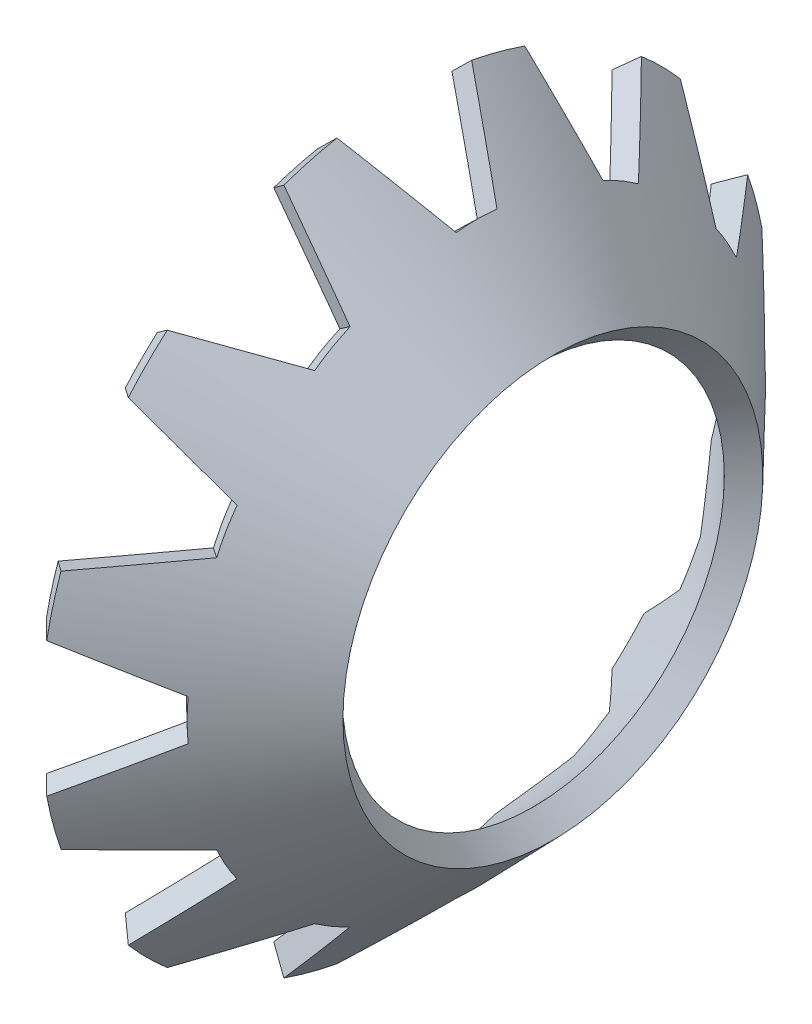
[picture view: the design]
ISO-10303-21;
HEADER;
FILE_DESCRIPTION(('STEP AP214'),'2;1');
FILE_NAME('part.step','',(''),(''),'','','');
FILE_SCHEMA(('AUTOMOTIVE_DESIGN { 1 0 10303 214 1 1 1 1 }'));
ENDSEC;
DATA;
#1=APPLICATION_CONTEXT('core data for automotive mechanical design processes');
#2=APPLICATION_PROTOCOL_DEFINITION('international standard','automotive_design',2000,#1);
#3=PRODUCT_CONTEXT('',#1,'mechanical');
#4=PRODUCT('Part','Part','',(#3));
#5=PRODUCT_RELATED_PRODUCT_CATEGORY('part','',(#4));
#6=PRODUCT_DEFINITION_FORMATION('','',#4);
#7=PRODUCT_DEFINITION_CONTEXT('part definition',#1,'design');
#8=PRODUCT_DEFINITION('design','',#6,#7);
#9=PRODUCT_DEFINITION_SHAPE('','',#8);
#10=(LENGTH_UNIT() NAMED_UNIT(*) SI_UNIT(.MILLI.,.METRE.));
#11=(NAMED_UNIT(*) PLANE_ANGLE_UNIT() SI_UNIT($,.RADIAN.));
#12=(NAMED_UNIT(*) SI_UNIT($,.STERADIAN.) SOLID_ANGLE_UNIT());
#13=UNCERTAINTY_MEASURE_WITH_UNIT(LENGTH_MEASURE(1.E-05),#10,'distance_accuracy_value','');
#14=(GEOMETRIC_REPRESENTATION_CONTEXT(3) GLOBAL_UNCERTAINTY_ASSIGNED_CONTEXT((#13)) GLOBAL_UNIT_ASSIGNED_CONTEXT((#10,
#11,#12)) REPRESENTATION_CONTEXT('',''));
#15=CARTESIAN_POINT('',(0.,0.,0.));
#16=DIRECTION('',(0.,0.,1.));
#17=DIRECTION('',(1.,0.,0.));
#18=AXIS2_PLACEMENT_3D('',#15,#16,#17);
#19=CARTESIAN_POINT('',(-8.15711407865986,0.,0.));
#20=DIRECTION('',(1.,0.,0.));
#21=DIRECTION('',(0.,0.,-1.));
#22=AXIS2_PLACEMENT_3D('',#19,#20,#21);
#23=CONICAL_SURFACE('',#22,7.5832049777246,0.767944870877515);
#24=CARTESIAN_POINT('',(-8.15731407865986,5.7023043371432,4.99857917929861));
#25=CARTESIAN_POINT('',(-8.08534474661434,5.76337965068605,5.03433654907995));
#26=CARTESIAN_POINT('',(-8.0133597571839,5.82444644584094,5.07007692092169));
#27=CARTESIAN_POINT('',(-7.86935846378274,5.94656299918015,5.14152366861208));
#28=CARTESIAN_POINT('',(-7.79734215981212,6.00761275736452,5.17723004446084));
#29=CARTESIAN_POINT('',(-7.72531019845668,6.06865399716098,5.21291942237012));
#30=B_SPLINE_CURVE_WITH_KNOTS('',3,(#24,#25,#26,#27,#28,#29),.UNSPECIFIED.,.F.,.F.,(4,2,4),(0.,
0.302812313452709,0.605624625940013),.UNSPECIFIED.);
#31=CARTESIAN_POINT('',(-8.15711407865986,5.7024740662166,4.99867855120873));
#32=VERTEX_POINT('',#31);
#33=CARTESIAN_POINT('',(-7.72551019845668,6.0684845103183,5.21282032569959));
#34=VERTEX_POINT('',#33);
#35=EDGE_CURVE('E1146',#32,#34,#30,.T.);
#36=ORIENTED_EDGE('',*,*,#35,.F.);
#37=CARTESIAN_POINT('',(-8.15711407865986,0.,0.));
#38=DIRECTION('',(-1.,0.,0.));
#39=DIRECTION('',(0.,0.,1.));
#40=AXIS2_PLACEMENT_3D('',#37,#38,#39);
#41=CIRCLE('',#40,7.5832049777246);
#42=CARTESIAN_POINT('',(-8.15711407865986,4.99867855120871,5.70247406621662));
#43=VERTEX_POINT('',#42);
#44=EDGE_CURVE('E1163',#43,#32,#41,.T.);
#45=ORIENTED_EDGE('',*,*,#44,.F.);
#46=CARTESIAN_POINT('',(-7.72531019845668,5.2129194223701,6.068653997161));
#47=CARTESIAN_POINT('',(-7.79734215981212,5.17723004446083,6.00761275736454));
#48=CARTESIAN_POINT('',(-7.86935846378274,5.14152366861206,5.94656299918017));
#49=CARTESIAN_POINT('',(-8.0133597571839,5.07007692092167,5.82444644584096));
#50=CARTESIAN_POINT('',(-8.08534474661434,5.03433654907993,5.76337965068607));
#51=CARTESIAN_POINT('',(-8.15731407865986,4.99857917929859,5.70230433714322));
#52=B_SPLINE_CURVE_WITH_KNOTS('',3,(#46,#47,#48,#49,#50,#51),.UNSPECIFIED.,.F.,.F.,(4,2,4),(0.,
0.302812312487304,0.605624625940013),.UNSPECIFIED.);
#53=CARTESIAN_POINT('',(-7.72551019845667,5.21282032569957,6.06848451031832));
#54=VERTEX_POINT('',#53);
#55=EDGE_CURVE('E374',#54,#43,#52,.T.);
#56=ORIENTED_EDGE('',*,*,#55,.F.);
#57=CARTESIAN_POINT('',(-7.72551019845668,0.,0.));
#58=DIRECTION('',(-1.,0.,0.));
#59=DIRECTION('',(0.,0.,1.));
#60=AXIS2_PLACEMENT_3D('',#57,#58,#59);
#61=CIRCLE('',#60,8.);
#62=EDGE_CURVE('E372',#54,#34,#61,.T.);
#63=ORIENTED_EDGE('',*,*,#62,.T.);
#64=EDGE_LOOP('',(#36,#45,#56,#63));
#65=FACE_BOUND('',#64,.T.);
#66=ADVANCED_FACE('F32',(#65),#23,.T.);
#67=CARTESIAN_POINT('',(-7.72531019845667,-7.54884764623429,-2.6491488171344));
#68=CARTESIAN_POINT('',(-7.79734215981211,-7.48741911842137,-2.6141302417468));
#69=CARTESIAN_POINT('',(-7.86935846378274,-7.42597161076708,-2.57911278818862));
#70=CARTESIAN_POINT('',(-8.0133597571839,-7.30303863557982,-2.50908012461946));
#71=CARTESIAN_POINT('',(-8.08534474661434,-7.24155316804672,-2.4740649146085));
#72=CARTESIAN_POINT('',(-8.15731407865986,-7.18004872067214,-2.43905082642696));
#73=B_SPLINE_CURVE_WITH_KNOTS('',3,(#67,#68,#69,#70,#71,#72),.UNSPECIFIED.,.F.,.F.,(4,2,4),(0.,
0.30281231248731,0.605624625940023),.UNSPECIFIED.);
#74=CARTESIAN_POINT('',(-7.72551019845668,-7.54867708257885,-2.6490515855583));
#75=VERTEX_POINT('',#74);
#76=CARTESIAN_POINT('',(-8.15711407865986,-7.18021964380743,-2.43914813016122));
#77=VERTEX_POINT('',#76);
#78=EDGE_CURVE('E970',#75,#77,#73,.T.);
#79=ORIENTED_EDGE('',*,*,#78,.F.);
#80=CARTESIAN_POINT('',(-7.72551019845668,-7.86187191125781,-1.48019257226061));
#81=VERTEX_POINT('',#80);
#82=EDGE_CURVE('E797',#75,#81,#61,.T.);
#83=ORIENTED_EDGE('',*,*,#82,.T.);
#84=CARTESIAN_POINT('',(-8.15731407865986,-7.43763000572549,-1.47774438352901));
#85=CARTESIAN_POINT('',(-8.08534474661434,-7.50840146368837,-1.47817351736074));
#86=CARTESIAN_POINT('',(-8.01335975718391,-7.57915704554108,-1.47859218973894));
#87=CARTESIAN_POINT('',(-7.86935846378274,-7.72063645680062,-1.479408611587));
#88=CARTESIAN_POINT('',(-7.79734215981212,-7.79136028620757,-1.47980636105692));
#89=CARTESIAN_POINT('',(-7.72531019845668,-7.86206823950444,-1.48019364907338));
#90=B_SPLINE_CURVE_WITH_KNOTS('',3,(#84,#85,#86,#87,#88,#89),.UNSPECIFIED.,.F.,.F.,(4,2,4),(0.,
0.302812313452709,0.605624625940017),.UNSPECIFIED.);
#91=CARTESIAN_POINT('',(-8.15711407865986,-7.43782668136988,-1.4777455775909));
#92=VERTEX_POINT('',#91);
#93=EDGE_CURVE('E354',#92,#81,#90,.T.);
#94=ORIENTED_EDGE('',*,*,#93,.F.);
#95=EDGE_CURVE('E740',#77,#92,#41,.T.);
#96=ORIENTED_EDGE('',*,*,#95,.F.);
#97=EDGE_LOOP('',(#79,#83,#94,#96));
#98=FACE_BOUND('',#97,.T.);
#99=ADVANCED_FACE('F703',(#98),#23,.T.);
#100=CARTESIAN_POINT('',(-8.15731407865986,-2.43905082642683,-7.18004872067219));
#101=CARTESIAN_POINT('',(-8.08534474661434,-2.47406491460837,-7.24155316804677));
#102=CARTESIAN_POINT('',(-8.0133597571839,-2.50908012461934,-7.30303863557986));
#103=CARTESIAN_POINT('',(-7.86935846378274,-2.57911278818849,-7.42597161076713));
#104=CARTESIAN_POINT('',(-7.79734215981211,-2.61413024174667,-7.48741911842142));
#105=CARTESIAN_POINT('',(-7.72531019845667,-2.64914881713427,-7.54884764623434));
#106=B_SPLINE_CURVE_WITH_KNOTS('',3,(#100,#101,#102,#103,#104,#105),.UNSPECIFIED.,.F.,.F.,(4,2,
4),(0.,0.302812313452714,0.605624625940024),.UNSPECIFIED.);
#107=CARTESIAN_POINT('',(-8.15711407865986,-2.4391481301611,-7.18021964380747));
#108=VERTEX_POINT('',#107);
#109=CARTESIAN_POINT('',(-7.72551019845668,-2.64905158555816,-7.54867708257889));
#110=VERTEX_POINT('',#109);
#111=EDGE_CURVE('E1334',#108,#110,#106,.T.);
#112=ORIENTED_EDGE('',*,*,#111,.F.);
#113=CARTESIAN_POINT('',(-8.15711407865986,-1.47774557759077,-7.4378266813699));
#114=VERTEX_POINT('',#113);
#115=EDGE_CURVE('E739',#114,#108,#41,.T.);
#116=ORIENTED_EDGE('',*,*,#115,.F.);
#117=CARTESIAN_POINT('',(-7.72531019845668,-1.48019364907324,-7.86206823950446));
#118=CARTESIAN_POINT('',(-7.79734215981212,-1.47980636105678,-7.79136028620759));
#119=CARTESIAN_POINT('',(-7.86935846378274,-1.47940861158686,-7.72063645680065));
#120=CARTESIAN_POINT('',(-8.01335975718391,-1.47859218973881,-7.5791570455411));
#121=CARTESIAN_POINT('',(-8.08534474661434,-1.47817351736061,-7.50840146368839));
#122=CARTESIAN_POINT('',(-8.15731407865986,-1.47774438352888,-7.43763000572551));
#123=B_SPLINE_CURVE_WITH_KNOTS('',3,(#117,#118,#119,#120,#121,#122),.UNSPECIFIED.,.F.,.F.,(4,2,
4),(0.,0.302812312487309,0.605624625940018),.UNSPECIFIED.);
#124=CARTESIAN_POINT('',(-7.72551019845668,-1.48019257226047,-7.86187191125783));
#125=VERTEX_POINT('',#124);
#126=EDGE_CURVE('E867',#125,#114,#123,.T.);
#127=ORIENTED_EDGE('',*,*,#126,.F.);
#128=EDGE_CURVE('E806',#125,#110,#61,.T.);
#129=ORIENTED_EDGE('',*,*,#128,.T.);
#130=EDGE_LOOP('',(#112,#116,#127,#129));
#131=FACE_BOUND('',#130,.T.);
#132=ADVANCED_FACE('F708',(#131),#23,.T.);
#133=CARTESIAN_POINT('',(-7.72531019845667,2.64914881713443,-7.54884764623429));
#134=CARTESIAN_POINT('',(-7.79734215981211,2.61413024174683,-7.48741911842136));
#135=CARTESIAN_POINT('',(-7.86935846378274,2.57911278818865,-7.42597161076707));
#136=CARTESIAN_POINT('',(-8.0133597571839,2.50908012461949,-7.30303863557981));
#137=CARTESIAN_POINT('',(-8.08534474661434,2.47406491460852,-7.24155316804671));
#138=CARTESIAN_POINT('',(-8.15731407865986,2.43905082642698,-7.18004872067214));
#139=B_SPLINE_CURVE_WITH_KNOTS('',3,(#133,#134,#135,#136,#137,#138),.UNSPECIFIED.,.F.,.F.,(4,2,
4),(0.,0.30281231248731,0.605624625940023),.UNSPECIFIED.);
#140=CARTESIAN_POINT('',(-7.72551019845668,2.64905158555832,-7.54867708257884));
#141=VERTEX_POINT('',#140);
#142=CARTESIAN_POINT('',(-8.15711407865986,2.43914813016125,-7.18021964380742));
#143=VERTEX_POINT('',#142);
#144=EDGE_CURVE('E821',#141,#143,#139,.T.);
#145=ORIENTED_EDGE('',*,*,#144,.F.);
#146=CARTESIAN_POINT('',(-7.72551019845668,1.48019257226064,-7.8618719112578));
#147=VERTEX_POINT('',#146);
#148=EDGE_CURVE('E772',#141,#147,#61,.T.);
#149=ORIENTED_EDGE('',*,*,#148,.T.);
#150=CARTESIAN_POINT('',(-8.15731407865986,1.47774438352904,-7.43763000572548));
#151=CARTESIAN_POINT('',(-8.08534474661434,1.47817351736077,-7.50840146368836));
#152=CARTESIAN_POINT('',(-8.01335975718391,1.47859218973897,-7.57915704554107));
#153=CARTESIAN_POINT('',(-7.86935846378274,1.47940861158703,-7.72063645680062));
#154=CARTESIAN_POINT('',(-7.79734215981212,1.47980636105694,-7.79136028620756));
#155=CARTESIAN_POINT('',(-7.72531019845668,1.48019364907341,-7.86206823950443));
#156=B_SPLINE_CURVE_WITH_KNOTS('',3,(#150,#151,#152,#153,#154,#155),.UNSPECIFIED.,.F.,.F.,(4,2,
4),(0.,0.302812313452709,0.605624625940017),.UNSPECIFIED.);
#157=CARTESIAN_POINT('',(-8.15711407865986,1.47774557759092,-7.43782668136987));
#158=VERTEX_POINT('',#157);
#159=EDGE_CURVE('E819',#158,#147,#156,.T.);
#160=ORIENTED_EDGE('',*,*,#159,.F.);
#161=EDGE_CURVE('E743',#143,#158,#41,.T.);
#162=ORIENTED_EDGE('',*,*,#161,.F.);
#163=EDGE_LOOP('',(#145,#149,#160,#162));
#164=FACE_BOUND('',#163,.T.);
#165=ADVANCED_FACE('F817',(#164),#23,.T.);
#166=CARTESIAN_POINT('',(-8.15731407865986,4.99857917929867,-5.70230433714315));
#167=CARTESIAN_POINT('',(-8.08534474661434,5.03433654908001,-5.763379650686));
#168=CARTESIAN_POINT('',(-8.0133597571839,5.07007692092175,-5.82444644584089));
#169=CARTESIAN_POINT('',(-7.86935846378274,5.14152366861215,-5.9465629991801));
#170=CARTESIAN_POINT('',(-7.79734215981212,5.17723004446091,-6.00761275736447));
#171=CARTESIAN_POINT('',(-7.72531019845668,5.21291942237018,-6.06865399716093));
#172=B_SPLINE_CURVE_WITH_KNOTS('',3,(#166,#167,#168,#169,#170,#171),.UNSPECIFIED.,.F.,.F.,(4,2,
4),(0.,0.302812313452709,0.605624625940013),.UNSPECIFIED.);
#173=CARTESIAN_POINT('',(-8.15711407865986,4.99867855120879,-5.70247406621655));
#174=VERTEX_POINT('',#173);
#175=CARTESIAN_POINT('',(-7.72551019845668,5.21282032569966,-6.06848451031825));
#176=VERTEX_POINT('',#175);
#177=EDGE_CURVE('E907',#174,#176,#172,.T.);
#178=ORIENTED_EDGE('',*,*,#177,.F.);
#179=CARTESIAN_POINT('',(-8.15711407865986,5.70247406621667,-4.99867855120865));
#180=VERTEX_POINT('',#179);
#181=EDGE_CURVE('E751',#180,#174,#41,.T.);
#182=ORIENTED_EDGE('',*,*,#181,.F.);
#183=CARTESIAN_POINT('',(-7.72531019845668,6.06865399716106,-5.21291942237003));
#184=CARTESIAN_POINT('',(-7.79734215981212,6.00761275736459,-5.17723004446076));
#185=CARTESIAN_POINT('',(-7.86935846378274,5.94656299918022,-5.141523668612));
#186=CARTESIAN_POINT('',(-8.0133597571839,5.82444644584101,-5.07007692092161));
#187=CARTESIAN_POINT('',(-8.08534474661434,5.76337965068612,-5.03433654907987));
#188=CARTESIAN_POINT('',(-8.15731407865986,5.70230433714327,-4.99857917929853));
#189=B_SPLINE_CURVE_WITH_KNOTS('',3,(#183,#184,#185,#186,#187,#188),.UNSPECIFIED.,.F.,.F.,(4,2,
4),(0.,0.302812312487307,0.605624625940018),.UNSPECIFIED.);
#190=CARTESIAN_POINT('',(-7.72551019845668,6.06848451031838,-5.21282032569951));
#191=VERTEX_POINT('',#190);
#192=EDGE_CURVE('E834',#191,#180,#189,.T.);
#193=ORIENTED_EDGE('',*,*,#192,.F.);
#194=EDGE_CURVE('E765',#191,#176,#61,.T.);
#195=ORIENTED_EDGE('',*,*,#194,.T.);
#196=EDGE_LOOP('',(#178,#182,#193,#195));
#197=FACE_BOUND('',#196,.T.);
#198=ADVANCED_FACE('F1286',(#197),#23,.T.);
#199=CARTESIAN_POINT('',(-8.15731407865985,7.1800487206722,-2.43905082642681));
#200=CARTESIAN_POINT('',(-8.08534474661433,7.24155316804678,-2.47406491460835));
#201=CARTESIAN_POINT('',(-8.0133597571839,7.30303863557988,-2.50908012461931));
#202=CARTESIAN_POINT('',(-7.86935846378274,7.42597161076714,-2.57911278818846));
#203=CARTESIAN_POINT('',(-7.79734215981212,7.48741911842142,-2.61413024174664));
#204=CARTESIAN_POINT('',(-7.72531019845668,7.54884764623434,-2.64914881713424));
#205=B_SPLINE_CURVE_WITH_KNOTS('',3,(#199,#200,#201,#202,#203,#204),.UNSPECIFIED.,.F.,.F.,(4,2,
4),(0.,0.302812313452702,0.605624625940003),.UNSPECIFIED.);
#206=CARTESIAN_POINT('',(-8.15711407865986,7.18021964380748,-2.43914813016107));
#207=VERTEX_POINT('',#206);
#208=CARTESIAN_POINT('',(-7.72551019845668,7.5486770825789,-2.64905158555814));
#209=VERTEX_POINT('',#208);
#210=EDGE_CURVE('E886',#207,#209,#205,.T.);
#211=ORIENTED_EDGE('',*,*,#210,.F.);
#212=CARTESIAN_POINT('',(-8.15711407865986,7.43782668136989,-1.47774557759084));
#213=VERTEX_POINT('',#212);
#214=EDGE_CURVE('E746',#213,#207,#41,.T.);
#215=ORIENTED_EDGE('',*,*,#214,.F.);
#216=CARTESIAN_POINT('',(-7.72531019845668,7.86206823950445,-1.48019364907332));
#217=CARTESIAN_POINT('',(-7.79734215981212,7.79136028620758,-1.47980636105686));
#218=CARTESIAN_POINT('',(-7.86935846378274,7.72063645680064,-1.47940861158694));
#219=CARTESIAN_POINT('',(-8.01335975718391,7.57915704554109,-1.47859218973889));
#220=CARTESIAN_POINT('',(-8.08534474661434,7.50840146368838,-1.47817351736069));
#221=CARTESIAN_POINT('',(-8.15731407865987,7.4376300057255,-1.47774438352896));
#222=B_SPLINE_CURVE_WITH_KNOTS('',3,(#216,#217,#218,#219,#220,#221),.UNSPECIFIED.,.F.,.F.,(4,2,
4),(0.,0.302812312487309,0.605624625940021),.UNSPECIFIED.);
#223=CARTESIAN_POINT('',(-7.72551019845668,7.86187191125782,-1.48019257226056));
#224=VERTEX_POINT('',#223);
#225=EDGE_CURVE('E679',#224,#213,#222,.T.);
#226=ORIENTED_EDGE('',*,*,#225,.F.);
#227=EDGE_CURVE('E763',#224,#209,#61,.T.);
#228=ORIENTED_EDGE('',*,*,#227,.T.);
#229=EDGE_LOOP('',(#211,#215,#226,#228));
#230=FACE_BOUND('',#229,.T.);
#231=ADVANCED_FACE('F1183',(#230),#23,.T.);
#232=CARTESIAN_POINT('',(-8.15731407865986,-4.99857917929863,5.70230433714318));
#233=CARTESIAN_POINT('',(-8.08534474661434,-5.03433654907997,5.76337965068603));
#234=CARTESIAN_POINT('',(-8.01335975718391,-5.07007692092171,5.82444644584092));
#235=CARTESIAN_POINT('',(-7.86935846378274,-5.14152366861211,5.94656299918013));
#236=CARTESIAN_POINT('',(-7.79734215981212,-5.17723004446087,6.0076127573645));
#237=CARTESIAN_POINT('',(-7.72531019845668,-5.21291942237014,6.06865399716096));
#238=B_SPLINE_CURVE_WITH_KNOTS('',3,(#232,#233,#234,#235,#236,#237),.UNSPECIFIED.,.F.,.F.,(4,2,
4),(0.,0.302812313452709,0.605624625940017),.UNSPECIFIED.);
#239=CARTESIAN_POINT('',(-8.15711407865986,-4.99867855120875,5.70247406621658));
#240=VERTEX_POINT('',#239);
#241=CARTESIAN_POINT('',(-7.72551019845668,-5.21282032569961,6.06848451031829));
#242=VERTEX_POINT('',#241);
#243=EDGE_CURVE('E1104',#240,#242,#238,.T.);
#244=ORIENTED_EDGE('',*,*,#243,.F.);
#245=CARTESIAN_POINT('',(-8.15711407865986,-5.70247406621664,4.99867855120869));
#246=VERTEX_POINT('',#245);
#247=EDGE_CURVE('E1232',#246,#240,#41,.T.);
#248=ORIENTED_EDGE('',*,*,#247,.F.);
#249=CARTESIAN_POINT('',(-7.72531019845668,-6.06865399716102,5.21291942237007));
#250=CARTESIAN_POINT('',(-7.79734215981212,-6.00761275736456,5.1772300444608));
#251=CARTESIAN_POINT('',(-7.86935846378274,-5.94656299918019,5.14152366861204));
#252=CARTESIAN_POINT('',(-8.0133597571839,-5.82444644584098,5.07007692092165));
#253=CARTESIAN_POINT('',(-8.08534474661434,-5.76337965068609,5.03433654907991));
#254=CARTESIAN_POINT('',(-8.15731407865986,-5.70230433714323,4.99857917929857));
#255=B_SPLINE_CURVE_WITH_KNOTS('',3,(#249,#250,#251,#252,#253,#254),.UNSPECIFIED.,.F.,.F.,(4,2,
4),(0.,0.302812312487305,0.605624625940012),.UNSPECIFIED.);
#256=CARTESIAN_POINT('',(-7.72551019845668,-6.06848451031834,5.21282032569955));
#257=VERTEX_POINT('',#256);
#258=EDGE_CURVE('E1220',#257,#246,#255,.T.);
#259=ORIENTED_EDGE('',*,*,#258,.F.);
#260=EDGE_CURVE('E786',#257,#242,#61,.T.);
#261=ORIENTED_EDGE('',*,*,#260,.T.);
#262=EDGE_LOOP('',(#244,#248,#259,#261));
#263=FACE_BOUND('',#262,.T.);
#264=ADVANCED_FACE('F1230',(#263),#23,.T.);
#265=CARTESIAN_POINT('',(-7.72531019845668,1.4801936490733,7.86206823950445));
#266=CARTESIAN_POINT('',(-7.79734215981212,1.47980636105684,7.79136028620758));
#267=CARTESIAN_POINT('',(-7.86935846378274,1.47940861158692,7.72063645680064));
#268=CARTESIAN_POINT('',(-8.01335975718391,1.47859218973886,7.57915704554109));
#269=CARTESIAN_POINT('',(-8.08534474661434,1.47817351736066,7.50840146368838));
#270=CARTESIAN_POINT('',(-8.15731407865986,1.47774438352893,7.4376300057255));
#271=B_SPLINE_CURVE_WITH_KNOTS('',3,(#265,#266,#267,#268,#269,#270),.UNSPECIFIED.,.F.,.F.,(4,2,
4),(0.,0.302812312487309,0.605624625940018),.UNSPECIFIED.);
#272=CARTESIAN_POINT('',(-7.72551019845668,1.48019257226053,7.86187191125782));
#273=VERTEX_POINT('',#272);
#274=CARTESIAN_POINT('',(-8.15711407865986,1.47774557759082,7.43782668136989));
#275=VERTEX_POINT('',#274);
#276=EDGE_CURVE('E1070',#273,#275,#271,.T.);
#277=ORIENTED_EDGE('',*,*,#276,.F.);
#278=CARTESIAN_POINT('',(-7.72551019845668,2.64905158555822,7.54867708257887));
#279=VERTEX_POINT('',#278);
#280=EDGE_CURVE('E778',#273,#279,#61,.T.);
#281=ORIENTED_EDGE('',*,*,#280,.T.);
#282=CARTESIAN_POINT('',(-8.15731407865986,2.43905082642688,7.18004872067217));
#283=CARTESIAN_POINT('',(-8.08534474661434,2.47406491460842,7.24155316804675));
#284=CARTESIAN_POINT('',(-8.0133597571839,2.50908012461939,7.30303863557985));
#285=CARTESIAN_POINT('',(-7.86935846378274,2.57911278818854,7.42597161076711));
#286=CARTESIAN_POINT('',(-7.79734215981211,2.61413024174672,7.4874191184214));
#287=CARTESIAN_POINT('',(-7.72531019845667,2.64914881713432,7.54884764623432));
#288=B_SPLINE_CURVE_WITH_KNOTS('',3,(#282,#283,#284,#285,#286,#287),.UNSPECIFIED.,.F.,.F.,(4,2,
4),(0.,0.302812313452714,0.605624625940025),.UNSPECIFIED.);
#289=CARTESIAN_POINT('',(-8.15711407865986,2.43914813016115,7.18021964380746));
#290=VERTEX_POINT('',#289);
#291=EDGE_CURVE('E1193',#290,#279,#288,.T.);
#292=ORIENTED_EDGE('',*,*,#291,.F.);
#293=EDGE_CURVE('E1164',#275,#290,#41,.T.);
#294=ORIENTED_EDGE('',*,*,#293,.F.);
#295=EDGE_LOOP('',(#277,#281,#292,#294));
#296=FACE_BOUND('',#295,.T.);
#297=ADVANCED_FACE('F1194',(#296),#23,.T.);
#298=CARTESIAN_POINT('',(-8.15731407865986,-7.18004872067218,2.43905082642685));
#299=CARTESIAN_POINT('',(-8.08534474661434,-7.24155316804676,2.47406491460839));
#300=CARTESIAN_POINT('',(-8.0133597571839,-7.30303863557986,2.50908012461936));
#301=CARTESIAN_POINT('',(-7.86935846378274,-7.42597161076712,2.57911278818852));
#302=CARTESIAN_POINT('',(-7.79734215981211,-7.48741911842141,2.6141302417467));
#303=CARTESIAN_POINT('',(-7.72531019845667,-7.54884764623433,2.6491488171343));
#304=B_SPLINE_CURVE_WITH_KNOTS('',3,(#298,#299,#300,#301,#302,#303),.UNSPECIFIED.,.F.,.F.,(4,2,
4),(0.,0.302812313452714,0.605624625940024),.UNSPECIFIED.);
#305=CARTESIAN_POINT('',(-8.15711407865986,-7.18021964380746,2.43914813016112));
#306=VERTEX_POINT('',#305);
#307=CARTESIAN_POINT('',(-7.72551019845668,-7.54867708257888,2.64905158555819));
#308=VERTEX_POINT('',#307);
#309=EDGE_CURVE('E1028',#306,#308,#304,.T.);
#310=ORIENTED_EDGE('',*,*,#309,.F.);
#311=CARTESIAN_POINT('',(-8.15711407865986,-7.4378266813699,1.47774557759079));
#312=VERTEX_POINT('',#311);
#313=EDGE_CURVE('E745',#312,#306,#41,.T.);
#314=ORIENTED_EDGE('',*,*,#313,.F.);
#315=CARTESIAN_POINT('',(-7.72531019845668,-7.86206823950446,1.48019364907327));
#316=CARTESIAN_POINT('',(-7.79734215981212,-7.79136028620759,1.47980636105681));
#317=CARTESIAN_POINT('',(-7.86935846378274,-7.72063645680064,1.47940861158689));
#318=CARTESIAN_POINT('',(-8.01335975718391,-7.5791570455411,1.47859218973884));
#319=CARTESIAN_POINT('',(-8.08534474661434,-7.50840146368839,1.47817351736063));
#320=CARTESIAN_POINT('',(-8.15731407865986,-7.43763000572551,1.47774438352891));
#321=B_SPLINE_CURVE_WITH_KNOTS('',3,(#315,#316,#317,#318,#319,#320),.UNSPECIFIED.,.F.,.F.,(4,2,
4),(0.,0.302812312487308,0.605624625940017),.UNSPECIFIED.);
#322=CARTESIAN_POINT('',(-7.72551019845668,-7.86187191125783,1.4801925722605));
#323=VERTEX_POINT('',#322);
#324=EDGE_CURVE('E1201',#323,#312,#321,.T.);
#325=ORIENTED_EDGE('',*,*,#324,.F.);
#326=EDGE_CURVE('E791',#323,#308,#61,.T.);
#327=ORIENTED_EDGE('',*,*,#326,.T.);
#328=EDGE_LOOP('',(#310,#314,#325,#327));
#329=FACE_BOUND('',#328,.T.);
#330=ADVANCED_FACE('F1271',(#329),#23,.T.);
#331=CARTESIAN_POINT('',(-7.72531019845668,7.54884764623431,2.64914881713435));
#332=CARTESIAN_POINT('',(-7.79734215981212,7.48741911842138,2.61413024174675));
#333=CARTESIAN_POINT('',(-7.86935846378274,7.4259716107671,2.57911278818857));
#334=CARTESIAN_POINT('',(-8.0133597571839,7.30303863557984,2.50908012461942));
#335=CARTESIAN_POINT('',(-8.08534474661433,7.24155316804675,2.47406491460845));
#336=CARTESIAN_POINT('',(-8.15731407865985,7.18004872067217,2.43905082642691));
#337=B_SPLINE_CURVE_WITH_KNOTS('',3,(#331,#332,#333,#334,#335,#336),.UNSPECIFIED.,.F.,.F.,(4,2,
4),(0.,0.3028123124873,0.605624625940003),.UNSPECIFIED.);
#338=CARTESIAN_POINT('',(-7.72551019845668,7.54867708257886,2.64905158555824));
#339=VERTEX_POINT('',#338);
#340=CARTESIAN_POINT('',(-8.15711407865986,7.18021964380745,2.43914813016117));
#341=VERTEX_POINT('',#340);
#342=EDGE_CURVE('E373',#339,#341,#337,.T.);
#343=ORIENTED_EDGE('',*,*,#342,.F.);
#344=CARTESIAN_POINT('',(-7.72551019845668,7.86187191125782,1.48019257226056));
#345=VERTEX_POINT('',#344);
#346=EDGE_CURVE('E762',#339,#345,#61,.T.);
#347=ORIENTED_EDGE('',*,*,#346,.T.);
#348=CARTESIAN_POINT('',(-8.15731407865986,7.4376300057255,1.47774438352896));
#349=CARTESIAN_POINT('',(-8.08534474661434,7.50840146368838,1.47817351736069));
#350=CARTESIAN_POINT('',(-8.01335975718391,7.57915704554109,1.47859218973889));
#351=CARTESIAN_POINT('',(-7.86935846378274,7.72063645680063,1.47940861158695));
#352=CARTESIAN_POINT('',(-7.79734215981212,7.79136028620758,1.47980636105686));
#353=CARTESIAN_POINT('',(-7.72531019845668,7.86206823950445,1.48019364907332));
#354=B_SPLINE_CURVE_WITH_KNOTS('',3,(#348,#349,#350,#351,#352,#353),.UNSPECIFIED.,.F.,.F.,(4,2,
4),(0.,0.302812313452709,0.605624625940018),.UNSPECIFIED.);
#355=CARTESIAN_POINT('',(-8.15711407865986,7.43782668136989,1.47774557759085));
#356=VERTEX_POINT('',#355);
#357=EDGE_CURVE('E1173',#356,#345,#354,.T.);
#358=ORIENTED_EDGE('',*,*,#357,.F.);
#359=EDGE_CURVE('E752',#341,#356,#41,.T.);
#360=ORIENTED_EDGE('',*,*,#359,.F.);
#361=EDGE_LOOP('',(#343,#347,#358,#360));
#362=FACE_BOUND('',#361,.T.);
#363=ADVANCED_FACE('F718',(#362),#23,.T.);
#364=CARTESIAN_POINT('',(-7.72531019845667,-2.64914881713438,7.5488476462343));
#365=CARTESIAN_POINT('',(-7.79734215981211,-2.61413024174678,7.48741911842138));
#366=CARTESIAN_POINT('',(-7.86935846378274,-2.57911278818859,7.42597161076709));
#367=CARTESIAN_POINT('',(-8.0133597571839,-2.50908012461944,7.30303863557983));
#368=CARTESIAN_POINT('',(-8.08534474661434,-2.47406491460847,7.24155316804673));
#369=CARTESIAN_POINT('',(-8.15731407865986,-2.43905082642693,7.18004872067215));
#370=B_SPLINE_CURVE_WITH_KNOTS('',3,(#364,#365,#366,#367,#368,#369),.UNSPECIFIED.,.F.,.F.,(4,2,
4),(0.,0.302812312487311,0.605624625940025),.UNSPECIFIED.);
#371=CARTESIAN_POINT('',(-7.72551019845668,-2.64905158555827,7.54867708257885));
#372=VERTEX_POINT('',#371);
#373=CARTESIAN_POINT('',(-8.15711407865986,-2.4391481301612,7.18021964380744));
#374=VERTEX_POINT('',#373);
#375=EDGE_CURVE('E1080',#372,#374,#370,.T.);
#376=ORIENTED_EDGE('',*,*,#375,.F.);
#377=CARTESIAN_POINT('',(-7.72551019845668,-1.48019257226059,7.86187191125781));
#378=VERTEX_POINT('',#377);
#379=EDGE_CURVE('E780',#372,#378,#61,.T.);
#380=ORIENTED_EDGE('',*,*,#379,.T.);
#381=CARTESIAN_POINT('',(-8.15731407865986,-1.47774438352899,7.43763000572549));
#382=CARTESIAN_POINT('',(-8.08534474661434,-1.47817351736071,7.50840146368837));
#383=CARTESIAN_POINT('',(-8.01335975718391,-1.47859218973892,7.57915704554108));
#384=CARTESIAN_POINT('',(-7.86935846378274,-1.47940861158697,7.72063645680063));
#385=CARTESIAN_POINT('',(-7.79734215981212,-1.47980636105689,7.79136028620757));
#386=CARTESIAN_POINT('',(-7.72531019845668,-1.48019364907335,7.86206823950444));
#387=B_SPLINE_CURVE_WITH_KNOTS('',3,(#381,#382,#383,#384,#385,#386),.UNSPECIFIED.,.F.,.F.,(4,2,
4),(0.,0.302812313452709,0.605624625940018),.UNSPECIFIED.);
#388=CARTESIAN_POINT('',(-8.15711407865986,-1.47774557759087,7.43782668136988));
#389=VERTEX_POINT('',#388);
#390=EDGE_CURVE('E1044',#389,#378,#387,.T.);
#391=ORIENTED_EDGE('',*,*,#390,.F.);
#392=EDGE_CURVE('E1166',#374,#389,#41,.T.);
#393=ORIENTED_EDGE('',*,*,#392,.F.);
#394=EDGE_LOOP('',(#376,#380,#391,#393));
#395=FACE_BOUND('',#394,.T.);
#396=ADVANCED_FACE('F712',(#395),#23,.T.);
#397=CARTESIAN_POINT('',(-8.15731407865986,-5.70230433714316,-4.99857917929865));
#398=CARTESIAN_POINT('',(-8.08534474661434,-5.76337965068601,-5.03433654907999));
#399=CARTESIAN_POINT('',(-8.01335975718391,-5.82444644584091,-5.07007692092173));
#400=CARTESIAN_POINT('',(-7.86935846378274,-5.94656299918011,-5.14152366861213));
#401=CARTESIAN_POINT('',(-7.79734215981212,-6.00761275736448,-5.17723004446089));
#402=CARTESIAN_POINT('',(-7.72531019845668,-6.06865399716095,-5.21291942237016));
#403=B_SPLINE_CURVE_WITH_KNOTS('',3,(#397,#398,#399,#400,#401,#402),.UNSPECIFIED.,.F.,.F.,(4,2,
4),(0.,0.302812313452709,0.605624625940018),.UNSPECIFIED.);
#404=CARTESIAN_POINT('',(-8.15711407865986,-5.70247406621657,-4.99867855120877));
#405=VERTEX_POINT('',#404);
#406=CARTESIAN_POINT('',(-7.72551019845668,-6.06848451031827,-5.21282032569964));
#407=VERTEX_POINT('',#406);
#408=EDGE_CURVE('E723',#405,#407,#403,.T.);
#409=ORIENTED_EDGE('',*,*,#408,.F.);
#410=CARTESIAN_POINT('',(-8.15711407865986,-4.99867855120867,-5.70247406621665));
#411=VERTEX_POINT('',#410);
#412=EDGE_CURVE('E726',#411,#405,#41,.T.);
#413=ORIENTED_EDGE('',*,*,#412,.F.);
#414=CARTESIAN_POINT('',(-7.72531019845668,-5.21291942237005,-6.06865399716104));
#415=CARTESIAN_POINT('',(-7.79734215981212,-5.17723004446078,-6.00761275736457));
#416=CARTESIAN_POINT('',(-7.86935846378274,-5.14152366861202,-5.9465629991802));
#417=CARTESIAN_POINT('',(-8.01335975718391,-5.07007692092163,-5.82444644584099));
#418=CARTESIAN_POINT('',(-8.08534474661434,-5.03433654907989,-5.7633796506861));
#419=CARTESIAN_POINT('',(-8.15731407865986,-4.99857917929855,-5.70230433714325));
#420=B_SPLINE_CURVE_WITH_KNOTS('',3,(#414,#415,#416,#417,#418,#419),.UNSPECIFIED.,.F.,.F.,(4,2,
4),(0.,0.302812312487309,0.605624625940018),.UNSPECIFIED.);
#421=CARTESIAN_POINT('',(-7.72551019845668,-5.21282032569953,-6.06848451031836));
#422=VERTEX_POINT('',#421);
#423=EDGE_CURVE('E930',#422,#411,#420,.T.);
#424=ORIENTED_EDGE('',*,*,#423,.F.);
#425=EDGE_CURVE('E728',#422,#407,#61,.T.);
#426=ORIENTED_EDGE('',*,*,#425,.T.);
#427=EDGE_LOOP('',(#409,#413,#424,#426));
#428=FACE_BOUND('',#427,.T.);
#429=ADVANCED_FACE('F34',(#428),#23,.T.);
#430=CARTESIAN_POINT('',(-4.45838712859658,0.,0.));
#431=DIRECTION('',(-1.,0.,0.));
#432=DIRECTION('',(0.,0.,1.));
#433=AXIS2_PLACEMENT_3D('',#430,#431,#432);
#434=CONICAL_SURFACE('',#433,4.6167950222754,0.802851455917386);
#435=CARTESIAN_POINT('',(-7.72571019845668,7.54890277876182,2.64903389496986));
#436=CARTESIAN_POINT('',(-7.59094019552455,7.396809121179,2.66095303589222));
#437=CARTESIAN_POINT('',(-7.45650423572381,7.24440497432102,2.67270463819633));
#438=CARTESIAN_POINT('',(-7.18844645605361,6.93886481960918,2.69580450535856));
#439=CARTESIAN_POINT('',(-7.0548245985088,6.78572884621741,2.70715278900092));
#440=CARTESIAN_POINT('',(-6.78852653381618,6.47859774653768,2.72937904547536));
#441=CARTESIAN_POINT('',(-6.65585034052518,6.32460260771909,2.74025701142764));
#442=CARTESIAN_POINT('',(-6.39163850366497,6.01558633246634,2.76144775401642));
#443=CARTESIAN_POINT('',(-6.260102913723,5.86056514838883,2.7717605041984));
#444=CARTESIAN_POINT('',(-6.12924030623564,5.70495359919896,2.78174277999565));
#445=B_SPLINE_CURVE_WITH_KNOTS('',3,(#435,#436,#437,#438,#439,#440,#441,#442,#443,#444),
.UNSPECIFIED.,.F.,.F.,(4,2,2,2,4),(0.,0.610686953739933,1.22134542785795,1.83201283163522,
2.44270879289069),.UNSPECIFIED.);
#446=CARTESIAN_POINT('',(-6.13736808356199,5.71461776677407,2.78112263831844));
#447=VERTEX_POINT('',#446);
#448=EDGE_CURVE('E376',#339,#447,#445,.T.);
#449=ORIENTED_EDGE('',*,*,#448,.T.);
#450=CARTESIAN_POINT('',(-6.13704893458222,5.7214478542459,2.7662850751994));
#451=CARTESIAN_POINT('',(-6.14010458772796,5.65735129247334,2.9060720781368));
#452=CARTESIAN_POINT('',(-6.14165108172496,5.58709807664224,3.0423143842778));
#453=CARTESIAN_POINT('',(-6.14172575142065,5.43427833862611,3.30770959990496));
#454=CARTESIAN_POINT('',(-6.14025392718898,5.35171181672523,3.4368625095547));
#455=CARTESIAN_POINT('',(-6.13727294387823,5.26298864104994,3.56247072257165));
#456=B_SPLINE_CURVE_WITH_KNOTS('',3,(#450,#451,#452,#453,#454,#455),.UNSPECIFIED.,.F.,.F.,(4,2,
4),(0.,0.459890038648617,0.919780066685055),.UNSPECIFIED.);
#457=CARTESIAN_POINT('',(-6.13736808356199,5.26583173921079,3.55844283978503));
#458=VERTEX_POINT('',#457);
#459=EDGE_CURVE('E664',#447,#458,#456,.T.);
#460=ORIENTED_EDGE('',*,*,#459,.T.);
#461=CARTESIAN_POINT('',(-6.12924030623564,5.26153671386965,3.54976335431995));
#462=CARTESIAN_POINT('',(-6.260102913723,5.33069758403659,3.68951804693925));
#463=CARTESIAN_POINT('',(-6.39163850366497,5.39927707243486,3.82892670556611));
#464=CARTESIAN_POINT('',(-6.65585034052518,5.5354334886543,4.10713802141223));
#465=CARTESIAN_POINT('',(-6.78852653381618,5.60301046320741,4.24594070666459));
#466=CARTESIAN_POINT('',(-7.0548245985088,5.73732751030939,4.52303716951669));
#467=CARTESIAN_POINT('',(-7.18844645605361,5.80406759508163,4.66133095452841));
#468=CARTESIAN_POINT('',(-7.45650423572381,5.93683260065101,4.93748642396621));
#469=CARTESIAN_POINT('',(-7.59094019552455,6.00285748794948,5.07534808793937));
#470=CARTESIAN_POINT('',(-7.72571019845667,6.06858203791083,5.21302462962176));
#471=B_SPLINE_CURVE_WITH_KNOTS('',3,(#461,#462,#463,#464,#465,#466,#467,#468,#469,#470),
.UNSPECIFIED.,.F.,.F.,(4,2,2,2,4),(0.,0.610695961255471,1.22136336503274,1.83202183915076,
2.44270879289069),.UNSPECIFIED.);
#472=EDGE_CURVE('E671',#458,#34,#471,.T.);
#473=ORIENTED_EDGE('',*,*,#472,.T.);
#474=ORIENTED_EDGE('',*,*,#62,.F.);
#475=CARTESIAN_POINT('',(-7.72571019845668,5.21302462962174,6.06858203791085));
#476=CARTESIAN_POINT('',(-7.59094019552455,5.07534808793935,6.00285748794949));
#477=CARTESIAN_POINT('',(-7.45650423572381,4.93748642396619,5.93683260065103));
#478=CARTESIAN_POINT('',(-7.18844645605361,4.66133095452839,5.80406759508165));
#479=CARTESIAN_POINT('',(-7.0548245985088,4.52303716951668,5.7373275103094));
#480=CARTESIAN_POINT('',(-6.78852653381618,4.24594070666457,5.60301046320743));
#481=CARTESIAN_POINT('',(-6.65585034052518,4.10713802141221,5.53543348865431));
#482=CARTESIAN_POINT('',(-6.39163850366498,3.8289267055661,5.39927707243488));
#483=CARTESIAN_POINT('',(-6.260102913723,3.68951804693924,5.3306975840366));
#484=CARTESIAN_POINT('',(-6.12924030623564,3.54976335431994,5.26153671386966));
#485=B_SPLINE_CURVE_WITH_KNOTS('',3,(#475,#476,#477,#478,#479,#480,#481,#482,#483,#484),
.UNSPECIFIED.,.F.,.F.,(4,2,2,2,4),(0.,0.610686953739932,1.22134542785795,1.83201283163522,
2.44270879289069),.UNSPECIFIED.);
#486=CARTESIAN_POINT('',(-6.13736808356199,3.55844283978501,5.2658317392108));
#487=VERTEX_POINT('',#486);
#488=EDGE_CURVE('E359',#54,#487,#485,.T.);
#489=ORIENTED_EDGE('',*,*,#488,.T.);
#490=CARTESIAN_POINT('',(-6.13727294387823,3.56247072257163,5.26298864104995));
#491=CARTESIAN_POINT('',(-6.14025392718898,3.43686250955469,5.35171181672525));
#492=CARTESIAN_POINT('',(-6.14172575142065,3.30770959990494,5.43427833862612));
#493=CARTESIAN_POINT('',(-6.14165108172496,3.04231438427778,5.58709807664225));
#494=CARTESIAN_POINT('',(-6.14010458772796,2.90607207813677,5.65735129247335));
#495=CARTESIAN_POINT('',(-6.13704893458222,2.76628507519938,5.72144785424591));
#496=B_SPLINE_CURVE_WITH_KNOTS('',3,(#490,#491,#492,#493,#494,#495),.UNSPECIFIED.,.F.,.F.,(4,2,
4),(0.,0.459890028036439,0.919780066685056),.UNSPECIFIED.);
#497=CARTESIAN_POINT('',(-6.13736808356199,2.78112263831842,5.71461776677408));
#498=VERTEX_POINT('',#497);
#499=EDGE_CURVE('E343',#487,#498,#496,.T.);
#500=ORIENTED_EDGE('',*,*,#499,.T.);
#501=CARTESIAN_POINT('',(-6.12924030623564,2.78174277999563,5.70495359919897));
#502=CARTESIAN_POINT('',(-6.260102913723,2.77176050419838,5.86056514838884));
#503=CARTESIAN_POINT('',(-6.39163850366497,2.7614477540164,6.01558633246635));
#504=CARTESIAN_POINT('',(-6.65585034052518,2.74025701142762,6.3246026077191));
#505=CARTESIAN_POINT('',(-6.78852653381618,2.72937904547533,6.4785977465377));
#506=CARTESIAN_POINT('',(-7.0548245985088,2.7071527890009,6.78572884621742));
#507=CARTESIAN_POINT('',(-7.18844645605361,2.69580450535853,6.9388648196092));
#508=CARTESIAN_POINT('',(-7.45650423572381,2.6727046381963,7.24440497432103));
#509=CARTESIAN_POINT('',(-7.59094019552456,2.66095303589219,7.39680912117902));
#510=CARTESIAN_POINT('',(-7.72571019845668,2.64903389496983,7.54890277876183));
#511=B_SPLINE_CURVE_WITH_KNOTS('',3,(#501,#502,#503,#504,#505,#506,#507,#508,#509,#510),
.UNSPECIFIED.,.F.,.F.,(4,2,2,2,4),(0.,0.610695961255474,1.22136336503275,1.83202183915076,
2.4427087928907),.UNSPECIFIED.);
#512=EDGE_CURVE('E1195',#498,#279,#511,.T.);
#513=ORIENTED_EDGE('',*,*,#512,.T.);
#514=ORIENTED_EDGE('',*,*,#280,.F.);
#515=CARTESIAN_POINT('',(-7.72571019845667,1.48032074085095,7.8620585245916));
#516=CARTESIAN_POINT('',(-7.59161169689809,1.39438201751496,7.73692784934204));
#517=CARTESIAN_POINT('',(-7.45784401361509,1.30843324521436,7.61144793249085));
#518=CARTESIAN_POINT('',(-7.19111395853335,1.13651920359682,7.35966153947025));
#519=CARTESIAN_POINT('',(-7.05815154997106,1.05055393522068,7.2333551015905));
#520=CARTESIAN_POINT('',(-6.79316145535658,0.878601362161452,6.97977428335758));
#521=CARTESIAN_POINT('',(-6.66113378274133,0.792614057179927,6.85249988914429));
#522=CARTESIAN_POINT('',(-6.39820451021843,0.620616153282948,6.59679464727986));
#523=CARTESIAN_POINT('',(-6.26730296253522,0.534605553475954,6.46836374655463));
#524=CARTESIAN_POINT('',(-6.13706529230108,0.448586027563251,6.33926529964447));
#525=B_SPLINE_CURVE_WITH_KNOTS('',3,(#515,#516,#517,#518,#519,#520,#521,#522,#523,#524),
.UNSPECIFIED.,.F.,.F.,(4,2,2,2,4),(0.,0.607643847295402,1.21525974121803,1.8228843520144,
2.43053699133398),.UNSPECIFIED.);
#526=CARTESIAN_POINT('',(-6.137368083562,0.448786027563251,6.33956547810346));
#527=VERTEX_POINT('',#526);
#528=EDGE_CURVE('E1074',#273,#527,#525,.T.);
#529=ORIENTED_EDGE('',*,*,#528,.T.);
#530=CARTESIAN_POINT('',(-6.1373642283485,0.448986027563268,6.33954731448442));
#531=CARTESIAN_POINT('',(-6.14024748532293,0.299324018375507,6.35311927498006));
#532=CARTESIAN_POINT('',(-6.14168911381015,0.149662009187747,6.35990525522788));
#533=CARTESIAN_POINT('',(-6.14168911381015,-0.149662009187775,6.35990525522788));
#534=CARTESIAN_POINT('',(-6.14024748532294,-0.299324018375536,6.35311927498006));
#535=CARTESIAN_POINT('',(-6.1373642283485,-0.448986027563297,6.33954731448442));
#536=B_SPLINE_CURVE_WITH_KNOTS('',3,(#530,#531,#532,#533,#534,#535),.UNSPECIFIED.,.F.,.F.,(4,2,
4),(0.,0.449468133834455,0.89893626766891),.UNSPECIFIED.);
#537=CARTESIAN_POINT('',(-6.137368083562,-0.448786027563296,6.33956547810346));
#538=VERTEX_POINT('',#537);
#539=EDGE_CURVE('E1198',#527,#538,#536,.T.);
#540=ORIENTED_EDGE('',*,*,#539,.T.);
#541=CARTESIAN_POINT('',(-6.13706529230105,-0.44858602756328,6.33926529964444));
#542=CARTESIAN_POINT('',(-6.2673029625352,-0.534605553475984,6.4683637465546));
#543=CARTESIAN_POINT('',(-6.39820451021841,-0.62061615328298,6.59679464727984));
#544=CARTESIAN_POINT('',(-6.66113378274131,-0.792614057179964,6.85249988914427));
#545=CARTESIAN_POINT('',(-6.79316145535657,-0.878601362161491,6.97977428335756));
#546=CARTESIAN_POINT('',(-7.05815154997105,-1.05055393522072,7.23335510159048));
#547=CARTESIAN_POINT('',(-7.19111395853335,-1.13651920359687,7.35966153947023));
#548=CARTESIAN_POINT('',(-7.45784401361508,-1.30843324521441,7.61144793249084));
#549=CARTESIAN_POINT('',(-7.59161169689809,-1.39438201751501,7.73692784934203));
#550=CARTESIAN_POINT('',(-7.72571019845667,-1.48032074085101,7.86205852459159));
#551=B_SPLINE_CURVE_WITH_KNOTS('',3,(#541,#542,#543,#544,#545,#546,#547,#548,#549,#550),
.UNSPECIFIED.,.F.,.F.,(4,2,2,2,4),(0.,0.607652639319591,1.21527725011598,1.82289314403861,
2.43053699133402),.UNSPECIFIED.);
#552=EDGE_CURVE('E1049',#538,#378,#551,.T.);
#553=ORIENTED_EDGE('',*,*,#552,.T.);
#554=ORIENTED_EDGE('',*,*,#379,.F.);
#555=CARTESIAN_POINT('',(-7.72571019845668,-2.64903389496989,7.54890277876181));
#556=CARTESIAN_POINT('',(-7.59094019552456,-2.66095303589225,7.396809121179));
#557=CARTESIAN_POINT('',(-7.45650423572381,-2.67270463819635,7.24440497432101));
#558=CARTESIAN_POINT('',(-7.18844645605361,-2.69580450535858,6.93886481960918));
#559=CARTESIAN_POINT('',(-7.0548245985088,-2.70715278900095,6.7857288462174));
#560=CARTESIAN_POINT('',(-6.78852653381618,-2.72937904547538,6.47859774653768));
#561=CARTESIAN_POINT('',(-6.65585034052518,-2.74025701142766,6.32460260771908));
#562=CARTESIAN_POINT('',(-6.39163850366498,-2.76144775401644,6.01558633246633));
#563=CARTESIAN_POINT('',(-6.260102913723,-2.77176050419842,5.86056514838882));
#564=CARTESIAN_POINT('',(-6.12924030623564,-2.78174277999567,5.70495359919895));
#565=B_SPLINE_CURVE_WITH_KNOTS('',3,(#555,#556,#557,#558,#559,#560,#561,#562,#563,#564),
.UNSPECIFIED.,.F.,.F.,(4,2,2,2,4),(0.,0.610686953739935,1.22134542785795,1.83201283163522,
2.4427087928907),.UNSPECIFIED.);
#566=CARTESIAN_POINT('',(-6.13736808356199,-2.78112263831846,5.71461776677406));
#567=VERTEX_POINT('',#566);
#568=EDGE_CURVE('E1085',#372,#567,#565,.T.);
#569=ORIENTED_EDGE('',*,*,#568,.T.);
#570=CARTESIAN_POINT('',(-6.13704893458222,-2.76628507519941,5.72144785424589));
#571=CARTESIAN_POINT('',(-6.14010458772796,-2.90607207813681,5.65735129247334));
#572=CARTESIAN_POINT('',(-6.14165108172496,-3.04231438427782,5.58709807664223));
#573=CARTESIAN_POINT('',(-6.14172575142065,-3.30770959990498,5.4342783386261));
#574=CARTESIAN_POINT('',(-6.14025392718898,-3.43686250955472,5.35171181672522));
#575=CARTESIAN_POINT('',(-6.13727294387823,-3.56247072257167,5.26298864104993));
#576=B_SPLINE_CURVE_WITH_KNOTS('',3,(#570,#571,#572,#573,#574,#575),.UNSPECIFIED.,.F.,.F.,(4,2,
4),(0.,0.459890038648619,0.919780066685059),.UNSPECIFIED.);
#577=CARTESIAN_POINT('',(-6.13736808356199,-3.55844283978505,5.26583173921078));
#578=VERTEX_POINT('',#577);
#579=EDGE_CURVE('E1116',#567,#578,#576,.T.);
#580=ORIENTED_EDGE('',*,*,#579,.T.);
#581=CARTESIAN_POINT('',(-6.12924030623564,-3.54976335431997,5.26153671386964));
#582=CARTESIAN_POINT('',(-6.260102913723,-3.68951804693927,5.33069758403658));
#583=CARTESIAN_POINT('',(-6.39163850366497,-3.82892670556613,5.39927707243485));
#584=CARTESIAN_POINT('',(-6.65585034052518,-4.10713802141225,5.53543348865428));
#585=CARTESIAN_POINT('',(-6.78852653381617,-4.24594070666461,5.6030104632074));
#586=CARTESIAN_POINT('',(-7.0548245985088,-4.52303716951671,5.73732751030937));
#587=CARTESIAN_POINT('',(-7.1884464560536,-4.66133095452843,5.80406759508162));
#588=CARTESIAN_POINT('',(-7.45650423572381,-4.93748642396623,5.93683260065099));
#589=CARTESIAN_POINT('',(-7.59094019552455,-5.07534808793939,6.00285748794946));
#590=CARTESIAN_POINT('',(-7.72571019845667,-5.21302462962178,6.06858203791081));
#591=B_SPLINE_CURVE_WITH_KNOTS('',3,(#581,#582,#583,#584,#585,#586,#587,#588,#589,#590),
.UNSPECIFIED.,.F.,.F.,(4,2,2,2,4),(0.,0.610695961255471,1.22136336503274,1.83202183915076,
2.44270879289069),.UNSPECIFIED.);
#592=EDGE_CURVE('E1108',#578,#242,#591,.T.);
#593=ORIENTED_EDGE('',*,*,#592,.T.);
#594=ORIENTED_EDGE('',*,*,#260,.F.);
#595=CARTESIAN_POINT('',(-7.72571019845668,-6.06858203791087,5.21302462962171));
#596=CARTESIAN_POINT('',(-7.59094019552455,-6.00285748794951,5.07534808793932));
#597=CARTESIAN_POINT('',(-7.45650423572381,-5.93683260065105,4.93748642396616));
#598=CARTESIAN_POINT('',(-7.1884464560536,-5.80406759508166,4.66133095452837));
#599=CARTESIAN_POINT('',(-7.0548245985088,-5.73732751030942,4.52303716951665));
#600=CARTESIAN_POINT('',(-6.78852653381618,-5.60301046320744,4.24594070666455));
#601=CARTESIAN_POINT('',(-6.65585034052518,-5.53543348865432,4.10713802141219));
#602=CARTESIAN_POINT('',(-6.39163850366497,-5.39927707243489,3.82892670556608));
#603=CARTESIAN_POINT('',(-6.260102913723,-5.33069758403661,3.68951804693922));
#604=CARTESIAN_POINT('',(-6.12924030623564,-5.26153671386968,3.54976335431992));
#605=B_SPLINE_CURVE_WITH_KNOTS('',3,(#595,#596,#597,#598,#599,#600,#601,#602,#603,#604),
.UNSPECIFIED.,.F.,.F.,(4,2,2,2,4),(0.,0.610686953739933,1.22134542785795,1.83201283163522,
2.44270879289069),.UNSPECIFIED.);
#606=CARTESIAN_POINT('',(-6.13736808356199,-5.26583173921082,3.558442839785));
#607=VERTEX_POINT('',#606);
#608=EDGE_CURVE('E1034',#257,#607,#605,.T.);
#609=ORIENTED_EDGE('',*,*,#608,.T.);
#610=CARTESIAN_POINT('',(-6.13727294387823,-5.26298864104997,3.56247072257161));
#611=CARTESIAN_POINT('',(-6.14025392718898,-5.35171181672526,3.43686250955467));
#612=CARTESIAN_POINT('',(-6.14172575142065,-5.43427833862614,3.30770959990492));
#613=CARTESIAN_POINT('',(-6.14165108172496,-5.58709807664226,3.04231438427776));
#614=CARTESIAN_POINT('',(-6.14010458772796,-5.65735129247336,2.90607207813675));
#615=CARTESIAN_POINT('',(-6.13704893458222,-5.72144785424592,2.76628507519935));
#616=B_SPLINE_CURVE_WITH_KNOTS('',3,(#610,#611,#612,#613,#614,#615),.UNSPECIFIED.,.F.,.F.,(4,2,
4),(0.,0.45989002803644,0.919780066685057),.UNSPECIFIED.);
#617=CARTESIAN_POINT('',(-6.13736808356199,-5.71461776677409,2.7811226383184));
#618=VERTEX_POINT('',#617);
#619=EDGE_CURVE('E1008',#607,#618,#616,.T.);
#620=ORIENTED_EDGE('',*,*,#619,.T.);
#621=CARTESIAN_POINT('',(-6.12924030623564,-5.70495359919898,2.78174277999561));
#622=CARTESIAN_POINT('',(-6.260102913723,-5.86056514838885,2.77176050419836));
#623=CARTESIAN_POINT('',(-6.39163850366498,-6.01558633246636,2.76144775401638));
#624=CARTESIAN_POINT('',(-6.65585034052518,-6.32460260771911,2.7402570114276));
#625=CARTESIAN_POINT('',(-6.78852653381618,-6.47859774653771,2.72937904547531));
#626=CARTESIAN_POINT('',(-7.0548245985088,-6.78572884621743,2.70715278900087));
#627=CARTESIAN_POINT('',(-7.18844645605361,-6.93886481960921,2.6958045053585));
#628=CARTESIAN_POINT('',(-7.45650423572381,-7.24440497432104,2.67270463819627));
#629=CARTESIAN_POINT('',(-7.59094019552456,-7.39680912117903,2.66095303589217));
#630=CARTESIAN_POINT('',(-7.72571019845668,-7.54890277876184,2.64903389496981));
#631=B_SPLINE_CURVE_WITH_KNOTS('',3,(#621,#622,#623,#624,#625,#626,#627,#628,#629,#630),
.UNSPECIFIED.,.F.,.F.,(4,2,2,2,4),(0.,0.610695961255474,1.22136336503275,1.83202183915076,
2.4427087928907),.UNSPECIFIED.);
#632=EDGE_CURVE('E1033',#618,#308,#631,.T.);
#633=ORIENTED_EDGE('',*,*,#632,.T.);
#634=ORIENTED_EDGE('',*,*,#326,.F.);
#635=CARTESIAN_POINT('',(-7.72571019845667,-7.86205852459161,1.48032074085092));
#636=CARTESIAN_POINT('',(-7.59161169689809,-7.73692784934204,1.39438201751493));
#637=CARTESIAN_POINT('',(-7.45784401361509,-7.61144793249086,1.30843324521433));
#638=CARTESIAN_POINT('',(-7.19111395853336,-7.35966153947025,1.1365192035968));
#639=CARTESIAN_POINT('',(-7.05815154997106,-7.2333551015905,1.05055393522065));
#640=CARTESIAN_POINT('',(-6.79316145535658,-6.97977428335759,0.878601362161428));
#641=CARTESIAN_POINT('',(-6.66113378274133,-6.85249988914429,0.792614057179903));
#642=CARTESIAN_POINT('',(-6.39820451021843,-6.59679464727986,0.620616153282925));
#643=CARTESIAN_POINT('',(-6.26730296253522,-6.46836374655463,0.534605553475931));
#644=CARTESIAN_POINT('',(-6.13706529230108,-6.33926529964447,0.44858602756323));
#645=B_SPLINE_CURVE_WITH_KNOTS('',3,(#635,#636,#637,#638,#639,#640,#641,#642,#643,#644),
.UNSPECIFIED.,.F.,.F.,(4,2,2,2,4),(0.,0.607643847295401,1.21525974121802,1.8228843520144,
2.43053699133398),.UNSPECIFIED.);
#646=CARTESIAN_POINT('',(-6.13736808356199,-6.33956547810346,0.448786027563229));
#647=VERTEX_POINT('',#646);
#648=EDGE_CURVE('E1196',#323,#647,#645,.T.);
#649=ORIENTED_EDGE('',*,*,#648,.T.);
#650=CARTESIAN_POINT('',(-6.1373642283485,-6.33954731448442,0.448986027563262));
#651=CARTESIAN_POINT('',(-6.14024748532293,-6.35311927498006,0.299324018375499));
#652=CARTESIAN_POINT('',(-6.14168911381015,-6.35990525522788,0.149662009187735));
#653=CARTESIAN_POINT('',(-6.14168911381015,-6.35990525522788,-0.149662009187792));
#654=CARTESIAN_POINT('',(-6.14024748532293,-6.35311927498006,-0.299324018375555));
#655=CARTESIAN_POINT('',(-6.1373642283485,-6.33954731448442,-0.448986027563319));
#656=B_SPLINE_CURVE_WITH_KNOTS('',3,(#650,#651,#652,#653,#654,#655),.UNSPECIFIED.,.F.,.F.,(4,2,
4),(0.,0.449468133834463,0.898936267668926),.UNSPECIFIED.);
#657=CARTESIAN_POINT('',(-6.13736808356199,-6.33956547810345,-0.448786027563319));
#658=VERTEX_POINT('',#657);
#659=EDGE_CURVE('E1003',#647,#658,#656,.T.);
#660=ORIENTED_EDGE('',*,*,#659,.T.);
#661=CARTESIAN_POINT('',(-6.13706529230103,-6.33926529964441,-0.448586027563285));
#662=CARTESIAN_POINT('',(-6.26730296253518,-6.46836374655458,-0.534605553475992));
#663=CARTESIAN_POINT('',(-6.39820451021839,-6.59679464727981,-0.62061615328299));
#664=CARTESIAN_POINT('',(-6.66113378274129,-6.85249988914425,-0.792614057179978));
#665=CARTESIAN_POINT('',(-6.79316145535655,-6.97977428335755,-0.878601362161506));
#666=CARTESIAN_POINT('',(-7.05815154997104,-7.23335510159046,-1.05055393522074));
#667=CARTESIAN_POINT('',(-7.19111395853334,-7.35966153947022,-1.13651920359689));
#668=CARTESIAN_POINT('',(-7.45784401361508,-7.61144793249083,-1.30843324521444));
#669=CARTESIAN_POINT('',(-7.59161169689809,-7.73692784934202,-1.39438201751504));
#670=CARTESIAN_POINT('',(-7.72571019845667,-7.86205852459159,-1.48032074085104));
#671=B_SPLINE_CURVE_WITH_KNOTS('',3,(#661,#662,#663,#664,#665,#666,#667,#668,#669,#670),
.UNSPECIFIED.,.F.,.F.,(4,2,2,2,4),(0.,0.607652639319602,1.215277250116,1.82289314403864,
2.43053699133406),.UNSPECIFIED.);
#672=EDGE_CURVE('E993',#658,#81,#671,.T.);
#673=ORIENTED_EDGE('',*,*,#672,.T.);
#674=ORIENTED_EDGE('',*,*,#82,.F.);
#675=CARTESIAN_POINT('',(-7.72571019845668,-7.5489027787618,-2.64903389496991));
#676=CARTESIAN_POINT('',(-7.59094019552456,-7.39680912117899,-2.66095303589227));
#677=CARTESIAN_POINT('',(-7.45650423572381,-7.24440497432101,-2.67270463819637));
#678=CARTESIAN_POINT('',(-7.18844645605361,-6.93886481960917,-2.6958045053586));
#679=CARTESIAN_POINT('',(-7.0548245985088,-6.78572884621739,-2.70715278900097));
#680=CARTESIAN_POINT('',(-6.78852653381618,-6.47859774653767,-2.7293790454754));
#681=CARTESIAN_POINT('',(-6.65585034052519,-6.32460260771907,-2.74025701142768));
#682=CARTESIAN_POINT('',(-6.39163850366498,-6.01558633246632,-2.76144775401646));
#683=CARTESIAN_POINT('',(-6.260102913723,-5.86056514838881,-2.77176050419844));
#684=CARTESIAN_POINT('',(-6.12924030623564,-5.70495359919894,-2.78174277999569));
#685=B_SPLINE_CURVE_WITH_KNOTS('',3,(#675,#676,#677,#678,#679,#680,#681,#682,#683,#684),
.UNSPECIFIED.,.F.,.F.,(4,2,2,2,4),(0.,0.610686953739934,1.22134542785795,1.83201283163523,
2.4427087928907),.UNSPECIFIED.);
#686=CARTESIAN_POINT('',(-6.13736808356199,-5.71461776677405,-2.78112263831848));
#687=VERTEX_POINT('',#686);
#688=EDGE_CURVE('E378',#75,#687,#685,.T.);
#689=ORIENTED_EDGE('',*,*,#688,.T.);
#690=CARTESIAN_POINT('',(-6.13704893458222,-5.72144785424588,-2.76628507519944));
#691=CARTESIAN_POINT('',(-6.14010458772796,-5.65735129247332,-2.90607207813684));
#692=CARTESIAN_POINT('',(-6.14165108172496,-5.58709807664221,-3.04231438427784));
#693=CARTESIAN_POINT('',(-6.14172575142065,-5.43427833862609,-3.307709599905));
#694=CARTESIAN_POINT('',(-6.14025392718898,-5.35171181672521,-3.43686250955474));
#695=CARTESIAN_POINT('',(-6.13727294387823,-5.26298864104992,-3.56247072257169));
#696=B_SPLINE_CURVE_WITH_KNOTS('',3,(#690,#691,#692,#693,#694,#695),.UNSPECIFIED.,.F.,.F.,(4,2,
4),(0.,0.459890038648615,0.919780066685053),.UNSPECIFIED.);
#697=CARTESIAN_POINT('',(-6.13736808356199,-5.26583173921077,-3.55844283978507));
#698=VERTEX_POINT('',#697);
#699=EDGE_CURVE('E960',#687,#698,#696,.T.);
#700=ORIENTED_EDGE('',*,*,#699,.T.);
#701=CARTESIAN_POINT('',(-6.12924030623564,-5.26153671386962,-3.54976335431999));
#702=CARTESIAN_POINT('',(-6.260102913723,-5.33069758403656,-3.68951804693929));
#703=CARTESIAN_POINT('',(-6.39163850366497,-5.39927707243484,-3.82892670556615));
#704=CARTESIAN_POINT('',(-6.65585034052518,-5.53543348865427,-4.10713802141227));
#705=CARTESIAN_POINT('',(-6.78852653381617,-5.60301046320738,-4.24594070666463));
#706=CARTESIAN_POINT('',(-7.0548245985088,-5.73732751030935,-4.52303716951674));
#707=CARTESIAN_POINT('',(-7.1884464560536,-5.8040675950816,-4.66133095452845));
#708=CARTESIAN_POINT('',(-7.45650423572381,-5.93683260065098,-4.93748642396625));
#709=CARTESIAN_POINT('',(-7.59094019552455,-6.00285748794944,-5.07534808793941));
#710=CARTESIAN_POINT('',(-7.72571019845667,-6.0685820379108,-5.2130246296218));
#711=B_SPLINE_CURVE_WITH_KNOTS('',3,(#701,#702,#703,#704,#705,#706,#707,#708,#709,#710),
.UNSPECIFIED.,.F.,.F.,(4,2,2,2,4),(0.,0.610695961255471,1.22136336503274,1.83202183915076,
2.44270879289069),.UNSPECIFIED.);
#712=EDGE_CURVE('E730',#698,#407,#711,.T.);
#713=ORIENTED_EDGE('',*,*,#712,.T.);
#714=ORIENTED_EDGE('',*,*,#425,.F.);
#715=CARTESIAN_POINT('',(-7.72571019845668,-5.21302462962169,-6.06858203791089));
#716=CARTESIAN_POINT('',(-7.59094019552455,-5.0753480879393,-6.00285748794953));
#717=CARTESIAN_POINT('',(-7.45650423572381,-4.93748642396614,-5.93683260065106));
#718=CARTESIAN_POINT('',(-7.18844645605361,-4.66133095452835,-5.80406759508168));
#719=CARTESIAN_POINT('',(-7.0548245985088,-4.52303716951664,-5.73732751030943));
#720=CARTESIAN_POINT('',(-6.78852653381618,-4.24594070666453,-5.60301046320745));
#721=CARTESIAN_POINT('',(-6.65585034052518,-4.10713802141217,-5.53543348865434));
#722=CARTESIAN_POINT('',(-6.39163850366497,-3.82892670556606,-5.3992770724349));
#723=CARTESIAN_POINT('',(-6.260102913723,-3.6895180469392,-5.33069758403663));
#724=CARTESIAN_POINT('',(-6.12924030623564,-3.5497633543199,-5.26153671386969));
#725=B_SPLINE_CURVE_WITH_KNOTS('',3,(#715,#716,#717,#718,#719,#720,#721,#722,#723,#724),
.UNSPECIFIED.,.F.,.F.,(4,2,2,2,4),(0.,0.610686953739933,1.22134542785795,1.83201283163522,
2.44270879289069),.UNSPECIFIED.);
#726=CARTESIAN_POINT('',(-6.13736808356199,-3.55844283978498,-5.26583173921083));
#727=VERTEX_POINT('',#726);
#728=EDGE_CURVE('E731',#422,#727,#725,.T.);
#729=ORIENTED_EDGE('',*,*,#728,.T.);
#730=CARTESIAN_POINT('',(-6.13727294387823,-3.56247072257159,-5.26298864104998));
#731=CARTESIAN_POINT('',(-6.14025392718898,-3.43686250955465,-5.35171181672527));
#732=CARTESIAN_POINT('',(-6.14172575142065,-3.3077095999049,-5.43427833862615));
#733=CARTESIAN_POINT('',(-6.14165108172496,-3.04231438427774,-5.58709807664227));
#734=CARTESIAN_POINT('',(-6.14010458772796,-2.90607207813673,-5.65735129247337));
#735=CARTESIAN_POINT('',(-6.13704893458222,-2.76628507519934,-5.72144785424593));
#736=B_SPLINE_CURVE_WITH_KNOTS('',3,(#730,#731,#732,#733,#734,#735),.UNSPECIFIED.,.F.,.F.,(4,2,
4),(0.,0.459890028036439,0.919780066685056),.UNSPECIFIED.);
#737=CARTESIAN_POINT('',(-6.13736808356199,-2.78112263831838,-5.7146177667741));
#738=VERTEX_POINT('',#737);
#739=EDGE_CURVE('E954',#727,#738,#736,.T.);
#740=ORIENTED_EDGE('',*,*,#739,.T.);
#741=CARTESIAN_POINT('',(-6.12924030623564,-2.78174277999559,-5.70495359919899));
#742=CARTESIAN_POINT('',(-6.260102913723,-2.77176050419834,-5.86056514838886));
#743=CARTESIAN_POINT('',(-6.39163850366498,-2.76144775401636,-6.01558633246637));
#744=CARTESIAN_POINT('',(-6.65585034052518,-2.74025701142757,-6.32460260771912));
#745=CARTESIAN_POINT('',(-6.78852653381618,-2.72937904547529,-6.47859774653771));
#746=CARTESIAN_POINT('',(-7.0548245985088,-2.70715278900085,-6.78572884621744));
#747=CARTESIAN_POINT('',(-7.18844645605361,-2.69580450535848,-6.93886481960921));
#748=CARTESIAN_POINT('',(-7.45650423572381,-2.67270463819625,-7.24440497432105));
#749=CARTESIAN_POINT('',(-7.59094019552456,-2.66095303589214,-7.39680912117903));
#750=CARTESIAN_POINT('',(-7.72571019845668,-2.64903389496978,-7.54890277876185));
#751=B_SPLINE_CURVE_WITH_KNOTS('',3,(#741,#742,#743,#744,#745,#746,#747,#748,#749,#750),
.UNSPECIFIED.,.F.,.F.,(4,2,2,2,4),(0.,0.610695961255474,1.22136336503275,1.83202183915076,
2.4427087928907),.UNSPECIFIED.);
#752=EDGE_CURVE('E961',#738,#110,#751,.T.);
#753=ORIENTED_EDGE('',*,*,#752,.T.);
#754=ORIENTED_EDGE('',*,*,#128,.F.);
#755=CARTESIAN_POINT('',(-7.72571019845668,-1.4803207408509,-7.86205852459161));
#756=CARTESIAN_POINT('',(-7.59161169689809,-1.3943820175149,-7.73692784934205));
#757=CARTESIAN_POINT('',(-7.45784401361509,-1.30843324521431,-7.61144793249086));
#758=CARTESIAN_POINT('',(-7.19111395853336,-1.13651920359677,-7.35966153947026));
#759=CARTESIAN_POINT('',(-7.05815154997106,-1.05055393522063,-7.2333551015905));
#760=CARTESIAN_POINT('',(-6.79316145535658,-0.878601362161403,-6.97977428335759));
#761=CARTESIAN_POINT('',(-6.66113378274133,-0.792614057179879,-6.8524998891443));
#762=CARTESIAN_POINT('',(-6.39820451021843,-0.620616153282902,-6.59679464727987));
#763=CARTESIAN_POINT('',(-6.26730296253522,-0.534605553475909,-6.46836374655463));
#764=CARTESIAN_POINT('',(-6.13706529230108,-0.448586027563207,-6.33926529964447));
#765=B_SPLINE_CURVE_WITH_KNOTS('',3,(#755,#756,#757,#758,#759,#760,#761,#762,#763,#764),
.UNSPECIFIED.,.F.,.F.,(4,2,2,2,4),(0.,0.607643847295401,1.21525974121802,1.8228843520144,
2.43053699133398),.UNSPECIFIED.);
#766=CARTESIAN_POINT('',(-6.137368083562,-0.448786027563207,-6.33956547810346));
#767=VERTEX_POINT('',#766);
#768=EDGE_CURVE('E872',#125,#767,#765,.T.);
#769=ORIENTED_EDGE('',*,*,#768,.T.);
#770=CARTESIAN_POINT('',(-6.1373642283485,-0.448986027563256,-6.33954731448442));
#771=CARTESIAN_POINT('',(-6.14024748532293,-0.29932401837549,-6.35311927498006));
#772=CARTESIAN_POINT('',(-6.14168911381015,-0.149662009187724,-6.35990525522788));
#773=CARTESIAN_POINT('',(-6.14168911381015,0.149662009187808,-6.35990525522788));
#774=CARTESIAN_POINT('',(-6.14024748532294,0.299324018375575,-6.35311927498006));
#775=CARTESIAN_POINT('',(-6.1373642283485,0.448986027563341,-6.33954731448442));
#776=B_SPLINE_CURVE_WITH_KNOTS('',3,(#770,#771,#772,#773,#774,#775),.UNSPECIFIED.,.F.,.F.,(4,2,
4),(0.,0.449468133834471,0.898936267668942),.UNSPECIFIED.);
#777=CARTESIAN_POINT('',(-6.137368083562,0.448786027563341,-6.33956547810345));
#778=VERTEX_POINT('',#777);
#779=EDGE_CURVE('E828',#767,#778,#776,.T.);
#780=ORIENTED_EDGE('',*,*,#779,.T.);
#781=CARTESIAN_POINT('',(-6.137065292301,0.448586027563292,-6.33926529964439));
#782=CARTESIAN_POINT('',(-6.26730296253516,0.534605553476,-6.46836374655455));
#783=CARTESIAN_POINT('',(-6.39820451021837,0.620616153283,-6.59679464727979));
#784=CARTESIAN_POINT('',(-6.66113378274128,0.792614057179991,-6.85249988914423));
#785=CARTESIAN_POINT('',(-6.79316145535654,0.878601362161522,-6.97977428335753));
#786=CARTESIAN_POINT('',(-7.05815154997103,1.05055393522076,-7.23335510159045));
#787=CARTESIAN_POINT('',(-7.19111395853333,1.13651920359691,-7.35966153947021));
#788=CARTESIAN_POINT('',(-7.45784401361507,1.30843324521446,-7.61144793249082));
#789=CARTESIAN_POINT('',(-7.59161169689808,1.39438201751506,-7.73692784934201));
#790=CARTESIAN_POINT('',(-7.72571019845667,1.48032074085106,-7.86205852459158));
#791=B_SPLINE_CURVE_WITH_KNOTS('',3,(#781,#782,#783,#784,#785,#786,#787,#788,#789,#790),
.UNSPECIFIED.,.F.,.F.,(4,2,2,2,4),(0.,0.60765263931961,1.21527725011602,1.82289314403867,
2.4305369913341),.UNSPECIFIED.);
#792=EDGE_CURVE('E826',#778,#147,#791,.T.);
#793=ORIENTED_EDGE('',*,*,#792,.T.);
#794=ORIENTED_EDGE('',*,*,#148,.F.);
#795=CARTESIAN_POINT('',(-7.72571019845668,2.64903389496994,-7.54890277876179));
#796=CARTESIAN_POINT('',(-7.59094019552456,2.6609530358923,-7.39680912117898));
#797=CARTESIAN_POINT('',(-7.45650423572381,2.6727046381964,-7.24440497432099));
#798=CARTESIAN_POINT('',(-7.18844645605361,2.69580450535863,-6.93886481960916));
#799=CARTESIAN_POINT('',(-7.0548245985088,2.70715278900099,-6.78572884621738));
#800=CARTESIAN_POINT('',(-6.78852653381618,2.72937904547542,-6.47859774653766));
#801=CARTESIAN_POINT('',(-6.65585034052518,2.74025701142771,-6.32460260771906));
#802=CARTESIAN_POINT('',(-6.39163850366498,2.76144775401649,-6.01558633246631));
#803=CARTESIAN_POINT('',(-6.260102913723,2.77176050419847,-5.8605651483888));
#804=CARTESIAN_POINT('',(-6.12924030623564,2.78174277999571,-5.70495359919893));
#805=B_SPLINE_CURVE_WITH_KNOTS('',3,(#795,#796,#797,#798,#799,#800,#801,#802,#803,#804),
.UNSPECIFIED.,.F.,.F.,(4,2,2,2,4),(0.,0.610686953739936,1.22134542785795,1.83201283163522,
2.4427087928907),.UNSPECIFIED.);
#806=CARTESIAN_POINT('',(-6.137368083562,2.7811226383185,-5.71461776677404));
#807=VERTEX_POINT('',#806);
#808=EDGE_CURVE('E824',#141,#807,#805,.T.);
#809=ORIENTED_EDGE('',*,*,#808,.T.);
#810=CARTESIAN_POINT('',(-6.13704893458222,2.76628507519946,-5.72144785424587));
#811=CARTESIAN_POINT('',(-6.14010458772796,2.90607207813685,-5.65735129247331));
#812=CARTESIAN_POINT('',(-6.14165108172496,3.04231438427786,-5.5870980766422));
#813=CARTESIAN_POINT('',(-6.14172575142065,3.30770959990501,-5.43427833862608));
#814=CARTESIAN_POINT('',(-6.14025392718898,3.43686250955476,-5.3517118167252));
#815=CARTESIAN_POINT('',(-6.13727294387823,3.5624707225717,-5.2629886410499));
#816=B_SPLINE_CURVE_WITH_KNOTS('',3,(#810,#811,#812,#813,#814,#815),.UNSPECIFIED.,.F.,.F.,(4,2,
4),(0.,0.459890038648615,0.919780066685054),.UNSPECIFIED.);
#817=CARTESIAN_POINT('',(-6.137368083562,3.55844283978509,-5.26583173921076));
#818=VERTEX_POINT('',#817);
#819=EDGE_CURVE('E832',#807,#818,#816,.T.);
#820=ORIENTED_EDGE('',*,*,#819,.T.);
#821=CARTESIAN_POINT('',(-6.12924030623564,3.54976335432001,-5.26153671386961));
#822=CARTESIAN_POINT('',(-6.260102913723,3.68951804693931,-5.33069758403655));
#823=CARTESIAN_POINT('',(-6.39163850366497,3.82892670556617,-5.39927707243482));
#824=CARTESIAN_POINT('',(-6.65585034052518,4.10713802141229,-5.53543348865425));
#825=CARTESIAN_POINT('',(-6.78852653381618,4.24594070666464,-5.60301046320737));
#826=CARTESIAN_POINT('',(-7.0548245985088,4.52303716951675,-5.73732751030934));
#827=CARTESIAN_POINT('',(-7.1884464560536,4.66133095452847,-5.80406759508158));
#828=CARTESIAN_POINT('',(-7.45650423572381,4.93748642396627,-5.93683260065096));
#829=CARTESIAN_POINT('',(-7.59094019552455,5.07534808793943,-6.00285748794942));
#830=CARTESIAN_POINT('',(-7.72571019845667,5.21302462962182,-6.06858203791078));
#831=B_SPLINE_CURVE_WITH_KNOTS('',3,(#821,#822,#823,#824,#825,#826,#827,#828,#829,#830),
.UNSPECIFIED.,.F.,.F.,(4,2,2,2,4),(0.,0.610695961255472,1.22136336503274,1.83202183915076,
2.44270879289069),.UNSPECIFIED.);
#832=EDGE_CURVE('E912',#818,#176,#831,.T.);
#833=ORIENTED_EDGE('',*,*,#832,.T.);
#834=ORIENTED_EDGE('',*,*,#194,.F.);
#835=CARTESIAN_POINT('',(-7.72571019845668,6.06858203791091,-5.21302462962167));
#836=CARTESIAN_POINT('',(-7.59094019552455,6.00285748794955,-5.07534808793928));
#837=CARTESIAN_POINT('',(-7.45650423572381,5.93683260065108,-4.93748642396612));
#838=CARTESIAN_POINT('',(-7.18844645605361,5.8040675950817,-4.66133095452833));
#839=CARTESIAN_POINT('',(-7.0548245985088,5.73732751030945,-4.52303716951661));
#840=CARTESIAN_POINT('',(-6.78852653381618,5.60301046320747,-4.24594070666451));
#841=CARTESIAN_POINT('',(-6.65585034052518,5.53543348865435,-4.10713802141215));
#842=CARTESIAN_POINT('',(-6.39163850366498,5.39927707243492,-3.82892670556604));
#843=CARTESIAN_POINT('',(-6.260102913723,5.33069758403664,-3.68951804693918));
#844=CARTESIAN_POINT('',(-6.12924030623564,5.2615367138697,-3.54976335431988));
#845=B_SPLINE_CURVE_WITH_KNOTS('',3,(#835,#836,#837,#838,#839,#840,#841,#842,#843,#844),
.UNSPECIFIED.,.F.,.F.,(4,2,2,2,4),(0.,0.610686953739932,1.22134542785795,1.83201283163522,
2.44270879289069),.UNSPECIFIED.);
#846=CARTESIAN_POINT('',(-6.13736808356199,5.26583173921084,-3.55844283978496));
#847=VERTEX_POINT('',#846);
#848=EDGE_CURVE('E913',#191,#847,#845,.T.);
#849=ORIENTED_EDGE('',*,*,#848,.T.);
#850=CARTESIAN_POINT('',(-6.13727294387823,5.26298864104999,-3.56247072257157));
#851=CARTESIAN_POINT('',(-6.14025392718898,5.35171181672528,-3.43686250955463));
#852=CARTESIAN_POINT('',(-6.14172575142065,5.43427833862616,-3.30770959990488));
#853=CARTESIAN_POINT('',(-6.14165108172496,5.58709807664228,-3.04231438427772));
#854=CARTESIAN_POINT('',(-6.14010458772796,5.65735129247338,-2.90607207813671));
#855=CARTESIAN_POINT('',(-6.13704893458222,5.72144785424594,-2.76628507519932));
#856=B_SPLINE_CURVE_WITH_KNOTS('',3,(#850,#851,#852,#853,#854,#855),.UNSPECIFIED.,.F.,.F.,(4,2,
4),(0.,0.459890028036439,0.919780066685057),.UNSPECIFIED.);
#857=CARTESIAN_POINT('',(-6.13736808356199,5.71461776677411,-2.78112263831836));
#858=VERTEX_POINT('',#857);
#859=EDGE_CURVE('E881',#847,#858,#856,.T.);
#860=ORIENTED_EDGE('',*,*,#859,.T.);
#861=CARTESIAN_POINT('',(-6.12924030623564,5.704953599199,-2.78174277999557));
#862=CARTESIAN_POINT('',(-6.260102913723,5.86056514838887,-2.77176050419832));
#863=CARTESIAN_POINT('',(-6.39163850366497,6.01558633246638,-2.76144775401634));
#864=CARTESIAN_POINT('',(-6.65585034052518,6.32460260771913,-2.74025701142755));
#865=CARTESIAN_POINT('',(-6.78852653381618,6.47859774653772,-2.72937904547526));
#866=CARTESIAN_POINT('',(-7.0548245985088,6.78572884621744,-2.70715278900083));
#867=CARTESIAN_POINT('',(-7.18844645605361,6.93886481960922,-2.69580450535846));
#868=CARTESIAN_POINT('',(-7.45650423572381,7.24440497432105,-2.67270463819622));
#869=CARTESIAN_POINT('',(-7.59094019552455,7.39680912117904,-2.66095303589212));
#870=CARTESIAN_POINT('',(-7.72571019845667,7.54890277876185,-2.64903389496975));
#871=B_SPLINE_CURVE_WITH_KNOTS('',3,(#861,#862,#863,#864,#865,#866,#867,#868,#869,#870),
.UNSPECIFIED.,.F.,.F.,(4,2,2,2,4),(0.,0.610695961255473,1.22136336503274,1.83202183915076,
2.44270879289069),.UNSPECIFIED.);
#872=EDGE_CURVE('E836',#858,#209,#871,.T.);
#873=ORIENTED_EDGE('',*,*,#872,.T.);
#874=ORIENTED_EDGE('',*,*,#227,.F.);
#875=CARTESIAN_POINT('',(-7.72571019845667,7.8620585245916,-1.48032074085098));
#876=CARTESIAN_POINT('',(-7.59161169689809,7.73692784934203,-1.39438201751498));
#877=CARTESIAN_POINT('',(-7.45784401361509,7.61144793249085,-1.30843324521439));
#878=CARTESIAN_POINT('',(-7.19111395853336,7.35966153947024,-1.13651920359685));
#879=CARTESIAN_POINT('',(-7.05815154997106,7.23335510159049,-1.0505539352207));
#880=CARTESIAN_POINT('',(-6.79316145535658,6.97977428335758,-0.878601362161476));
#881=CARTESIAN_POINT('',(-6.66113378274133,6.85249988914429,-0.792614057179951));
#882=CARTESIAN_POINT('',(-6.39820451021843,6.59679464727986,-0.62061615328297));
#883=CARTESIAN_POINT('',(-6.26730296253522,6.46836374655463,-0.534605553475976));
#884=CARTESIAN_POINT('',(-6.13706529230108,6.33926529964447,-0.448586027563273));
#885=B_SPLINE_CURVE_WITH_KNOTS('',3,(#875,#876,#877,#878,#879,#880,#881,#882,#883,#884),
.UNSPECIFIED.,.F.,.F.,(4,2,2,2,4),(0.,0.607643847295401,1.21525974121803,1.8228843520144,
2.43053699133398),.UNSPECIFIED.);
#886=CARTESIAN_POINT('',(-6.13736808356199,6.33956547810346,-0.448786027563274));
#887=VERTEX_POINT('',#886);
#888=EDGE_CURVE('E686',#224,#887,#885,.T.);
#889=ORIENTED_EDGE('',*,*,#888,.T.);
#890=CARTESIAN_POINT('',(-6.1373642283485,6.33954731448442,-0.448986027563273));
#891=CARTESIAN_POINT('',(-6.14024748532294,6.35311927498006,-0.299324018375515));
#892=CARTESIAN_POINT('',(-6.14168911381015,6.35990525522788,-0.149662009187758));
#893=CARTESIAN_POINT('',(-6.14168911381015,6.35990525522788,0.149662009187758));
#894=CARTESIAN_POINT('',(-6.14024748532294,6.35311927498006,0.299324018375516));
#895=CARTESIAN_POINT('',(-6.1373642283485,6.33954731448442,0.448986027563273));
#896=B_SPLINE_CURVE_WITH_KNOTS('',3,(#890,#891,#892,#893,#894,#895),.UNSPECIFIED.,.F.,.F.,(4,2,
4),(0.,0.449468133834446,0.898936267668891),.UNSPECIFIED.);
#897=CARTESIAN_POINT('',(-6.13736808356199,6.33956547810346,0.448786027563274));
#898=VERTEX_POINT('',#897);
#899=EDGE_CURVE('E753',#887,#898,#896,.T.);
#900=ORIENTED_EDGE('',*,*,#899,.T.);
#901=CARTESIAN_POINT('',(-6.13706529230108,6.33926529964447,0.448586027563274));
#902=CARTESIAN_POINT('',(-6.26730296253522,6.46836374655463,0.534605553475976));
#903=CARTESIAN_POINT('',(-6.39820451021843,6.59679464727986,0.620616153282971));
#904=CARTESIAN_POINT('',(-6.66113378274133,6.85249988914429,0.792614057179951));
#905=CARTESIAN_POINT('',(-6.79316145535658,6.97977428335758,0.878601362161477));
#906=CARTESIAN_POINT('',(-7.05815154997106,7.23335510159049,1.0505539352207));
#907=CARTESIAN_POINT('',(-7.19111395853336,7.35966153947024,1.13651920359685));
#908=CARTESIAN_POINT('',(-7.45784401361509,7.61144793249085,1.30843324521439));
#909=CARTESIAN_POINT('',(-7.59161169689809,7.73692784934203,1.39438201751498));
#910=CARTESIAN_POINT('',(-7.72571019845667,7.8620585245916,1.48032074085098));
#911=B_SPLINE_CURVE_WITH_KNOTS('',3,(#901,#902,#903,#904,#905,#906,#907,#908,#909,#910),
.UNSPECIFIED.,.F.,.F.,(4,2,2,2,4),(0.,0.607652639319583,1.21527725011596,1.82289314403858,
2.43053699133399),.UNSPECIFIED.);
#912=EDGE_CURVE('E1170',#898,#345,#911,.T.);
#913=ORIENTED_EDGE('',*,*,#912,.T.);
#914=ORIENTED_EDGE('',*,*,#346,.F.);
#915=EDGE_LOOP('',(#449,#460,#473,#474,#489,#500,#513,#514,#529,#540,#553,#554,#569,#580,#593,
#594,#609,#620,#633,#634,#649,#660,#673,#674,#689,#700,#713,#714,#729,#740,#753,#754,#769,#780,
#793,#794,#809,#820,#833,#834,#849,#860,#873,#874,#889,#900,#913,#914));
#916=FACE_BOUND('',#915,.T.);
#917=CARTESIAN_POINT('',(-4.45838712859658,0.,0.));
#918=DIRECTION('',(-1.,0.,0.));
#919=DIRECTION('',(0.,0.,1.));
#920=AXIS2_PLACEMENT_3D('',#917,#918,#919);
#921=CIRCLE('',#920,4.6167950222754);
#922=CARTESIAN_POINT('',(-4.45838712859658,0.,4.6167950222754));
#923=VERTEX_POINT('',#922);
#924=EDGE_CURVE('E760',#923,#923,#921,.T.);
#925=ORIENTED_EDGE('',*,*,#924,.T.);
#926=EDGE_LOOP('',(#925));
#927=FACE_BOUND('',#926,.T.);
#928=ADVANCED_FACE('F368',(#916,#927),#434,.T.);
#929=CARTESIAN_POINT('',(-4.88999100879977,0.,0.));
#930=DIRECTION('',(1.,0.,0.));
#931=DIRECTION('',(0.,0.,-1.));
#932=AXIS2_PLACEMENT_3D('',#929,#930,#931);
#933=CONICAL_SURFACE('',#932,4.2,0.767944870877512);
#934=ORIENTED_EDGE('',*,*,#924,.F.);
#935=EDGE_LOOP('',(#934));
#936=FACE_BOUND('',#935,.T.);
#937=CARTESIAN_POINT('',(-4.88999100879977,0.,0.));
#938=DIRECTION('',(-1.,0.,0.));
#939=DIRECTION('',(0.,0.,1.));
#940=AXIS2_PLACEMENT_3D('',#937,#938,#939);
#941=CIRCLE('',#940,4.2);
#942=CARTESIAN_POINT('',(-4.88999100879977,0.,4.2));
#943=VERTEX_POINT('',#942);
#944=EDGE_CURVE('E750',#943,#943,#941,.T.);
#945=ORIENTED_EDGE('',*,*,#944,.T.);
#946=EDGE_LOOP('',(#945));
#947=FACE_BOUND('',#946,.T.);
#948=ADVANCED_FACE('F428',(#936,#947),#933,.F.);
#949=CARTESIAN_POINT('',(-8.15711407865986,0.,0.));
#950=DIRECTION('',(-1.,0.,0.));
#951=DIRECTION('',(0.,0.,1.));
#952=AXIS2_PLACEMENT_3D('',#949,#950,#951);
#953=CONICAL_SURFACE('',#952,7.5832049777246,0.802851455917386);
#954=ORIENTED_EDGE('',*,*,#44,.T.);
#955=CARTESIAN_POINT('',(-8.15731407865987,5.70257098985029,4.99888216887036));
#956=CARTESIAN_POINT('',(-7.9851994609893,5.61914013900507,4.82363044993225));
#957=CARTESIAN_POINT('',(-7.8136147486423,5.53522976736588,4.64808155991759));
#958=CARTESIAN_POINT('',(-7.47186674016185,5.36616851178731,4.296238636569));
#959=CARTESIAN_POINT('',(-7.30170330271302,5.28101775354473,4.11994468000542));
#960=CARTESIAN_POINT('',(-6.96311722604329,5.10917380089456,3.76641784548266));
#961=CARTESIAN_POINT('',(-6.79469466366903,5.02248053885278,3.58918492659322));
#962=CARTESIAN_POINT('',(-6.54375368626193,4.89096592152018,3.32245116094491));
#963=CARTESIAN_POINT('',(-6.46038465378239,4.84687965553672,3.23338796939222));
#964=CARTESIAN_POINT('',(-6.2943001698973,4.7581463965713,3.05492995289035));
#965=CARTESIAN_POINT('',(-6.21158472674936,4.71349939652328,2.96553512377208));
#966=CARTESIAN_POINT('',(-6.12924030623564,4.66853731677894,2.87595570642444));
#967=B_SPLINE_CURVE_WITH_KNOTS('',3,(#955,#956,#957,#958,#959,#960,#961,#962,#963,#964,#965,
#966),.UNSPECIFIED.,.F.,.F.,(4,2,2,2,2,4),(0.,0.77825548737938,1.55643265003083,
2.33464401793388,2.72378916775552,3.11293922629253),.UNSPECIFIED.);
#968=CARTESIAN_POINT('',(-6.56952908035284,4.90441073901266,3.34977632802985));
#969=VERTEX_POINT('',#968);
#970=EDGE_CURVE('E11',#32,#969,#967,.T.);
#971=ORIENTED_EDGE('',*,*,#970,.T.);
#972=CARTESIAN_POINT('',(-6.56379285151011,4.74473660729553,3.56247072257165));
#973=CARTESIAN_POINT('',(-6.56773061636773,4.83726936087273,3.4460569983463));
#974=CARTESIAN_POINT('',(-6.57045043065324,4.92442674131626,3.32532673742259));
#975=CARTESIAN_POINT('',(-6.57343057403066,5.08731162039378,3.07629422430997));
#976=CARTESIAN_POINT('',(-6.57368998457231,5.16303483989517,2.94798916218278));
#977=CARTESIAN_POINT('',(-6.57174464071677,5.3007530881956,2.68788232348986));
#978=CARTESIAN_POINT('',(-6.56959457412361,5.36301603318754,2.55622182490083));
#979=CARTESIAN_POINT('',(-6.56298817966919,5.47541382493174,2.28796713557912));
#980=CARTESIAN_POINT('',(-6.55853332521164,5.52555638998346,2.15137614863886));
#981=CARTESIAN_POINT('',(-6.54899443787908,5.60122447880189,1.91295032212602));
#982=CARTESIAN_POINT('',(-6.54443067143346,5.62971719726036,1.81202371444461));
#983=CARTESIAN_POINT('',(-6.53420443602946,5.68042845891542,1.607777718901));
#984=CARTESIAN_POINT('',(-6.52853325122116,5.70259355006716,1.5044454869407));
#985=CARTESIAN_POINT('',(-6.52236279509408,5.7214478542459,1.40053514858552));
#986=B_SPLINE_CURVE_WITH_KNOTS('',3,(#972,#973,#974,#975,#976,#977,#978,#979,#980,#981,#982,
#983,#984,#985),.UNSPECIFIED.,.F.,.F.,(4,2,2,2,2,2,4),(0.,0.446127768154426,0.892422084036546,
1.3287884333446,1.76487616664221,2.07958193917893,2.39687240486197),.UNSPECIFIED.);
#987=CARTESIAN_POINT('',(-6.56952908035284,5.35319676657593,2.57245612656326));
#988=VERTEX_POINT('',#987);
#989=EDGE_CURVE('E46',#969,#988,#986,.T.);
#990=ORIENTED_EDGE('',*,*,#989,.T.);
#991=CARTESIAN_POINT('',(-6.12924030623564,4.82491936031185,2.60509406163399));
#992=CARTESIAN_POINT('',(-6.21158472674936,4.92497845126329,2.59924265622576));
#993=CARTESIAN_POINT('',(-6.2943001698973,5.02472014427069,2.59321067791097));
#994=CARTESIAN_POINT('',(-6.46038465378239,5.223635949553,2.58082692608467));
#995=CARTESIAN_POINT('',(-6.54375368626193,5.32281006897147,2.574475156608));
#996=CARTESIAN_POINT('',(-6.79469466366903,5.6195655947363,2.55500327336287));
#997=CARTESIAN_POINT('',(-6.96311722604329,5.81640043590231,2.54146538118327));
#998=CARTESIAN_POINT('',(-7.30170330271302,6.2084856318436,2.51352319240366));
#999=CARTESIAN_POINT('',(-7.47186674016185,6.40373605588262,2.49911893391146));
#1000=CARTESIAN_POINT('',(-7.81361474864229,6.79297159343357,2.46960881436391));
#1001=CARTESIAN_POINT('',(-7.98519946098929,6.98695657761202,2.45450288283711));
#1002=CARTESIAN_POINT('',(-8.15731407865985,7.18044444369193,2.43913025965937));
#1003=B_SPLINE_CURVE_WITH_KNOTS('',3,(#991,#992,#993,#994,#995,#996,#997,#998,#999,#1000,#1001,
#1002),.UNSPECIFIED.,.F.,.F.,(4,2,2,2,2,4),(0.,0.389150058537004,0.778295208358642,
1.55650657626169,2.33468373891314,3.11293922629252),.UNSPECIFIED.);
#1004=EDGE_CURVE('E643',#988,#341,#1003,.T.);
#1005=ORIENTED_EDGE('',*,*,#1004,.T.);
#1006=ORIENTED_EDGE('',*,*,#359,.T.);
#1007=CARTESIAN_POINT('',(-8.15731407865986,7.4380124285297,1.47787345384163));
#1008=CARTESIAN_POINT('',(-8.0232328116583,7.31347751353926,1.39214142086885));
#1009=CARTESIAN_POINT('',(-7.889482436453,7.18859184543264,1.30639885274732));
#1010=CARTESIAN_POINT('',(-7.62279721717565,6.93798086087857,1.13489613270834));
#1011=CARTESIAN_POINT('',(-7.48986233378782,6.81225558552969,1.04913598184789));
#1012=CARTESIAN_POINT('',(-7.22494665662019,6.55981314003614,0.877591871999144));
#1013=CARTESIAN_POINT('',(-7.09296587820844,6.43309595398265,0.791807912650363));
#1014=CARTESIAN_POINT('',(-6.83016797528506,6.17846271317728,0.620214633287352));
#1015=CARTESIAN_POINT('',(-6.69935090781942,6.05054660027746,0.534405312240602));
#1016=CARTESIAN_POINT('',(-6.56922584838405,5.92193270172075,0.448586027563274));
#1017=B_SPLINE_CURVE_WITH_KNOTS('',3,(#1007,#1008,#1009,#1010,#1011,#1012,#1013,#1014,#1015,
#1016),.UNSPECIFIED.,.F.,.F.,(4,2,2,2,4),(0.,0.606243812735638,1.21245816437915,1.8186822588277,
2.42493590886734),.UNSPECIFIED.);
#1018=CARTESIAN_POINT('',(-6.56952908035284,5.9222324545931,0.448786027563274));
#1019=VERTEX_POINT('',#1018);
#1020=EDGE_CURVE('E449',#356,#1019,#1017,.T.);
#1021=ORIENTED_EDGE('',*,*,#1020,.T.);
#1022=CARTESIAN_POINT('',(-6.56952572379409,5.92221380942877,0.448986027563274));
#1023=CARTESIAN_POINT('',(-6.57203723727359,5.93614475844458,0.299324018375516));
#1024=CARTESIAN_POINT('',(-6.57329299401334,5.94311023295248,0.149662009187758));
#1025=CARTESIAN_POINT('',(-6.57329299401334,5.94311023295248,-0.149662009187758));
#1026=CARTESIAN_POINT('',(-6.57203723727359,5.93614475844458,-0.299324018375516));
#1027=CARTESIAN_POINT('',(-6.56952572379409,5.92221380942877,-0.448986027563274));
#1028=B_SPLINE_CURVE_WITH_KNOTS('',3,(#1022,#1023,#1024,#1025,#1026,#1027),.UNSPECIFIED.,.F.,
.F.,(4,2,4),(0.,0.449487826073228,0.898975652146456),.UNSPECIFIED.);
#1029=CARTESIAN_POINT('',(-6.56952908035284,5.9222324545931,-0.448786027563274));
#1030=VERTEX_POINT('',#1029);
#1031=EDGE_CURVE('E443',#1019,#1030,#1028,.T.);
#1032=ORIENTED_EDGE('',*,*,#1031,.T.);
#1033=CARTESIAN_POINT('',(-6.56922584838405,5.92193270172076,-0.448586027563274));
#1034=CARTESIAN_POINT('',(-6.69935090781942,6.05054660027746,-0.534405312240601));
#1035=CARTESIAN_POINT('',(-6.83016797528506,6.17846271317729,-0.620214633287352));
#1036=CARTESIAN_POINT('',(-7.09296587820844,6.43309595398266,-0.791807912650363));
#1037=CARTESIAN_POINT('',(-7.22494665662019,6.55981314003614,-0.877591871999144));
#1038=CARTESIAN_POINT('',(-7.48986233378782,6.81225558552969,-1.04913598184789));
#1039=CARTESIAN_POINT('',(-7.62279721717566,6.93798086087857,-1.13489613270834));
#1040=CARTESIAN_POINT('',(-7.88948243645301,7.18859184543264,-1.30639885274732));
#1041=CARTESIAN_POINT('',(-8.0232328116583,7.31347751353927,-1.39214142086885));
#1042=CARTESIAN_POINT('',(-8.15731407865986,7.4380124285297,-1.47787345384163));
#1043=B_SPLINE_CURVE_WITH_KNOTS('',3,(#1033,#1034,#1035,#1036,#1037,#1038,#1039,#1040,#1041,
#1042),.UNSPECIFIED.,.F.,.F.,(4,2,2,2,4),(0.,0.606253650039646,1.2124777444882,1.8186920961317,
2.42493590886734),.UNSPECIFIED.);
#1044=EDGE_CURVE('E435',#1030,#213,#1043,.T.);
#1045=ORIENTED_EDGE('',*,*,#1044,.T.);
#1046=ORIENTED_EDGE('',*,*,#214,.T.);
#1047=CARTESIAN_POINT('',(-8.15731407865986,7.18044444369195,-2.43913025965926));
#1048=CARTESIAN_POINT('',(-7.9851994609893,6.98695657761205,-2.45450288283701));
#1049=CARTESIAN_POINT('',(-7.81361474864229,6.7929715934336,-2.46960881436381));
#1050=CARTESIAN_POINT('',(-7.47186674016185,6.40373605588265,-2.49911893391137));
#1051=CARTESIAN_POINT('',(-7.30170330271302,6.20848563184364,-2.51352319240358));
#1052=CARTESIAN_POINT('',(-6.96311722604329,5.81640043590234,-2.54146538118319));
#1053=CARTESIAN_POINT('',(-6.79469466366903,5.61956559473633,-2.55500327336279));
#1054=CARTESIAN_POINT('',(-6.54375368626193,5.32281006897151,-2.57447515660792));
#1055=CARTESIAN_POINT('',(-6.46038465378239,5.22363594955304,-2.5808269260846));
#1056=CARTESIAN_POINT('',(-6.2943001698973,5.02472014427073,-2.5932106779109));
#1057=CARTESIAN_POINT('',(-6.21158472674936,4.92497845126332,-2.59924265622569));
#1058=CARTESIAN_POINT('',(-6.12924030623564,4.82491936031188,-2.60509406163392));
#1059=B_SPLINE_CURVE_WITH_KNOTS('',3,(#1047,#1048,#1049,#1050,#1051,#1052,#1053,#1054,#1055,
#1056,#1057,#1058),.UNSPECIFIED.,.F.,.F.,(4,2,2,2,2,4),(0.,0.778255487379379,1.55643265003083,
2.33464401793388,2.72378916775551,3.11293922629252),.UNSPECIFIED.);
#1060=CARTESIAN_POINT('',(-6.56952908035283,5.35319676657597,-2.57245612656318));
#1061=VERTEX_POINT('',#1060);
#1062=EDGE_CURVE('E567',#207,#1061,#1059,.T.);
#1063=ORIENTED_EDGE('',*,*,#1062,.T.);
#1064=CARTESIAN_POINT('',(-6.52236279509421,5.72144785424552,-1.40053514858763));
#1065=CARTESIAN_POINT('',(-6.53097439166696,5.69518401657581,-1.5454149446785));
#1066=CARTESIAN_POINT('',(-6.53860392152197,5.66243927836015,-1.68919788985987));
#1067=CARTESIAN_POINT('',(-6.55172209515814,5.58414970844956,-1.97343924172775));
#1068=CARTESIAN_POINT('',(-6.55720927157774,5.53859614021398,-2.11389530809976));
#1069=CARTESIAN_POINT('',(-6.56575706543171,5.43604653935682,-2.38706197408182));
#1070=CARTESIAN_POINT('',(-6.56886919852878,5.37932914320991,-2.51987553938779));
#1071=CARTESIAN_POINT('',(-6.57277730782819,5.25427764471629,-2.77984843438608));
#1072=CARTESIAN_POINT('',(-6.57357495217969,5.18595194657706,-2.90701177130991));
#1073=CARTESIAN_POINT('',(-6.57292906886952,5.05709974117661,-3.12303517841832));
#1074=CARTESIAN_POINT('',(-6.5720061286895,4.9990414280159,-3.21337991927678));
#1075=CARTESIAN_POINT('',(-6.56887281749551,4.87654675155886,-3.3907506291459));
#1076=CARTESIAN_POINT('',(-6.56665157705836,4.81206039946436,-3.47774188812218));
#1077=CARTESIAN_POINT('',(-6.56379285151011,4.74473660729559,-3.56247072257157));
#1078=B_SPLINE_CURVE_WITH_KNOTS('',3,(#1064,#1065,#1066,#1067,#1068,#1069,#1070,#1071,#1072,
#1073,#1074,#1075,#1076,#1077),.UNSPECIFIED.,.F.,.F.,(4,2,2,2,2,2,4),(0.,0.442361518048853,
0.88502549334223,1.31779125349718,1.75024502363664,2.07219778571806,2.39688535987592),.UNSPECIFIED.);
#1079=CARTESIAN_POINT('',(-6.56952908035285,4.90441073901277,-3.34977632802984));
#1080=VERTEX_POINT('',#1079);
#1081=EDGE_CURVE('E560',#1061,#1080,#1078,.T.);
#1082=ORIENTED_EDGE('',*,*,#1081,.T.);
#1083=CARTESIAN_POINT('',(-6.12924030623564,4.66853731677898,-2.87595570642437));
#1084=CARTESIAN_POINT('',(-6.21158472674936,4.71349939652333,-2.96553512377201));
#1085=CARTESIAN_POINT('',(-6.2943001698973,4.75814639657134,-3.05492995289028));
#1086=CARTESIAN_POINT('',(-6.46038465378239,4.84687965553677,-3.23338796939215));
#1087=CARTESIAN_POINT('',(-6.54375368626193,4.89096592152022,-3.32245116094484));
#1088=CARTESIAN_POINT('',(-6.79469466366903,5.02248053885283,-3.58918492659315));
#1089=CARTESIAN_POINT('',(-6.96311722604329,5.10917380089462,-3.76641784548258));
#1090=CARTESIAN_POINT('',(-7.30170330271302,5.28101775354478,-4.11994468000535));
#1091=CARTESIAN_POINT('',(-7.47186674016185,5.36616851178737,-4.29623863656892));
#1092=CARTESIAN_POINT('',(-7.81361474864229,5.53522976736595,-4.64808155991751));
#1093=CARTESIAN_POINT('',(-7.98519946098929,5.61914013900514,-4.82363044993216));
#1094=CARTESIAN_POINT('',(-8.15731407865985,5.70257098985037,-4.99888216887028));
#1095=B_SPLINE_CURVE_WITH_KNOTS('',3,(#1083,#1084,#1085,#1086,#1087,#1088,#1089,#1090,#1091,
#1092,#1093,#1094),.UNSPECIFIED.,.F.,.F.,(4,2,2,2,2,4),(0.,0.389150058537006,0.778295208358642,
1.55650657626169,2.33468373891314,3.11293922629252),.UNSPECIFIED.);
#1096=EDGE_CURVE('E574',#1080,#180,#1095,.T.);
#1097=ORIENTED_EDGE('',*,*,#1096,.T.);
#1098=ORIENTED_EDGE('',*,*,#181,.T.);
#1099=CARTESIAN_POINT('',(-8.15731407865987,4.99888216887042,-5.70257098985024));
#1100=CARTESIAN_POINT('',(-7.9851994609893,4.8236304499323,-5.61914013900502));
#1101=CARTESIAN_POINT('',(-7.8136147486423,4.64808155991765,-5.53522976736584));
#1102=CARTESIAN_POINT('',(-7.47186674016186,4.29623863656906,-5.36616851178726));
#1103=CARTESIAN_POINT('',(-7.30170330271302,4.11994468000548,-5.28101775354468));
#1104=CARTESIAN_POINT('',(-6.9631172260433,3.76641784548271,-5.10917380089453));
#1105=CARTESIAN_POINT('',(-6.79469466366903,3.58918492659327,-5.02248053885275));
#1106=CARTESIAN_POINT('',(-6.54375368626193,3.32245116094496,-4.89096592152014));
#1107=CARTESIAN_POINT('',(-6.46038465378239,3.23338796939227,-4.84687965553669));
#1108=CARTESIAN_POINT('',(-6.2943001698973,3.0549299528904,-4.75814639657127));
#1109=CARTESIAN_POINT('',(-6.21158472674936,2.96553512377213,-4.71349939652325));
#1110=CARTESIAN_POINT('',(-6.12924030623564,2.87595570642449,-4.66853731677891));
#1111=B_SPLINE_CURVE_WITH_KNOTS('',3,(#1099,#1100,#1101,#1102,#1103,#1104,#1105,#1106,#1107,
#1108,#1109,#1110),.UNSPECIFIED.,.F.,.F.,(4,2,2,2,2,4),(0.,0.778255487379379,1.55643265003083,
2.33464401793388,2.72378916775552,3.11293922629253),.UNSPECIFIED.);
#1112=CARTESIAN_POINT('',(-6.56952908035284,3.34977632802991,-4.90441073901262));
#1113=VERTEX_POINT('',#1112);
#1114=EDGE_CURVE('E588',#174,#1113,#1111,.T.);
#1115=ORIENTED_EDGE('',*,*,#1114,.T.);
#1116=CARTESIAN_POINT('',(-6.56379285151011,3.5624707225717,-4.74473660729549));
#1117=CARTESIAN_POINT('',(-6.56773061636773,3.44605699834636,-4.83726936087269));
#1118=CARTESIAN_POINT('',(-6.57045043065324,3.32532673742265,-4.92442674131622));
#1119=CARTESIAN_POINT('',(-6.57343057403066,3.07629422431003,-5.08731162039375));
#1120=CARTESIAN_POINT('',(-6.57368998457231,2.94798916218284,-5.16303483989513));
#1121=CARTESIAN_POINT('',(-6.57174464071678,2.68788232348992,-5.30075308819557));
#1122=CARTESIAN_POINT('',(-6.56959457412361,2.5562218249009,-5.36301603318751));
#1123=CARTESIAN_POINT('',(-6.56298817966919,2.28796713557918,-5.47541382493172));
#1124=CARTESIAN_POINT('',(-6.55853332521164,2.15137614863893,-5.52555638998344));
#1125=CARTESIAN_POINT('',(-6.54899443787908,1.9129503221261,-5.60122447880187));
#1126=CARTESIAN_POINT('',(-6.54443067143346,1.8120237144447,-5.62971719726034));
#1127=CARTESIAN_POINT('',(-6.53420443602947,1.60777771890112,-5.68042845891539));
#1128=CARTESIAN_POINT('',(-6.52853325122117,1.50444548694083,-5.70259355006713));
#1129=CARTESIAN_POINT('',(-6.52236279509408,1.40053514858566,-5.72144785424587));
#1130=B_SPLINE_CURVE_WITH_KNOTS('',3,(#1116,#1117,#1118,#1119,#1120,#1121,#1122,#1123,#1124,
#1125,#1126,#1127,#1128,#1129),.UNSPECIFIED.,.F.,.F.,(4,2,2,2,2,2,4),(0.,0.446127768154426,
0.892422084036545,1.3287884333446,1.76487616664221,2.0795819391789,2.39687240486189),.UNSPECIFIED.);
#1131=CARTESIAN_POINT('',(-6.56952908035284,2.57245612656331,-5.3531967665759));
#1132=VERTEX_POINT('',#1131);
#1133=EDGE_CURVE('E581',#1113,#1132,#1130,.T.);
#1134=ORIENTED_EDGE('',*,*,#1133,.T.);
#1135=CARTESIAN_POINT('',(-6.12924030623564,2.60509406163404,-4.82491936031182));
#1136=CARTESIAN_POINT('',(-6.21158472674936,2.59924265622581,-4.92497845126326));
#1137=CARTESIAN_POINT('',(-6.2943001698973,2.59321067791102,-5.02472014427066));
#1138=CARTESIAN_POINT('',(-6.46038465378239,2.58082692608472,-5.22363594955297));
#1139=CARTESIAN_POINT('',(-6.54375368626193,2.57447515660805,-5.32281006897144));
#1140=CARTESIAN_POINT('',(-6.79469466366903,2.55500327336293,-5.61956559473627));
#1141=CARTESIAN_POINT('',(-6.96311722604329,2.54146538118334,-5.81640043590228));
#1142=CARTESIAN_POINT('',(-7.30170330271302,2.51352319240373,-6.20848563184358));
#1143=CARTESIAN_POINT('',(-7.47186674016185,2.49911893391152,-6.40373605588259));
#1144=CARTESIAN_POINT('',(-7.81361474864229,2.46960881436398,-6.79297159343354));
#1145=CARTESIAN_POINT('',(-7.98519946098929,2.45450288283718,-6.98695657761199));
#1146=CARTESIAN_POINT('',(-8.15731407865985,2.43913025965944,-7.18044444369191));
#1147=B_SPLINE_CURVE_WITH_KNOTS('',3,(#1135,#1136,#1137,#1138,#1139,#1140,#1141,#1142,#1143,
#1144,#1145,#1146),.UNSPECIFIED.,.F.,.F.,(4,2,2,2,2,4),(0.,0.389150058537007,0.778295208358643,
1.55650657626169,2.33468373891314,3.11293922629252),.UNSPECIFIED.);
#1148=EDGE_CURVE('E595',#1132,#143,#1147,.T.);
#1149=ORIENTED_EDGE('',*,*,#1148,.T.);
#1150=ORIENTED_EDGE('',*,*,#161,.T.);
#1151=CARTESIAN_POINT('',(-8.15731407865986,1.47787345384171,-7.43801242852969));
#1152=CARTESIAN_POINT('',(-8.02323281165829,1.39214142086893,-7.31347751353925));
#1153=CARTESIAN_POINT('',(-7.88948243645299,1.30639885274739,-7.18859184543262));
#1154=CARTESIAN_POINT('',(-7.62279721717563,1.1348961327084,-6.93798086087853));
#1155=CARTESIAN_POINT('',(-7.48986233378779,1.04913598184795,-6.81225558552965));
#1156=CARTESIAN_POINT('',(-7.22494665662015,0.877591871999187,-6.55981314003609));
#1157=CARTESIAN_POINT('',(-7.0929658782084,0.791807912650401,-6.4330959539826));
#1158=CARTESIAN_POINT('',(-6.830167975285,0.620214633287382,-6.17846271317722));
#1159=CARTESIAN_POINT('',(-6.69935090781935,0.534405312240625,-6.05054660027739));
#1160=CARTESIAN_POINT('',(-6.56922584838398,0.448586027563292,-5.92193270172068));
#1161=B_SPLINE_CURVE_WITH_KNOTS('',3,(#1151,#1152,#1153,#1154,#1155,#1156,#1157,#1158,#1159,
#1160),.UNSPECIFIED.,.F.,.F.,(4,2,2,2,4),(0.,0.606243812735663,1.2124581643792,1.81868225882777,
2.42493590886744),.UNSPECIFIED.);
#1162=CARTESIAN_POINT('',(-6.56952908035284,0.448786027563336,-5.92223245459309));
#1163=VERTEX_POINT('',#1162);
#1164=EDGE_CURVE('E553',#158,#1163,#1161,.T.);
#1165=ORIENTED_EDGE('',*,*,#1164,.T.);
#1166=CARTESIAN_POINT('',(-6.56952572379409,0.44898602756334,-5.92221380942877));
#1167=CARTESIAN_POINT('',(-6.57203723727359,0.299324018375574,-5.93614475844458));
#1168=CARTESIAN_POINT('',(-6.57329299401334,0.149662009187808,-5.94311023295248));
#1169=CARTESIAN_POINT('',(-6.57329299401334,-0.149662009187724,-5.94311023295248));
#1170=CARTESIAN_POINT('',(-6.57203723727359,-0.29932401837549,-5.93614475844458));
#1171=CARTESIAN_POINT('',(-6.56952572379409,-0.448986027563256,-5.92221380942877));
#1172=B_SPLINE_CURVE_WITH_KNOTS('',3,(#1166,#1167,#1168,#1169,#1170,#1171),.UNSPECIFIED.,.F.,
.F.,(4,2,4),(0.,0.449487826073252,0.898975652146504),.UNSPECIFIED.);
#1173=CARTESIAN_POINT('',(-6.56952908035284,-0.448786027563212,-5.9222324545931));
#1174=VERTEX_POINT('',#1173);
#1175=EDGE_CURVE('E539',#1163,#1174,#1172,.T.);
#1176=ORIENTED_EDGE('',*,*,#1175,.T.);
#1177=CARTESIAN_POINT('',(-6.56922584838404,-0.448586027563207,-5.92193270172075));
#1178=CARTESIAN_POINT('',(-6.69935090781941,-0.534405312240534,-6.05054660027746));
#1179=CARTESIAN_POINT('',(-6.83016797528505,-0.620214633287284,-6.17846271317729));
#1180=CARTESIAN_POINT('',(-7.09296587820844,-0.791807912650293,-6.43309595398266));
#1181=CARTESIAN_POINT('',(-7.22494665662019,-0.877591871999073,-6.55981314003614));
#1182=CARTESIAN_POINT('',(-7.48986233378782,-1.04913598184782,-6.8122555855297));
#1183=CARTESIAN_POINT('',(-7.62279721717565,-1.13489613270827,-6.93798086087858));
#1184=CARTESIAN_POINT('',(-7.889482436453,-1.30639885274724,-7.18859184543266));
#1185=CARTESIAN_POINT('',(-8.0232328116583,-1.39214142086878,-7.31347751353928));
#1186=CARTESIAN_POINT('',(-8.15731407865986,-1.47787345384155,-7.43801242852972));
#1187=B_SPLINE_CURVE_WITH_KNOTS('',3,(#1177,#1178,#1179,#1180,#1181,#1182,#1183,#1184,#1185,
#1186),.UNSPECIFIED.,.F.,.F.,(4,2,2,2,4),(0.,0.606253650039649,1.2124777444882,1.81869209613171,
2.42493590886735),.UNSPECIFIED.);
#1188=EDGE_CURVE('E546',#1174,#114,#1187,.T.);
#1189=ORIENTED_EDGE('',*,*,#1188,.T.);
#1190=ORIENTED_EDGE('',*,*,#115,.T.);
#1191=CARTESIAN_POINT('',(-8.15731407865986,-2.43913025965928,-7.18044444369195));
#1192=CARTESIAN_POINT('',(-7.9851994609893,-2.45450288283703,-6.98695657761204));
#1193=CARTESIAN_POINT('',(-7.81361474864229,-2.46960881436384,-6.79297159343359));
#1194=CARTESIAN_POINT('',(-7.47186674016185,-2.49911893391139,-6.40373605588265));
#1195=CARTESIAN_POINT('',(-7.30170330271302,-2.5135231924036,-6.20848563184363));
#1196=CARTESIAN_POINT('',(-6.96311722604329,-2.54146538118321,-5.81640043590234));
#1197=CARTESIAN_POINT('',(-6.79469466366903,-2.55500327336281,-5.61956559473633));
#1198=CARTESIAN_POINT('',(-6.54375368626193,-2.57447515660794,-5.3228100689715));
#1199=CARTESIAN_POINT('',(-6.46038465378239,-2.58082692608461,-5.22363594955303));
#1200=CARTESIAN_POINT('',(-6.2943001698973,-2.59321067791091,-5.02472014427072));
#1201=CARTESIAN_POINT('',(-6.21158472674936,-2.5992426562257,-4.92497845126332));
#1202=CARTESIAN_POINT('',(-6.12924030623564,-2.60509406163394,-4.82491936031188));
#1203=B_SPLINE_CURVE_WITH_KNOTS('',3,(#1191,#1192,#1193,#1194,#1195,#1196,#1197,#1198,#1199,
#1200,#1201,#1202),.UNSPECIFIED.,.F.,.F.,(4,2,2,2,2,4),(0.,0.778255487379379,1.55643265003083,
2.33464401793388,2.72378916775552,3.11293922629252),.UNSPECIFIED.);
#1204=CARTESIAN_POINT('',(-6.56952908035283,-2.5724561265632,-5.35319676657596));
#1205=VERTEX_POINT('',#1204);
#1206=EDGE_CURVE('E616',#108,#1205,#1203,.T.);
#1207=ORIENTED_EDGE('',*,*,#1206,.T.);
#1208=CARTESIAN_POINT('',(-6.52236279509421,-1.40053514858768,-5.72144785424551));
#1209=CARTESIAN_POINT('',(-6.53097439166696,-1.54541494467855,-5.6951840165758));
#1210=CARTESIAN_POINT('',(-6.53860392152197,-1.68919788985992,-5.66243927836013));
#1211=CARTESIAN_POINT('',(-6.55172209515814,-1.9734392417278,-5.58414970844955));
#1212=CARTESIAN_POINT('',(-6.55720927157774,-2.11389530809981,-5.53859614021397));
#1213=CARTESIAN_POINT('',(-6.56575706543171,-2.38706197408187,-5.4360465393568));
#1214=CARTESIAN_POINT('',(-6.56886919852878,-2.51987553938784,-5.37932914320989));
#1215=CARTESIAN_POINT('',(-6.57277730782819,-2.77984843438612,-5.25427764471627));
#1216=CARTESIAN_POINT('',(-6.57357495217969,-2.90701177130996,-5.18595194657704));
#1217=CARTESIAN_POINT('',(-6.57292906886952,-3.12303517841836,-5.05709974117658));
#1218=CARTESIAN_POINT('',(-6.57200612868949,-3.21337991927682,-4.99904142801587));
#1219=CARTESIAN_POINT('',(-6.56887281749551,-3.39075062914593,-4.87654675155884));
#1220=CARTESIAN_POINT('',(-6.56665157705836,-3.4777418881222,-4.81206039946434));
#1221=CARTESIAN_POINT('',(-6.56379285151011,-3.56247072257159,-4.74473660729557));
#1222=B_SPLINE_CURVE_WITH_KNOTS('',3,(#1208,#1209,#1210,#1211,#1212,#1213,#1214,#1215,#1216,
#1217,#1218,#1219,#1220,#1221),.UNSPECIFIED.,.F.,.F.,(4,2,2,2,2,2,4),(0.,0.442361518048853,
0.88502549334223,1.31779125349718,1.75024502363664,2.07219778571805,2.39688535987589),.UNSPECIFIED.);
#1223=CARTESIAN_POINT('',(-6.56952908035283,-3.3497763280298,-4.90441073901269));
#1224=VERTEX_POINT('',#1223);
#1225=EDGE_CURVE('E609',#1205,#1224,#1222,.T.);
#1226=ORIENTED_EDGE('',*,*,#1225,.T.);
#1227=CARTESIAN_POINT('',(-6.12924030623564,-2.87595570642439,-4.66853731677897));
#1228=CARTESIAN_POINT('',(-6.21158472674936,-2.96553512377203,-4.71349939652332));
#1229=CARTESIAN_POINT('',(-6.2943001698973,-3.0549299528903,-4.75814639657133));
#1230=CARTESIAN_POINT('',(-6.46038465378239,-3.23338796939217,-4.84687965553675));
#1231=CARTESIAN_POINT('',(-6.54375368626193,-3.32245116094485,-4.89096592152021));
#1232=CARTESIAN_POINT('',(-6.79469466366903,-3.58918492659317,-5.02248053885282));
#1233=CARTESIAN_POINT('',(-6.96311722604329,-3.7664178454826,-5.1091738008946));
#1234=CARTESIAN_POINT('',(-7.30170330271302,-4.11994468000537,-5.28101775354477));
#1235=CARTESIAN_POINT('',(-7.47186674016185,-4.29623863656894,-5.36616851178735));
#1236=CARTESIAN_POINT('',(-7.81361474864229,-4.64808155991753,-5.53522976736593));
#1237=CARTESIAN_POINT('',(-7.98519946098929,-4.82363044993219,-5.61914013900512));
#1238=CARTESIAN_POINT('',(-8.15731407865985,-4.9988821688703,-5.70257098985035));
#1239=B_SPLINE_CURVE_WITH_KNOTS('',3,(#1227,#1228,#1229,#1230,#1231,#1232,#1233,#1234,#1235,
#1236,#1237,#1238),.UNSPECIFIED.,.F.,.F.,(4,2,2,2,2,4),(0.,0.389150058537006,0.778295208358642,
1.55650657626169,2.33468373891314,3.11293922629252),.UNSPECIFIED.);
#1240=EDGE_CURVE('E602',#1224,#411,#1239,.T.);
#1241=ORIENTED_EDGE('',*,*,#1240,.T.);
#1242=ORIENTED_EDGE('',*,*,#412,.T.);
#1243=CARTESIAN_POINT('',(-8.15731407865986,-5.70257098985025,-4.9988821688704));
#1244=CARTESIAN_POINT('',(-7.9851994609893,-5.61914013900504,-4.82363044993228));
#1245=CARTESIAN_POINT('',(-7.81361474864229,-5.53522976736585,-4.64808155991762));
#1246=CARTESIAN_POINT('',(-7.47186674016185,-5.36616851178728,-4.29623863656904));
#1247=CARTESIAN_POINT('',(-7.30170330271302,-5.2810177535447,-4.11994468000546));
#1248=CARTESIAN_POINT('',(-6.96311722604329,-5.10917380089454,-3.76641784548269));
#1249=CARTESIAN_POINT('',(-6.79469466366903,-5.02248053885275,-3.58918492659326));
#1250=CARTESIAN_POINT('',(-6.54375368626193,-4.89096592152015,-3.32245116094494));
#1251=CARTESIAN_POINT('',(-6.46038465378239,-4.8468796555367,-3.23338796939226));
#1252=CARTESIAN_POINT('',(-6.2943001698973,-4.75814639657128,-3.05492995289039));
#1253=CARTESIAN_POINT('',(-6.21158472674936,-4.71349939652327,-2.96553512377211));
#1254=CARTESIAN_POINT('',(-6.12924030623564,-4.66853731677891,-2.87595570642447));
#1255=B_SPLINE_CURVE_WITH_KNOTS('',3,(#1243,#1244,#1245,#1246,#1247,#1248,#1249,#1250,#1251,
#1252,#1253,#1254),.UNSPECIFIED.,.F.,.F.,(4,2,2,2,2,4),(0.,0.778255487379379,1.55643265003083,
2.33464401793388,2.72378916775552,3.11293922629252),.UNSPECIFIED.);
#1256=CARTESIAN_POINT('',(-6.56952908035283,-4.90441073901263,-3.34977632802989));
#1257=VERTEX_POINT('',#1256);
#1258=EDGE_CURVE('E623',#405,#1257,#1255,.T.);
#1259=ORIENTED_EDGE('',*,*,#1258,.T.);
#1260=CARTESIAN_POINT('',(-6.56379285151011,-4.7447366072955,-3.56247072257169));
#1261=CARTESIAN_POINT('',(-6.56773061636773,-4.83726936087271,-3.44605699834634));
#1262=CARTESIAN_POINT('',(-6.57045043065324,-4.92442674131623,-3.32532673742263));
#1263=CARTESIAN_POINT('',(-6.57343057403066,-5.08731162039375,-3.07629422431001));
#1264=CARTESIAN_POINT('',(-6.57368998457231,-5.16303483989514,-2.94798916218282));
#1265=CARTESIAN_POINT('',(-6.57174464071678,-5.30075308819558,-2.6878823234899));
#1266=CARTESIAN_POINT('',(-6.56959457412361,-5.36301603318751,-2.55622182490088));
#1267=CARTESIAN_POINT('',(-6.56298817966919,-5.47541382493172,-2.28796713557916));
#1268=CARTESIAN_POINT('',(-6.55853332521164,-5.52555638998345,-2.15137614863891));
#1269=CARTESIAN_POINT('',(-6.5489944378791,-5.60122447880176,-1.91295032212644));
#1270=CARTESIAN_POINT('',(-6.5444306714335,-5.62971719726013,-1.81202371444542));
#1271=CARTESIAN_POINT('',(-6.53420443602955,-5.68042845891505,-1.6077777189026));
#1272=CARTESIAN_POINT('',(-6.52853325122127,-5.70259355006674,-1.5044454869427));
#1273=CARTESIAN_POINT('',(-6.52236279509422,-5.72144785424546,-1.40053514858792));
#1274=B_SPLINE_CURVE_WITH_KNOTS('',3,(#1260,#1261,#1262,#1263,#1264,#1265,#1266,#1267,#1268,
#1269,#1270,#1271,#1272,#1273),.UNSPECIFIED.,.F.,.F.,(4,2,2,2,2,2,4),(0.,0.446127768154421,
0.892422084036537,1.32878843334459,1.76487616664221,2.07958193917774,2.39687240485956),.UNSPECIFIED.);
#1275=CARTESIAN_POINT('',(-6.56952908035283,-5.35319676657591,-2.57245612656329));
#1276=VERTEX_POINT('',#1275);
#1277=EDGE_CURVE('E630',#1257,#1276,#1274,.T.);
#1278=ORIENTED_EDGE('',*,*,#1277,.T.);
#1279=CARTESIAN_POINT('',(-6.12924030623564,-4.82491936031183,-2.60509406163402));
#1280=CARTESIAN_POINT('',(-6.21158472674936,-4.92497845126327,-2.59924265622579));
#1281=CARTESIAN_POINT('',(-6.2943001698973,-5.02472014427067,-2.593210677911));
#1282=CARTESIAN_POINT('',(-6.46038465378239,-5.22363594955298,-2.58082692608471));
#1283=CARTESIAN_POINT('',(-6.54375368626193,-5.32281006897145,-2.57447515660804));
#1284=CARTESIAN_POINT('',(-6.79469466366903,-5.61956559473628,-2.55500327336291));
#1285=CARTESIAN_POINT('',(-6.96311722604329,-5.81640043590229,-2.54146538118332));
#1286=CARTESIAN_POINT('',(-7.30170330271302,-6.20848563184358,-2.51352319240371));
#1287=CARTESIAN_POINT('',(-7.47186674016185,-6.4037360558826,-2.4991189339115));
#1288=CARTESIAN_POINT('',(-7.81361474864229,-6.79297159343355,-2.46960881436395));
#1289=CARTESIAN_POINT('',(-7.98519946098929,-6.986956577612,-2.45450288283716));
#1290=CARTESIAN_POINT('',(-8.15731407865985,-7.18044444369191,-2.43913025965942));
#1291=B_SPLINE_CURVE_WITH_KNOTS('',3,(#1279,#1280,#1281,#1282,#1283,#1284,#1285,#1286,#1287,
#1288,#1289,#1290),.UNSPECIFIED.,.F.,.F.,(4,2,2,2,2,4),(0.,0.389150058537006,0.778295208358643,
1.55650657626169,2.33468373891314,3.11293922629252),.UNSPECIFIED.);
#1292=EDGE_CURVE('E637',#1276,#77,#1291,.T.);
#1293=ORIENTED_EDGE('',*,*,#1292,.T.);
#1294=ORIENTED_EDGE('',*,*,#95,.T.);
#1295=CARTESIAN_POINT('',(-8.15731407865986,-7.43801242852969,-1.47787345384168));
#1296=CARTESIAN_POINT('',(-8.02323281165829,-7.31347751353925,-1.3921414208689));
#1297=CARTESIAN_POINT('',(-7.889482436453,-7.18859184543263,-1.30639885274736));
#1298=CARTESIAN_POINT('',(-7.62279721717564,-6.93798086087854,-1.13489613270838));
#1299=CARTESIAN_POINT('',(-7.4898623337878,-6.81225558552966,-1.04913598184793));
#1300=CARTESIAN_POINT('',(-7.22494665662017,-6.55981314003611,-0.877591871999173));
#1301=CARTESIAN_POINT('',(-7.09296587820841,-6.43309595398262,-0.791807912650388));
#1302=CARTESIAN_POINT('',(-6.83016797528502,-6.17846271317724,-0.620214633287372));
#1303=CARTESIAN_POINT('',(-6.69935090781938,-6.05054660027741,-0.534405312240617));
#1304=CARTESIAN_POINT('',(-6.569225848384,-5.92193270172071,-0.448586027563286));
#1305=B_SPLINE_CURVE_WITH_KNOTS('',3,(#1295,#1296,#1297,#1298,#1299,#1300,#1301,#1302,#1303,
#1304),.UNSPECIFIED.,.F.,.F.,(4,2,2,2,4),(0.,0.606243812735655,1.21245816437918,
1.81868225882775,2.42493590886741),.UNSPECIFIED.);
#1306=CARTESIAN_POINT('',(-6.56952908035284,-5.9222324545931,-0.448786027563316));
#1307=VERTEX_POINT('',#1306);
#1308=EDGE_CURVE('E412',#92,#1307,#1305,.T.);
#1309=ORIENTED_EDGE('',*,*,#1308,.T.);
#1310=CARTESIAN_POINT('',(-6.56952572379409,-5.92221380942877,-0.448986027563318));
#1311=CARTESIAN_POINT('',(-6.57203723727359,-5.93614475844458,-0.299324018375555));
#1312=CARTESIAN_POINT('',(-6.57329299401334,-5.94311023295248,-0.149662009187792));
#1313=CARTESIAN_POINT('',(-6.57329299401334,-5.94311023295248,0.149662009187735));
#1314=CARTESIAN_POINT('',(-6.57203723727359,-5.93614475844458,0.299324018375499));
#1315=CARTESIAN_POINT('',(-6.56952572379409,-5.92221380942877,0.448986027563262));
#1316=B_SPLINE_CURVE_WITH_KNOTS('',3,(#1310,#1311,#1312,#1313,#1314,#1315),.UNSPECIFIED.,.F.,
.F.,(4,2,4),(0.,0.449487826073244,0.898975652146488),.UNSPECIFIED.);
#1317=CARTESIAN_POINT('',(-6.56952908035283,-5.9222324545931,0.448786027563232));
#1318=VERTEX_POINT('',#1317);
#1319=EDGE_CURVE('E463',#1307,#1318,#1316,.T.);
#1320=ORIENTED_EDGE('',*,*,#1319,.T.);
#1321=CARTESIAN_POINT('',(-6.56922584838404,-5.92193270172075,0.448586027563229));
#1322=CARTESIAN_POINT('',(-6.69935090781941,-6.05054660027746,0.534405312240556));
#1323=CARTESIAN_POINT('',(-6.83016797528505,-6.17846271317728,0.620214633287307));
#1324=CARTESIAN_POINT('',(-7.09296587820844,-6.43309595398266,0.791807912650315));
#1325=CARTESIAN_POINT('',(-7.22494665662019,-6.55981314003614,0.877591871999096));
#1326=CARTESIAN_POINT('',(-7.48986233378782,-6.81225558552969,1.04913598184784));
#1327=CARTESIAN_POINT('',(-7.62279721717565,-6.93798086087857,1.13489613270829));
#1328=CARTESIAN_POINT('',(-7.889482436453,-7.18859184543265,1.30639885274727));
#1329=CARTESIAN_POINT('',(-8.0232328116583,-7.31347751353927,1.3921414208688));
#1330=CARTESIAN_POINT('',(-8.15731407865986,-7.43801242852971,1.47787345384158));
#1331=B_SPLINE_CURVE_WITH_KNOTS('',3,(#1321,#1322,#1323,#1324,#1325,#1326,#1327,#1328,#1329,
#1330),.UNSPECIFIED.,.F.,.F.,(4,2,2,2,4),(0.,0.606253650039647,1.2124777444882,1.81869209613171,
2.42493590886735),.UNSPECIFIED.);
#1332=EDGE_CURVE('E470',#1318,#312,#1331,.T.);
#1333=ORIENTED_EDGE('',*,*,#1332,.T.);
#1334=ORIENTED_EDGE('',*,*,#313,.T.);
#1335=CARTESIAN_POINT('',(-8.15731407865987,-7.18044444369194,2.43913025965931));
#1336=CARTESIAN_POINT('',(-7.9851994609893,-6.98695657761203,2.45450288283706));
#1337=CARTESIAN_POINT('',(-7.81361474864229,-6.79297159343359,2.46960881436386));
#1338=CARTESIAN_POINT('',(-7.47186674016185,-6.40373605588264,2.49911893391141));
#1339=CARTESIAN_POINT('',(-7.30170330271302,-6.20848563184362,2.51352319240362));
#1340=CARTESIAN_POINT('',(-6.96311722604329,-5.81640043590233,2.54146538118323));
#1341=CARTESIAN_POINT('',(-6.79469466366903,-5.61956559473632,2.55500327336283));
#1342=CARTESIAN_POINT('',(-6.54375368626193,-5.32281006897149,2.57447515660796));
#1343=CARTESIAN_POINT('',(-6.46038465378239,-5.22363594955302,2.58082692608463));
#1344=CARTESIAN_POINT('',(-6.2943001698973,-5.02472014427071,2.59321067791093));
#1345=CARTESIAN_POINT('',(-6.21158472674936,-4.9249784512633,2.59924265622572));
#1346=CARTESIAN_POINT('',(-6.12924030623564,-4.82491936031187,2.60509406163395));
#1347=B_SPLINE_CURVE_WITH_KNOTS('',3,(#1335,#1336,#1337,#1338,#1339,#1340,#1341,#1342,#1343,
#1344,#1345,#1346),.UNSPECIFIED.,.F.,.F.,(4,2,2,2,2,4),(0.,0.778255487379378,1.55643265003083,
2.33464401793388,2.72378916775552,3.11293922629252),.UNSPECIFIED.);
#1348=CARTESIAN_POINT('',(-6.56952908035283,-5.35319676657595,2.57245612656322));
#1349=VERTEX_POINT('',#1348);
#1350=EDGE_CURVE('E491',#306,#1349,#1347,.T.);
#1351=ORIENTED_EDGE('',*,*,#1350,.T.);
#1352=CARTESIAN_POINT('',(-6.52236279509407,-5.72144785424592,1.40053514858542));
#1353=CARTESIAN_POINT('',(-6.53097439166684,-5.69518401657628,1.54541494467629));
#1354=CARTESIAN_POINT('',(-6.53860392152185,-5.66243927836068,1.68919788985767));
#1355=CARTESIAN_POINT('',(-6.55172209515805,-5.58414970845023,1.97343924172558));
#1356=CARTESIAN_POINT('',(-6.55720927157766,-5.53859614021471,2.11389530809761));
#1357=CARTESIAN_POINT('',(-6.56575706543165,-5.43604653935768,2.38706197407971));
#1358=CARTESIAN_POINT('',(-6.56886919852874,-5.37932914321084,2.51987553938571));
#1359=CARTESIAN_POINT('',(-6.57277730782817,-5.25427764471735,2.77984843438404));
#1360=CARTESIAN_POINT('',(-6.57357495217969,-5.18595194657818,2.9070117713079));
#1361=CARTESIAN_POINT('',(-6.57292906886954,-5.05709974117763,3.1230351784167));
#1362=CARTESIAN_POINT('',(-6.57200612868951,-4.99904142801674,3.21337991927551));
#1363=CARTESIAN_POINT('',(-6.56887281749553,-4.8765467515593,3.39075062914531));
#1364=CARTESIAN_POINT('',(-6.56665157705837,-4.81206039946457,3.47774188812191));
#1365=CARTESIAN_POINT('',(-6.56379285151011,-4.74473660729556,3.56247072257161));
#1366=B_SPLINE_CURVE_WITH_KNOTS('',3,(#1352,#1353,#1354,#1355,#1356,#1357,#1358,#1359,#1360,
#1361,#1362,#1363,#1364,#1365),.UNSPECIFIED.,.F.,.F.,(4,2,2,2,2,2,4),(0.,0.442361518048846,
0.885025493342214,1.31779125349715,1.75024502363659,2.07219778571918,2.39688535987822),.UNSPECIFIED.);
#1367=CARTESIAN_POINT('',(-6.56952908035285,-4.90441073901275,3.34977632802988));
#1368=VERTEX_POINT('',#1367);
#1369=EDGE_CURVE('E477',#1349,#1368,#1366,.T.);
#1370=ORIENTED_EDGE('',*,*,#1369,.T.);
#1371=CARTESIAN_POINT('',(-6.12924030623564,-4.66853731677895,2.87595570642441));
#1372=CARTESIAN_POINT('',(-6.21158472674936,-4.71349939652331,2.96553512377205));
#1373=CARTESIAN_POINT('',(-6.2943001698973,-4.75814639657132,3.05492995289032));
#1374=CARTESIAN_POINT('',(-6.46038465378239,-4.84687965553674,3.23338796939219));
#1375=CARTESIAN_POINT('',(-6.54375368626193,-4.8909659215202,3.32245116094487));
#1376=CARTESIAN_POINT('',(-6.79469466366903,-5.02248053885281,3.58918492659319));
#1377=CARTESIAN_POINT('',(-6.96311722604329,-5.10917380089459,3.76641784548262));
#1378=CARTESIAN_POINT('',(-7.30170330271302,-5.28101775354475,4.11994468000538));
#1379=CARTESIAN_POINT('',(-7.47186674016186,-5.36616851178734,4.29623863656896));
#1380=CARTESIAN_POINT('',(-7.81361474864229,-5.53522976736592,4.64808155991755));
#1381=CARTESIAN_POINT('',(-7.98519946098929,-5.61914013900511,4.82363044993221));
#1382=CARTESIAN_POINT('',(-8.15731407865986,-5.70257098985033,4.99888216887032));
#1383=B_SPLINE_CURVE_WITH_KNOTS('',3,(#1371,#1372,#1373,#1374,#1375,#1376,#1377,#1378,#1379,
#1380,#1381,#1382),.UNSPECIFIED.,.F.,.F.,(4,2,2,2,2,4),(0.,0.389150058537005,0.778295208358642,
1.55650657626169,2.33468373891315,3.11293922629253),.UNSPECIFIED.);
#1384=EDGE_CURVE('E484',#1368,#246,#1383,.T.);
#1385=ORIENTED_EDGE('',*,*,#1384,.T.);
#1386=ORIENTED_EDGE('',*,*,#247,.T.);
#1387=CARTESIAN_POINT('',(-8.15731407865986,-4.99888216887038,5.70257098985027));
#1388=CARTESIAN_POINT('',(-7.9851994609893,-4.82363044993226,5.61914013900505));
#1389=CARTESIAN_POINT('',(-7.81361474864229,-4.6480815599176,5.53522976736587));
#1390=CARTESIAN_POINT('',(-7.47186674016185,-4.29623863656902,5.36616851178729));
#1391=CARTESIAN_POINT('',(-7.30170330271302,-4.11994468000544,5.28101775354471));
#1392=CARTESIAN_POINT('',(-6.96311722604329,-3.76641784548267,5.10917380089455));
#1393=CARTESIAN_POINT('',(-6.79469466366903,-3.58918492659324,5.02248053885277));
#1394=CARTESIAN_POINT('',(-6.54375368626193,-3.32245116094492,4.89096592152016));
#1395=CARTESIAN_POINT('',(-6.46038465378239,-3.23338796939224,4.84687965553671));
#1396=CARTESIAN_POINT('',(-6.2943001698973,-3.05492995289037,4.75814639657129));
#1397=CARTESIAN_POINT('',(-6.21158472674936,-2.9655351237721,4.71349939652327));
#1398=CARTESIAN_POINT('',(-6.12924030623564,-2.87595570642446,4.66853731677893));
#1399=B_SPLINE_CURVE_WITH_KNOTS('',3,(#1387,#1388,#1389,#1390,#1391,#1392,#1393,#1394,#1395,
#1396,#1397,#1398),.UNSPECIFIED.,.F.,.F.,(4,2,2,2,2,4),(0.,0.778255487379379,1.55643265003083,
2.33464401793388,2.72378916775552,3.11293922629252),.UNSPECIFIED.);
#1400=CARTESIAN_POINT('',(-6.56952908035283,-3.34977632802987,4.90441073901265));
#1401=VERTEX_POINT('',#1400);
#1402=EDGE_CURVE('E532',#240,#1401,#1399,.T.);
#1403=ORIENTED_EDGE('',*,*,#1402,.T.);
#1404=CARTESIAN_POINT('',(-6.56379285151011,-3.56247072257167,4.74473660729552));
#1405=CARTESIAN_POINT('',(-6.56773061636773,-3.44605699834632,4.83726936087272));
#1406=CARTESIAN_POINT('',(-6.57045043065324,-3.32532673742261,4.92442674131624));
#1407=CARTESIAN_POINT('',(-6.57343057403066,-3.07629422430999,5.08731162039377));
#1408=CARTESIAN_POINT('',(-6.57368998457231,-2.9479891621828,5.16303483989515));
#1409=CARTESIAN_POINT('',(-6.57174464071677,-2.68788232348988,5.30075308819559));
#1410=CARTESIAN_POINT('',(-6.56959457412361,-2.55622182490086,5.36301603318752));
#1411=CARTESIAN_POINT('',(-6.56298817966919,-2.28796713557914,5.47541382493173));
#1412=CARTESIAN_POINT('',(-6.55853332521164,-2.15137614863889,5.52555638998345));
#1413=CARTESIAN_POINT('',(-6.5489944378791,-1.91295032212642,5.60122447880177));
#1414=CARTESIAN_POINT('',(-6.54443067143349,-1.81202371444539,5.62971719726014));
#1415=CARTESIAN_POINT('',(-6.53420443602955,-1.60777771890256,5.68042845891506));
#1416=CARTESIAN_POINT('',(-6.52853325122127,-1.50444548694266,5.70259355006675));
#1417=CARTESIAN_POINT('',(-6.52236279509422,-1.40053514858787,5.72144785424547));
#1418=B_SPLINE_CURVE_WITH_KNOTS('',3,(#1404,#1405,#1406,#1407,#1408,#1409,#1410,#1411,#1412,
#1413,#1414,#1415,#1416,#1417),.UNSPECIFIED.,.F.,.F.,(4,2,2,2,2,2,4),(0.,0.446127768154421,
0.892422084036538,1.32878843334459,1.76487616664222,2.07958193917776,2.3968724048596),.UNSPECIFIED.);
#1419=CARTESIAN_POINT('',(-6.56952908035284,-2.57245612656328,5.35319676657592));
#1420=VERTEX_POINT('',#1419);
#1421=EDGE_CURVE('E518',#1401,#1420,#1418,.T.);
#1422=ORIENTED_EDGE('',*,*,#1421,.T.);
#1423=CARTESIAN_POINT('',(-6.12924030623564,-2.60509406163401,4.82491936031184));
#1424=CARTESIAN_POINT('',(-6.21158472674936,-2.59924265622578,4.92497845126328));
#1425=CARTESIAN_POINT('',(-6.2943001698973,-2.59321067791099,5.02472014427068));
#1426=CARTESIAN_POINT('',(-6.46038465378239,-2.58082692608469,5.22363594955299));
#1427=CARTESIAN_POINT('',(-6.54375368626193,-2.57447515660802,5.32281006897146));
#1428=CARTESIAN_POINT('',(-6.79469466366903,-2.55500327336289,5.61956559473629));
#1429=CARTESIAN_POINT('',(-6.96311722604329,-2.5414653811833,5.8164004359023));
#1430=CARTESIAN_POINT('',(-7.30170330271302,-2.51352319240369,6.20848563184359));
#1431=CARTESIAN_POINT('',(-7.47186674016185,-2.49911893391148,6.40373605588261));
#1432=CARTESIAN_POINT('',(-7.81361474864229,-2.46960881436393,6.79297159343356));
#1433=CARTESIAN_POINT('',(-7.98519946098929,-2.45450288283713,6.98695657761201));
#1434=CARTESIAN_POINT('',(-8.15731407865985,-2.43913025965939,7.18044444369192));
#1435=B_SPLINE_CURVE_WITH_KNOTS('',3,(#1423,#1424,#1425,#1426,#1427,#1428,#1429,#1430,#1431,
#1432,#1433,#1434),.UNSPECIFIED.,.F.,.F.,(4,2,2,2,2,4),(0.,0.389150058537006,0.778295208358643,
1.55650657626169,2.33468373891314,3.11293922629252),.UNSPECIFIED.);
#1436=EDGE_CURVE('E525',#1420,#374,#1435,.T.);
#1437=ORIENTED_EDGE('',*,*,#1436,.T.);
#1438=ORIENTED_EDGE('',*,*,#392,.T.);
#1439=CARTESIAN_POINT('',(-8.15731407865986,-1.47787345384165,7.4380124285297));
#1440=CARTESIAN_POINT('',(-8.0232328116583,-1.39214142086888,7.31347751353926));
#1441=CARTESIAN_POINT('',(-7.889482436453,-1.30639885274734,7.18859184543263));
#1442=CARTESIAN_POINT('',(-7.62279721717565,-1.13489613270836,6.93798086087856));
#1443=CARTESIAN_POINT('',(-7.48986233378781,-1.04913598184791,6.81225558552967));
#1444=CARTESIAN_POINT('',(-7.22494665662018,-0.877591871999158,6.55981314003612));
#1445=CARTESIAN_POINT('',(-7.09296587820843,-0.791807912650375,6.43309595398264));
#1446=CARTESIAN_POINT('',(-6.83016797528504,-0.620214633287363,6.17846271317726));
#1447=CARTESIAN_POINT('',(-6.6993509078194,-0.53440531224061,6.05054660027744));
#1448=CARTESIAN_POINT('',(-6.56922584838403,-0.44858602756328,5.92193270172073));
#1449=B_SPLINE_CURVE_WITH_KNOTS('',3,(#1439,#1440,#1441,#1442,#1443,#1444,#1445,#1446,#1447,
#1448),.UNSPECIFIED.,.F.,.F.,(4,2,2,2,4),(0.,0.606243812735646,1.21245816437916,
1.81868225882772,2.42493590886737),.UNSPECIFIED.);
#1450=CARTESIAN_POINT('',(-6.56952908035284,-0.448786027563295,5.9222324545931));
#1451=VERTEX_POINT('',#1450);
#1452=EDGE_CURVE('E504',#389,#1451,#1449,.T.);
#1453=ORIENTED_EDGE('',*,*,#1452,.T.);
#1454=CARTESIAN_POINT('',(-6.56952572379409,-0.448986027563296,5.92221380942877));
#1455=CARTESIAN_POINT('',(-6.57203723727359,-0.299324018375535,5.93614475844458));
#1456=CARTESIAN_POINT('',(-6.57329299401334,-0.149662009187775,5.94311023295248));
#1457=CARTESIAN_POINT('',(-6.57329299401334,0.149662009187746,5.94311023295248));
#1458=CARTESIAN_POINT('',(-6.57203723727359,0.299324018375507,5.93614475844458));
#1459=CARTESIAN_POINT('',(-6.56952572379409,0.448986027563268,5.92221380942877));
#1460=B_SPLINE_CURVE_WITH_KNOTS('',3,(#1454,#1455,#1456,#1457,#1458,#1459),.UNSPECIFIED.,.F.,
.F.,(4,2,4),(0.,0.449487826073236,0.898975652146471),.UNSPECIFIED.);
#1461=CARTESIAN_POINT('',(-6.56952908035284,0.448786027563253,5.9222324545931));
#1462=VERTEX_POINT('',#1461);
#1463=EDGE_CURVE('E498',#1451,#1462,#1460,.T.);
#1464=ORIENTED_EDGE('',*,*,#1463,.T.);
#1465=CARTESIAN_POINT('',(-6.56922584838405,0.448586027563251,5.92193270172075));
#1466=CARTESIAN_POINT('',(-6.69935090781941,0.53440531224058,6.05054660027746));
#1467=CARTESIAN_POINT('',(-6.83016797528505,0.62021463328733,6.17846271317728));
#1468=CARTESIAN_POINT('',(-7.09296587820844,0.791807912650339,6.43309595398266));
#1469=CARTESIAN_POINT('',(-7.22494665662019,0.87759187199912,6.55981314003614));
#1470=CARTESIAN_POINT('',(-7.48986233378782,1.04913598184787,6.81225558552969));
#1471=CARTESIAN_POINT('',(-7.62279721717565,1.13489613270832,6.93798086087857));
#1472=CARTESIAN_POINT('',(-7.889482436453,1.30639885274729,7.18859184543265));
#1473=CARTESIAN_POINT('',(-8.0232328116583,1.39214142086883,7.31347751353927));
#1474=CARTESIAN_POINT('',(-8.15731407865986,1.4778734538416,7.43801242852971));
#1475=B_SPLINE_CURVE_WITH_KNOTS('',3,(#1465,#1466,#1467,#1468,#1469,#1470,#1471,#1472,#1473,
#1474),.UNSPECIFIED.,.F.,.F.,(4,2,2,2,4),(0.,0.606253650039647,1.2124777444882,1.81869209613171,
2.42493590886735),.UNSPECIFIED.);
#1476=EDGE_CURVE('E511',#1462,#275,#1475,.T.);
#1477=ORIENTED_EDGE('',*,*,#1476,.T.);
#1478=ORIENTED_EDGE('',*,*,#293,.T.);
#1479=CARTESIAN_POINT('',(-8.15731407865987,2.43913025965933,7.18044444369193));
#1480=CARTESIAN_POINT('',(-7.9851994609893,2.45450288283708,6.98695657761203));
#1481=CARTESIAN_POINT('',(-7.81361474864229,2.46960881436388,6.79297159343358));
#1482=CARTESIAN_POINT('',(-7.47186674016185,2.49911893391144,6.40373605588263));
#1483=CARTESIAN_POINT('',(-7.30170330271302,2.51352319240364,6.20848563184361));
#1484=CARTESIAN_POINT('',(-6.96311722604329,2.54146538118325,5.81640043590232));
#1485=CARTESIAN_POINT('',(-6.79469466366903,2.55500327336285,5.61956559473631));
#1486=CARTESIAN_POINT('',(-6.54375368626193,2.57447515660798,5.32281006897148));
#1487=CARTESIAN_POINT('',(-6.46038465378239,2.58082692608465,5.22363594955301));
#1488=CARTESIAN_POINT('',(-6.2943001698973,2.59321067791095,5.0247201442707));
#1489=CARTESIAN_POINT('',(-6.21158472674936,2.59924265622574,4.9249784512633));
#1490=CARTESIAN_POINT('',(-6.12924030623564,2.60509406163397,4.82491936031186));
#1491=B_SPLINE_CURVE_WITH_KNOTS('',3,(#1479,#1480,#1481,#1482,#1483,#1484,#1485,#1486,#1487,
#1488,#1489,#1490),.UNSPECIFIED.,.F.,.F.,(4,2,2,2,2,4),(0.,0.778255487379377,1.55643265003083,
2.33464401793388,2.72378916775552,3.11293922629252),.UNSPECIFIED.);
#1492=CARTESIAN_POINT('',(-6.56952908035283,2.57245612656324,5.35319676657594));
#1493=VERTEX_POINT('',#1492);
#1494=EDGE_CURVE('E413',#290,#1493,#1491,.T.);
#1495=ORIENTED_EDGE('',*,*,#1494,.T.);
#1496=CARTESIAN_POINT('',(-6.52236279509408,1.40053514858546,5.72144785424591));
#1497=CARTESIAN_POINT('',(-6.53097439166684,1.54541494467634,5.69518401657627));
#1498=CARTESIAN_POINT('',(-6.53860392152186,1.68919788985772,5.66243927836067));
#1499=CARTESIAN_POINT('',(-6.55172209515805,1.97343924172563,5.58414970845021));
#1500=CARTESIAN_POINT('',(-6.55720927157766,2.11389530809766,5.5385961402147));
#1501=CARTESIAN_POINT('',(-6.56575706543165,2.38706197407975,5.43604653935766));
#1502=CARTESIAN_POINT('',(-6.56886919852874,2.51987553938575,5.37932914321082));
#1503=CARTESIAN_POINT('',(-6.57277730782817,2.77984843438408,5.25427764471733));
#1504=CARTESIAN_POINT('',(-6.57357495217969,2.90701177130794,5.18595194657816));
#1505=CARTESIAN_POINT('',(-6.57292906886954,3.12303517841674,5.05709974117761));
#1506=CARTESIAN_POINT('',(-6.57200612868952,3.21337991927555,4.99904142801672));
#1507=CARTESIAN_POINT('',(-6.56887281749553,3.39075062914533,4.87654675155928));
#1508=CARTESIAN_POINT('',(-6.56665157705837,3.47774188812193,4.81206039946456));
#1509=CARTESIAN_POINT('',(-6.56379285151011,3.56247072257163,4.74473660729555));
#1510=B_SPLINE_CURVE_WITH_KNOTS('',3,(#1496,#1497,#1498,#1499,#1500,#1501,#1502,#1503,#1504,
#1505,#1506,#1507,#1508,#1509),.UNSPECIFIED.,.F.,.F.,(4,2,2,2,2,2,4),(0.,0.442361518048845,
0.885025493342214,1.31779125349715,1.75024502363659,2.07219778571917,2.39688535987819),.UNSPECIFIED.);
#1511=CARTESIAN_POINT('',(-6.56952908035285,3.3497763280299,4.90441073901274));
#1512=VERTEX_POINT('',#1511);
#1513=EDGE_CURVE('E455',#1493,#1512,#1510,.T.);
#1514=ORIENTED_EDGE('',*,*,#1513,.T.);
#1515=CARTESIAN_POINT('',(-6.12924030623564,2.87595570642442,4.66853731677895));
#1516=CARTESIAN_POINT('',(-6.21158472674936,2.96553512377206,4.71349939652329));
#1517=CARTESIAN_POINT('',(-6.2943001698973,3.05492995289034,4.75814639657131));
#1518=CARTESIAN_POINT('',(-6.46038465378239,3.23338796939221,4.84687965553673));
#1519=CARTESIAN_POINT('',(-6.54375368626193,3.32245116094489,4.89096592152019));
#1520=CARTESIAN_POINT('',(-6.79469466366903,3.5891849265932,5.02248053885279));
#1521=CARTESIAN_POINT('',(-6.96311722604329,3.76641784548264,5.10917380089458));
#1522=CARTESIAN_POINT('',(-7.30170330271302,4.11994468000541,5.28101775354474));
#1523=CARTESIAN_POINT('',(-7.47186674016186,4.29623863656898,5.36616851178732));
#1524=CARTESIAN_POINT('',(-7.81361474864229,4.64808155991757,5.5352297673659));
#1525=CARTESIAN_POINT('',(-7.9851994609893,4.82363044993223,5.61914013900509));
#1526=CARTESIAN_POINT('',(-8.15731407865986,4.99888216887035,5.70257098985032));
#1527=B_SPLINE_CURVE_WITH_KNOTS('',3,(#1515,#1516,#1517,#1518,#1519,#1520,#1521,#1522,#1523,
#1524,#1525,#1526),.UNSPECIFIED.,.F.,.F.,(4,2,2,2,2,4),(0.,0.389150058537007,0.778295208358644,
1.55650657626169,2.33468373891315,3.11293922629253),.UNSPECIFIED.);
#1528=EDGE_CURVE('E362',#1512,#43,#1527,.T.);
#1529=ORIENTED_EDGE('',*,*,#1528,.T.);
#1530=EDGE_LOOP('',(#954,#971,#990,#1005,#1006,#1021,#1032,#1045,#1046,#1063,#1082,#1097,#1098,
#1115,#1134,#1149,#1150,#1165,#1176,#1189,#1190,#1207,#1226,#1241,#1242,#1259,#1278,#1293,#1294,
#1309,#1320,#1333,#1334,#1351,#1370,#1385,#1386,#1403,#1422,#1437,#1438,#1453,#1464,#1477,#1478,
#1495,#1514,#1529));
#1531=FACE_BOUND('',#1530,.T.);
#1532=ORIENTED_EDGE('',*,*,#944,.F.);
#1533=EDGE_LOOP('',(#1532));
#1534=FACE_BOUND('',#1533,.T.);
#1535=ADVANCED_FACE('F423',(#1531,#1534),#953,.F.);
#1536=CARTESIAN_POINT('',(-10.386703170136,-5.69119290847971,0.));
#1537=DIRECTION('',(0.719339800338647,0.694658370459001,0.));
#1538=DIRECTION('',(-0.694658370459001,0.719339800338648,0.));
#1539=AXIS2_PLACEMENT_3D('',#1536,#1537,#1538);
#1540=CYLINDRICAL_SURFACE('',#1539,5.72);
#1541=DIRECTION('',(0.719339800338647,0.694658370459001,0.));
#1542=VECTOR('',#1541,1.);
#1543=CARTESIAN_POINT('',(-14.347900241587,-1.58925326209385,-0.448786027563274));
#1544=LINE('',#1543,#1542);
#1545=EDGE_CURVE('E670',#1030,#887,#1544,.T.);
#1546=ORIENTED_EDGE('',*,*,#1545,.F.);
#1547=ORIENTED_EDGE('',*,*,#1031,.F.);
#1548=DIRECTION('',(0.719339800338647,0.694658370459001,0.));
#1549=VECTOR('',#1548,1.);
#1550=CARTESIAN_POINT('',(-14.347900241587,-1.58925326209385,0.448786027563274));
#1551=LINE('',#1550,#1549);
#1552=EDGE_CURVE('E676',#1019,#898,#1551,.T.);
#1553=ORIENTED_EDGE('',*,*,#1552,.T.);
#1554=ORIENTED_EDGE('',*,*,#899,.F.);
#1555=EDGE_LOOP('',(#1546,#1547,#1553,#1554));
#1556=FACE_BOUND('',#1555,.T.);
#1557=ADVANCED_FACE('F427',(#1556),#1540,.T.);
#1558=CARTESIAN_POINT('',(-14.347900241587,-1.58925326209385,0.448786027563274));
#1559=DIRECTION('',(0.295063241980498,-0.305546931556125,0.90530589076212));
#1560=DIRECTION('',(0.,-0.947490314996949,-0.319784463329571));
#1561=AXIS2_PLACEMENT_3D('',#1558,#1559,#1560);
#1562=PLANE('',#1561);
#1563=ORIENTED_EDGE('',*,*,#1552,.F.);
#1564=ORIENTED_EDGE('',*,*,#1020,.F.);
#1565=ORIENTED_EDGE('',*,*,#357,.T.);
#1566=ORIENTED_EDGE('',*,*,#912,.F.);
#1567=EDGE_LOOP('',(#1563,#1564,#1565,#1566));
#1568=FACE_BOUND('',#1567,.T.);
#1569=ADVANCED_FACE('F660',(#1568),#1562,.F.);
#1570=CARTESIAN_POINT('',(-14.347900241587,-1.58925326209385,-0.448786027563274));
#1571=DIRECTION('',(0.295063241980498,-0.305546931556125,-0.90530589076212));
#1572=DIRECTION('',(0.,0.947490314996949,-0.319784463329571));
#1573=AXIS2_PLACEMENT_3D('',#1570,#1571,#1572);
#1574=PLANE('',#1573);
#1575=ORIENTED_EDGE('',*,*,#225,.T.);
#1576=ORIENTED_EDGE('',*,*,#1044,.F.);
#1577=ORIENTED_EDGE('',*,*,#1545,.T.);
#1578=ORIENTED_EDGE('',*,*,#888,.F.);
#1579=EDGE_LOOP('',(#1575,#1576,#1577,#1578));
#1580=FACE_BOUND('',#1579,.T.);
#1581=ADVANCED_FACE('F691',(#1580),#1574,.F.);
#1582=CARTESIAN_POINT('',(-11.8499128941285,-3.55209905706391,-6.15241604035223));
#1583=DIRECTION('',(0.719339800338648,0.347329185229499,0.601591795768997));
#1584=DIRECTION('',(0.641531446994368,0.,-0.767096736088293));
#1585=AXIS2_PLACEMENT_3D('',#1582,#1583,#1584);
#1586=CYLINDRICAL_SURFACE('',#1585,5.72);
#1587=DIRECTION('',(0.719339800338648,0.347329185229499,0.601591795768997));
#1588=VECTOR('',#1587,1.);
#1589=CARTESIAN_POINT('',(-15.8111099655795,-1.11246913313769,-2.82442511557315));
#1590=LINE('',#1589,#1588);
#1591=EDGE_CURVE('E346',#1512,#487,#1590,.T.);
#1592=ORIENTED_EDGE('',*,*,#1591,.F.);
#1593=ORIENTED_EDGE('',*,*,#1513,.F.);
#1594=DIRECTION('',(0.719339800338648,0.347329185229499,0.601591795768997));
#1595=VECTOR('',#1594,1.);
#1596=CARTESIAN_POINT('',(-15.8111099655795,-1.88978933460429,-2.37563908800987));
#1597=LINE('',#1596,#1595);
#1598=EDGE_CURVE('E349',#1493,#498,#1597,.T.);
#1599=ORIENTED_EDGE('',*,*,#1598,.T.);
#1600=ORIENTED_EDGE('',*,*,#499,.F.);
#1601=EDGE_LOOP('',(#1592,#1593,#1599,#1600));
#1602=FACE_BOUND('',#1601,.T.);
#1603=ADVANCED_FACE('F345',(#1602),#1586,.T.);
#1604=CARTESIAN_POINT('',(-15.8111099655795,-1.88978933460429,-2.37563908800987));
#1605=DIRECTION('',(0.295063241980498,-0.936791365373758,0.188041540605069));
#1606=DIRECTION('',(0.953806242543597,0.300422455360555,0.));
#1607=AXIS2_PLACEMENT_3D('',#1604,#1605,#1606);
#1608=PLANE('',#1607);
#1609=ORIENTED_EDGE('',*,*,#1598,.F.);
#1610=ORIENTED_EDGE('',*,*,#1494,.F.);
#1611=ORIENTED_EDGE('',*,*,#291,.T.);
#1612=ORIENTED_EDGE('',*,*,#512,.F.);
#1613=EDGE_LOOP('',(#1609,#1610,#1611,#1612));
#1614=FACE_BOUND('',#1613,.T.);
#1615=ADVANCED_FACE('F400',(#1614),#1608,.F.);
#1616=CARTESIAN_POINT('',(-15.8111099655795,-1.11246913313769,-2.82442511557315));
#1617=DIRECTION('',(0.295063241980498,0.631244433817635,-0.717264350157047));
#1618=DIRECTION('',(0.,0.750686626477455,0.660658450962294));
#1619=AXIS2_PLACEMENT_3D('',#1616,#1617,#1618);
#1620=PLANE('',#1619);
#1621=ORIENTED_EDGE('',*,*,#55,.T.);
#1622=ORIENTED_EDGE('',*,*,#1528,.F.);
#1623=ORIENTED_EDGE('',*,*,#1591,.T.);
#1624=ORIENTED_EDGE('',*,*,#488,.F.);
#1625=EDGE_LOOP('',(#1621,#1622,#1623,#1624));
#1626=FACE_BOUND('',#1625,.T.);
#1627=ADVANCED_FACE('F358',(#1626),#1620,.F.);
#1628=CARTESIAN_POINT('',(-14.2788782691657,1.52259951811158,-0.448786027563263));
#1629=DIRECTION('',(0.295063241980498,0.305546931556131,-0.905305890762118));
#1630=DIRECTION('',(0.,0.947490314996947,0.319784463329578));
#1631=AXIS2_PLACEMENT_3D('',#1628,#1629,#1630);
#1632=PLANE('',#1631);
#1633=DIRECTION('',(0.719339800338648,-0.694658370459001,0.));
#1634=VECTOR('',#1633,1.);
#1635=CARTESIAN_POINT('',(-14.2788782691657,1.52259951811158,-0.448786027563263));
#1636=LINE('',#1635,#1634);
#1637=EDGE_CURVE('E1256',#1307,#658,#1636,.T.);
#1638=ORIENTED_EDGE('',*,*,#1637,.F.);
#1639=ORIENTED_EDGE('',*,*,#1308,.F.);
#1640=ORIENTED_EDGE('',*,*,#93,.T.);
#1641=ORIENTED_EDGE('',*,*,#672,.F.);
#1642=EDGE_LOOP('',(#1638,#1639,#1640,#1641));
#1643=FACE_BOUND('',#1642,.T.);
#1644=ADVANCED_FACE('F399',(#1643),#1632,.F.);
#1645=CARTESIAN_POINT('',(-10.3176811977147,5.62453916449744,0.));
#1646=DIRECTION('',(0.719339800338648,-0.694658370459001,0.));
#1647=DIRECTION('',(0.694658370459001,0.719339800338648,0.));
#1648=AXIS2_PLACEMENT_3D('',#1645,#1646,#1647);
#1649=CYLINDRICAL_SURFACE('',#1648,5.72);
#1650=DIRECTION('',(0.719339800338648,-0.694658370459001,0.));
#1651=VECTOR('',#1650,1.);
#1652=CARTESIAN_POINT('',(-14.2788782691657,1.52259951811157,0.448786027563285));
#1653=LINE('',#1652,#1651);
#1654=EDGE_CURVE('E1261',#1318,#647,#1653,.T.);
#1655=ORIENTED_EDGE('',*,*,#1654,.F.);
#1656=ORIENTED_EDGE('',*,*,#1319,.F.);
#1657=ORIENTED_EDGE('',*,*,#1637,.T.);
#1658=ORIENTED_EDGE('',*,*,#659,.F.);
#1659=EDGE_LOOP('',(#1655,#1656,#1657,#1658));
#1660=FACE_BOUND('',#1659,.T.);
#1661=ADVANCED_FACE('F982',(#1660),#1649,.T.);
#1662=CARTESIAN_POINT('',(-14.2788782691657,1.52259951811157,0.448786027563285));
#1663=DIRECTION('',(0.295063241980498,0.305546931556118,0.905305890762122));
#1664=DIRECTION('',(0.,-0.947490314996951,0.319784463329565));
#1665=AXIS2_PLACEMENT_3D('',#1662,#1663,#1664);
#1666=PLANE('',#1665);
#1667=ORIENTED_EDGE('',*,*,#324,.T.);
#1668=ORIENTED_EDGE('',*,*,#1332,.F.);
#1669=ORIENTED_EDGE('',*,*,#1654,.T.);
#1670=ORIENTED_EDGE('',*,*,#648,.F.);
#1671=EDGE_LOOP('',(#1667,#1668,#1669,#1670));
#1672=FACE_BOUND('',#1671,.T.);
#1673=ADVANCED_FACE('F984',(#1672),#1666,.F.);
#1674=CARTESIAN_POINT('',(-11.7901381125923,6.10242573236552,-3.52323713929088));
#1675=DIRECTION('',(0.719339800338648,-0.601591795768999,0.347329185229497));
#1676=DIRECTION('',(0.641531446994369,0.767096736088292,0.));
#1677=AXIS2_PLACEMENT_3D('',#1674,#1675,#1676);
#1678=CYLINDRICAL_SURFACE('',#1677,5.72);
#1679=DIRECTION('',(0.719339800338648,-0.601591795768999,0.347329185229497));
#1680=VECTOR('',#1679,1.);
#1681=CARTESIAN_POINT('',(-15.7513351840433,2.77443480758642,-1.08360721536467));
#1682=LINE('',#1681,#1680);
#1683=EDGE_CURVE('E1132',#1368,#607,#1682,.T.);
#1684=ORIENTED_EDGE('',*,*,#1683,.F.);
#1685=ORIENTED_EDGE('',*,*,#1369,.F.);
#1686=DIRECTION('',(0.719339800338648,-0.601591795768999,0.347329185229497));
#1687=VECTOR('',#1686,1.);
#1688=CARTESIAN_POINT('',(-15.7513351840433,2.32564878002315,-1.86092741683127));
#1689=LINE('',#1688,#1687);
#1690=EDGE_CURVE('E1129',#1349,#618,#1689,.T.);
#1691=ORIENTED_EDGE('',*,*,#1690,.T.);
#1692=ORIENTED_EDGE('',*,*,#619,.F.);
#1693=EDGE_LOOP('',(#1684,#1685,#1691,#1692));
#1694=FACE_BOUND('',#1693,.T.);
#1695=ADVANCED_FACE('F1100',(#1694),#1678,.T.);
#1696=CARTESIAN_POINT('',(-15.7513351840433,2.77443480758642,-1.08360721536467));
#1697=DIRECTION('',(0.295063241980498,0.717264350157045,0.631244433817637));
#1698=DIRECTION('',(0.,-0.660658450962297,0.750686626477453));
#1699=AXIS2_PLACEMENT_3D('',#1696,#1697,#1698);
#1700=PLANE('',#1699);
#1701=ORIENTED_EDGE('',*,*,#258,.T.);
#1702=ORIENTED_EDGE('',*,*,#1384,.F.);
#1703=ORIENTED_EDGE('',*,*,#1683,.T.);
#1704=ORIENTED_EDGE('',*,*,#608,.F.);
#1705=EDGE_LOOP('',(#1701,#1702,#1703,#1704));
#1706=FACE_BOUND('',#1705,.T.);
#1707=ADVANCED_FACE('F1021',(#1706),#1700,.F.);
#1708=CARTESIAN_POINT('',(-15.7513351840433,2.32564878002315,-1.86092741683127));
#1709=DIRECTION('',(0.295063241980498,-0.188041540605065,-0.936791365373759));
#1710=DIRECTION('',(-0.953806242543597,0.,-0.300422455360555));
#1711=AXIS2_PLACEMENT_3D('',#1708,#1709,#1710);
#1712=PLANE('',#1711);
#1713=ORIENTED_EDGE('',*,*,#1690,.F.);
#1714=ORIENTED_EDGE('',*,*,#1350,.F.);
#1715=ORIENTED_EDGE('',*,*,#309,.T.);
#1716=ORIENTED_EDGE('',*,*,#632,.F.);
#1717=EDGE_LOOP('',(#1713,#1714,#1715,#1716));
#1718=FACE_BOUND('',#1717,.T.);
#1719=ADVANCED_FACE('F1016',(#1718),#1712,.F.);
#1720=CARTESIAN_POINT('',(-10.386703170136,0.,-5.69119290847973));
#1721=DIRECTION('',(0.719339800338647,0.,0.694658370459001));
#1722=DIRECTION('',(0.694658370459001,0.,-0.719339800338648));
#1723=AXIS2_PLACEMENT_3D('',#1720,#1721,#1722);
#1724=CYLINDRICAL_SURFACE('',#1723,5.72);
#1725=DIRECTION('',(0.719339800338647,0.,0.694658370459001));
#1726=VECTOR('',#1725,1.);
#1727=CARTESIAN_POINT('',(-14.347900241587,0.44878602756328,-1.58925326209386));
#1728=LINE('',#1727,#1726);
#1729=EDGE_CURVE('E1124',#1462,#527,#1728,.T.);
#1730=ORIENTED_EDGE('',*,*,#1729,.F.);
#1731=ORIENTED_EDGE('',*,*,#1463,.F.);
#1732=DIRECTION('',(0.719339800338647,0.,0.694658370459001));
#1733=VECTOR('',#1732,1.);
#1734=CARTESIAN_POINT('',(-14.347900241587,-0.448786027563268,-1.58925326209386));
#1735=LINE('',#1734,#1733);
#1736=EDGE_CURVE('E364',#1451,#538,#1735,.T.);
#1737=ORIENTED_EDGE('',*,*,#1736,.T.);
#1738=ORIENTED_EDGE('',*,*,#539,.F.);
#1739=EDGE_LOOP('',(#1730,#1731,#1737,#1738));
#1740=FACE_BOUND('',#1739,.T.);
#1741=ADVANCED_FACE('F1020',(#1740),#1724,.T.);
#1742=CARTESIAN_POINT('',(-14.347900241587,-0.448786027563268,-1.58925326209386));
#1743=DIRECTION('',(0.295063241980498,-0.905305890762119,-0.305546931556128));
#1744=DIRECTION('',(0.,0.319784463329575,-0.947490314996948));
#1745=AXIS2_PLACEMENT_3D('',#1742,#1743,#1744);
#1746=PLANE('',#1745);
#1747=ORIENTED_EDGE('',*,*,#1736,.F.);
#1748=ORIENTED_EDGE('',*,*,#1452,.F.);
#1749=ORIENTED_EDGE('',*,*,#390,.T.);
#1750=ORIENTED_EDGE('',*,*,#552,.F.);
#1751=EDGE_LOOP('',(#1747,#1748,#1749,#1750));
#1752=FACE_BOUND('',#1751,.T.);
#1753=ADVANCED_FACE('F1054',(#1752),#1746,.F.);
#1754=CARTESIAN_POINT('',(-14.347900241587,0.44878602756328,-1.58925326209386));
#1755=DIRECTION('',(0.295063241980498,0.905305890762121,-0.305546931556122));
#1756=DIRECTION('',(0.,0.319784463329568,0.94749031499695));
#1757=AXIS2_PLACEMENT_3D('',#1754,#1755,#1756);
#1758=PLANE('',#1757);
#1759=ORIENTED_EDGE('',*,*,#276,.T.);
#1760=ORIENTED_EDGE('',*,*,#1476,.F.);
#1761=ORIENTED_EDGE('',*,*,#1729,.T.);
#1762=ORIENTED_EDGE('',*,*,#528,.F.);
#1763=EDGE_LOOP('',(#1759,#1760,#1761,#1762));
#1764=FACE_BOUND('',#1763,.T.);
#1765=ADVANCED_FACE('F1057',(#1764),#1758,.F.);
#1766=CARTESIAN_POINT('',(-11.8154019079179,3.53543562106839,-6.12355412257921));
#1767=DIRECTION('',(0.719339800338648,-0.347329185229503,0.601591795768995));
#1768=DIRECTION('',(0.641531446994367,0.,-0.767096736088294));
#1769=AXIS2_PLACEMENT_3D('',#1766,#1767,#1768);
#1770=CYLINDRICAL_SURFACE('',#1769,5.72);
#1771=DIRECTION('',(0.719339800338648,-0.347329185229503,0.601591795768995));
#1772=VECTOR('',#1771,1.);
#1773=CARTESIAN_POINT('',(-15.7765989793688,1.87312589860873,-2.34677717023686));
#1774=LINE('',#1773,#1772);
#1775=EDGE_CURVE('E1125',#1420,#567,#1774,.T.);
#1776=ORIENTED_EDGE('',*,*,#1775,.F.);
#1777=ORIENTED_EDGE('',*,*,#1421,.F.);
#1778=DIRECTION('',(0.719339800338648,-0.347329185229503,0.601591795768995));
#1779=VECTOR('',#1778,1.);
#1780=CARTESIAN_POINT('',(-15.7765989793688,1.09580569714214,-2.79556319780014));
#1781=LINE('',#1780,#1779);
#1782=EDGE_CURVE('E1119',#1401,#578,#1781,.T.);
#1783=ORIENTED_EDGE('',*,*,#1782,.T.);
#1784=ORIENTED_EDGE('',*,*,#579,.F.);
#1785=EDGE_LOOP('',(#1776,#1777,#1783,#1784));
#1786=FACE_BOUND('',#1785,.T.);
#1787=ADVANCED_FACE('F1059',(#1786),#1770,.T.);
#1788=CARTESIAN_POINT('',(-15.7765989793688,1.87312589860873,-2.34677717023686));
#1789=DIRECTION('',(0.295063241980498,0.936791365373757,0.188041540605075));
#1790=DIRECTION('',(-0.953806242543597,0.300422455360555,0.));
#1791=AXIS2_PLACEMENT_3D('',#1788,#1789,#1790);
#1792=PLANE('',#1791);
#1793=ORIENTED_EDGE('',*,*,#375,.T.);
#1794=ORIENTED_EDGE('',*,*,#1436,.F.);
#1795=ORIENTED_EDGE('',*,*,#1775,.T.);
#1796=ORIENTED_EDGE('',*,*,#568,.F.);
#1797=EDGE_LOOP('',(#1793,#1794,#1795,#1796));
#1798=FACE_BOUND('',#1797,.T.);
#1799=ADVANCED_FACE('F1090',(#1798),#1792,.F.);
#1800=CARTESIAN_POINT('',(-15.7765989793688,1.09580569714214,-2.79556319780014));
#1801=DIRECTION('',(0.295063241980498,-0.63124443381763,-0.717264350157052));
#1802=DIRECTION('',(0.,0.75068662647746,-0.660658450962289));
#1803=AXIS2_PLACEMENT_3D('',#1800,#1801,#1802);
#1804=PLANE('',#1803);
#1805=ORIENTED_EDGE('',*,*,#1782,.F.);
#1806=ORIENTED_EDGE('',*,*,#1402,.F.);
#1807=ORIENTED_EDGE('',*,*,#243,.T.);
#1808=ORIENTED_EDGE('',*,*,#592,.F.);
#1809=EDGE_LOOP('',(#1805,#1806,#1807,#1808));
#1810=FACE_BOUND('',#1809,.T.);
#1811=ADVANCED_FACE('F1093',(#1810),#1804,.F.);
#1812=CARTESIAN_POINT('',(-10.386703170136,0.,5.69119290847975));
#1813=DIRECTION('',(0.719339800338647,0.,-0.694658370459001));
#1814=DIRECTION('',(-0.694658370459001,0.,-0.719339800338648));
#1815=AXIS2_PLACEMENT_3D('',#1812,#1813,#1814);
#1816=CYLINDRICAL_SURFACE('',#1815,5.72);
#1817=DIRECTION('',(0.719339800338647,0.,-0.694658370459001));
#1818=VECTOR('',#1817,1.);
#1819=CARTESIAN_POINT('',(-14.347900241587,-0.448786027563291,1.58925326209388));
#1820=LINE('',#1819,#1818);
#1821=EDGE_CURVE('E1314',#1174,#767,#1820,.T.);
#1822=ORIENTED_EDGE('',*,*,#1821,.F.);
#1823=ORIENTED_EDGE('',*,*,#1175,.F.);
#1824=DIRECTION('',(0.719339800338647,0.,-0.694658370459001));
#1825=VECTOR('',#1824,1.);
#1826=CARTESIAN_POINT('',(-14.347900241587,0.448786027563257,1.58925326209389));
#1827=LINE('',#1826,#1825);
#1828=EDGE_CURVE('E1312',#1163,#778,#1827,.T.);
#1829=ORIENTED_EDGE('',*,*,#1828,.T.);
#1830=ORIENTED_EDGE('',*,*,#779,.F.);
#1831=EDGE_LOOP('',(#1822,#1823,#1829,#1830));
#1832=FACE_BOUND('',#1831,.T.);
#1833=ADVANCED_FACE('F860',(#1832),#1816,.T.);
#1834=CARTESIAN_POINT('',(-14.347900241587,-0.448786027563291,1.58925326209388));
#1835=DIRECTION('',(0.295063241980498,-0.905305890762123,0.305546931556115));
#1836=DIRECTION('',(0.,-0.319784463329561,-0.947490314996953));
#1837=AXIS2_PLACEMENT_3D('',#1834,#1835,#1836);
#1838=PLANE('',#1837);
#1839=ORIENTED_EDGE('',*,*,#126,.T.);
#1840=ORIENTED_EDGE('',*,*,#1188,.F.);
#1841=ORIENTED_EDGE('',*,*,#1821,.T.);
#1842=ORIENTED_EDGE('',*,*,#768,.F.);
#1843=EDGE_LOOP('',(#1839,#1840,#1841,#1842));
#1844=FACE_BOUND('',#1843,.T.);
#1845=ADVANCED_FACE('F853',(#1844),#1838,.F.);
#1846=CARTESIAN_POINT('',(-14.347900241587,0.448786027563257,1.58925326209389));
#1847=DIRECTION('',(0.295063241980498,0.905305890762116,0.305546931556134));
#1848=DIRECTION('',(0.,-0.319784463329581,0.947490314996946));
#1849=AXIS2_PLACEMENT_3D('',#1846,#1847,#1848);
#1850=PLANE('',#1849);
#1851=ORIENTED_EDGE('',*,*,#1828,.F.);
#1852=ORIENTED_EDGE('',*,*,#1164,.F.);
#1853=ORIENTED_EDGE('',*,*,#159,.T.);
#1854=ORIENTED_EDGE('',*,*,#792,.F.);
#1855=EDGE_LOOP('',(#1851,#1852,#1853,#1854));
#1856=FACE_BOUND('',#1855,.T.);
#1857=ADVANCED_FACE('F849',(#1856),#1850,.F.);
#1858=CARTESIAN_POINT('',(-11.8499128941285,-6.15241604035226,3.55209905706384));
#1859=DIRECTION('',(0.719339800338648,0.601591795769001,-0.347329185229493));
#1860=DIRECTION('',(-0.641531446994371,0.767096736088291,0.));
#1861=AXIS2_PLACEMENT_3D('',#1858,#1859,#1860);
#1862=CYLINDRICAL_SURFACE('',#1861,5.72);
#1863=DIRECTION('',(0.719339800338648,0.601591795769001,-0.347329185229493));
#1864=VECTOR('',#1863,1.);
#1865=CARTESIAN_POINT('',(-15.8111099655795,-2.82442511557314,1.11246913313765));
#1866=LINE('',#1865,#1864);
#1867=EDGE_CURVE('E1667',#1080,#847,#1866,.T.);
#1868=ORIENTED_EDGE('',*,*,#1867,.F.);
#1869=ORIENTED_EDGE('',*,*,#1081,.F.);
#1870=DIRECTION('',(0.719339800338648,0.601591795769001,-0.347329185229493));
#1871=VECTOR('',#1870,1.);
#1872=CARTESIAN_POINT('',(-15.8111099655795,-2.37563908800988,1.88978933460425));
#1873=LINE('',#1872,#1871);
#1874=EDGE_CURVE('E1666',#1061,#858,#1873,.T.);
#1875=ORIENTED_EDGE('',*,*,#1874,.T.);
#1876=ORIENTED_EDGE('',*,*,#859,.F.);
#1877=EDGE_LOOP('',(#1868,#1869,#1875,#1876));
#1878=FACE_BOUND('',#1877,.T.);
#1879=ADVANCED_FACE('F852',(#1878),#1862,.T.);
#1880=CARTESIAN_POINT('',(-15.8111099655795,-2.37563908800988,1.88978933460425));
#1881=DIRECTION('',(0.295063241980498,0.188041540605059,0.93679136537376));
#1882=DIRECTION('',(0.953806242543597,0.,-0.300422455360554));
#1883=AXIS2_PLACEMENT_3D('',#1880,#1881,#1882);
#1884=PLANE('',#1883);
#1885=ORIENTED_EDGE('',*,*,#1874,.F.);
#1886=ORIENTED_EDGE('',*,*,#1062,.F.);
#1887=ORIENTED_EDGE('',*,*,#210,.T.);
#1888=ORIENTED_EDGE('',*,*,#872,.F.);
#1889=EDGE_LOOP('',(#1885,#1886,#1887,#1888));
#1890=FACE_BOUND('',#1889,.T.);
#1891=ADVANCED_FACE('F892',(#1890),#1884,.F.);
#1892=CARTESIAN_POINT('',(-15.8111099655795,-2.82442511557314,1.11246913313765));
#1893=DIRECTION('',(0.295063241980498,-0.717264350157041,-0.631244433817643));
#1894=DIRECTION('',(0.,0.660658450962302,-0.750686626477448));
#1895=AXIS2_PLACEMENT_3D('',#1892,#1893,#1894);
#1896=PLANE('',#1895);
#1897=ORIENTED_EDGE('',*,*,#192,.T.);
#1898=ORIENTED_EDGE('',*,*,#1096,.F.);
#1899=ORIENTED_EDGE('',*,*,#1867,.T.);
#1900=ORIENTED_EDGE('',*,*,#848,.F.);
#1901=EDGE_LOOP('',(#1897,#1898,#1899,#1900));
#1902=FACE_BOUND('',#1901,.T.);
#1903=ADVANCED_FACE('F894',(#1902),#1896,.F.);
#1904=CARTESIAN_POINT('',(-11.8499128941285,-3.55209905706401,6.1524160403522));
#1905=DIRECTION('',(0.719339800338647,0.347329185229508,-0.601591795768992));
#1906=DIRECTION('',(-0.641531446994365,0.,-0.767096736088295));
#1907=AXIS2_PLACEMENT_3D('',#1904,#1905,#1906);
#1908=CYLINDRICAL_SURFACE('',#1907,5.72);
#1909=DIRECTION('',(0.719339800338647,0.347329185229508,-0.601591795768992));
#1910=VECTOR('',#1909,1.);
#1911=CARTESIAN_POINT('',(-15.8111099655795,-1.88978933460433,2.37563908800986));
#1912=LINE('',#1911,#1910);
#1913=EDGE_CURVE('E61',#1132,#807,#1912,.T.);
#1914=ORIENTED_EDGE('',*,*,#1913,.F.);
#1915=ORIENTED_EDGE('',*,*,#1133,.F.);
#1916=DIRECTION('',(0.719339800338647,0.347329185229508,-0.601591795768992));
#1917=VECTOR('',#1916,1.);
#1918=CARTESIAN_POINT('',(-15.8111099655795,-1.11246913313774,2.82442511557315));
#1919=LINE('',#1918,#1917);
#1920=EDGE_CURVE('E1320',#1113,#818,#1919,.T.);
#1921=ORIENTED_EDGE('',*,*,#1920,.T.);
#1922=ORIENTED_EDGE('',*,*,#819,.F.);
#1923=EDGE_LOOP('',(#1914,#1915,#1921,#1922));
#1924=FACE_BOUND('',#1923,.T.);
#1925=ADVANCED_FACE('F854',(#1924),#1908,.T.);
#1926=CARTESIAN_POINT('',(-15.8111099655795,-1.11246913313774,2.82442511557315));
#1927=DIRECTION('',(0.295063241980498,0.631244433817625,0.717264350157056));
#1928=DIRECTION('',(0.,-0.750686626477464,0.660658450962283));
#1929=AXIS2_PLACEMENT_3D('',#1926,#1927,#1928);
#1930=PLANE('',#1929);
#1931=ORIENTED_EDGE('',*,*,#1920,.F.);
#1932=ORIENTED_EDGE('',*,*,#1114,.F.);
#1933=ORIENTED_EDGE('',*,*,#177,.T.);
#1934=ORIENTED_EDGE('',*,*,#832,.F.);
#1935=EDGE_LOOP('',(#1931,#1932,#1933,#1934));
#1936=FACE_BOUND('',#1935,.T.);
#1937=ADVANCED_FACE('F896',(#1936),#1930,.F.);
#1938=CARTESIAN_POINT('',(-15.8111099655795,-1.88978933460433,2.37563908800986));
#1939=DIRECTION('',(0.295063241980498,-0.936791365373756,-0.188041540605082));
#1940=DIRECTION('',(0.953806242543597,0.300422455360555,0.));
#1941=AXIS2_PLACEMENT_3D('',#1938,#1939,#1940);
#1942=PLANE('',#1941);
#1943=ORIENTED_EDGE('',*,*,#144,.T.);
#1944=ORIENTED_EDGE('',*,*,#1148,.F.);
#1945=ORIENTED_EDGE('',*,*,#1913,.T.);
#1946=ORIENTED_EDGE('',*,*,#808,.F.);
#1947=EDGE_LOOP('',(#1943,#1944,#1945,#1946));
#1948=FACE_BOUND('',#1947,.T.);
#1949=ADVANCED_FACE('F900',(#1948),#1942,.F.);
#1950=CARTESIAN_POINT('',(-15.7765989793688,1.87312589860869,2.34677717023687));
#1951=DIRECTION('',(0.295063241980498,0.93679136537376,-0.188041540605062));
#1952=DIRECTION('',(-0.953806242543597,0.300422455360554,0.));
#1953=AXIS2_PLACEMENT_3D('',#1950,#1951,#1952);
#1954=PLANE('',#1953);
#1955=DIRECTION('',(0.719339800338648,-0.347329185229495,-0.601591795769));
#1956=VECTOR('',#1955,1.);
#1957=CARTESIAN_POINT('',(-15.7765989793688,1.87312589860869,2.34677717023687));
#1958=LINE('',#1957,#1956);
#1959=EDGE_CURVE('E1318',#1205,#738,#1958,.T.);
#1960=ORIENTED_EDGE('',*,*,#1959,.F.);
#1961=ORIENTED_EDGE('',*,*,#1206,.F.);
#1962=ORIENTED_EDGE('',*,*,#111,.T.);
#1963=ORIENTED_EDGE('',*,*,#752,.F.);
#1964=EDGE_LOOP('',(#1960,#1961,#1962,#1963));
#1965=FACE_BOUND('',#1964,.T.);
#1966=ADVANCED_FACE('F942',(#1965),#1954,.F.);
#1967=CARTESIAN_POINT('',(-15.7765989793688,1.09580569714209,2.79556319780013));
#1968=DIRECTION('',(0.295063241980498,-0.63124443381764,0.717264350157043));
#1969=DIRECTION('',(0.,-0.75068662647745,-0.660658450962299));
#1970=AXIS2_PLACEMENT_3D('',#1967,#1968,#1969);
#1971=PLANE('',#1970);
#1972=ORIENTED_EDGE('',*,*,#423,.T.);
#1973=ORIENTED_EDGE('',*,*,#1240,.F.);
#1974=DIRECTION('',(0.719339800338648,-0.347329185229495,-0.601591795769));
#1975=VECTOR('',#1974,1.);
#1976=CARTESIAN_POINT('',(-15.7765989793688,1.09580569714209,2.79556319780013));
#1977=LINE('',#1976,#1975);
#1978=EDGE_CURVE('E1315',#1224,#727,#1977,.T.);
#1979=ORIENTED_EDGE('',*,*,#1978,.T.);
#1980=ORIENTED_EDGE('',*,*,#728,.F.);
#1981=EDGE_LOOP('',(#1972,#1973,#1979,#1980));
#1982=FACE_BOUND('',#1981,.T.);
#1983=ADVANCED_FACE('F938',(#1982),#1971,.F.);
#1984=CARTESIAN_POINT('',(-11.8154019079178,3.53543562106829,6.12355412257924));
#1985=DIRECTION('',(0.719339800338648,-0.347329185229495,-0.601591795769));
#1986=DIRECTION('',(-0.64153144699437,0.,-0.767096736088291));
#1987=AXIS2_PLACEMENT_3D('',#1984,#1985,#1986);
#1988=CYLINDRICAL_SURFACE('',#1987,5.72);
#1989=ORIENTED_EDGE('',*,*,#1978,.F.);
#1990=ORIENTED_EDGE('',*,*,#1225,.F.);
#1991=ORIENTED_EDGE('',*,*,#1959,.T.);
#1992=ORIENTED_EDGE('',*,*,#739,.F.);
#1993=EDGE_LOOP('',(#1989,#1990,#1991,#1992));
#1994=FACE_BOUND('',#1993,.T.);
#1995=ADVANCED_FACE('F941',(#1994),#1988,.T.);
#1996=CARTESIAN_POINT('',(-15.7513351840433,2.77443480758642,1.08360721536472));
#1997=DIRECTION('',(0.295063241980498,0.717264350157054,-0.631244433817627));
#1998=DIRECTION('',(0.,0.660658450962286,0.750686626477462));
#1999=AXIS2_PLACEMENT_3D('',#1996,#1997,#1998);
#2000=PLANE('',#1999);
#2001=DIRECTION('',(0.719339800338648,-0.601591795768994,-0.347329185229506));
#2002=VECTOR('',#2001,1.);
#2003=CARTESIAN_POINT('',(-15.7513351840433,2.77443480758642,1.08360721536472));
#2004=LINE('',#2003,#2002);
#2005=EDGE_CURVE('E53',#1257,#698,#2004,.T.);
#2006=ORIENTED_EDGE('',*,*,#2005,.F.);
#2007=ORIENTED_EDGE('',*,*,#1258,.F.);
#2008=ORIENTED_EDGE('',*,*,#408,.T.);
#2009=ORIENTED_EDGE('',*,*,#712,.F.);
#2010=EDGE_LOOP('',(#2006,#2007,#2008,#2009));
#2011=FACE_BOUND('',#2010,.T.);
#2012=ADVANCED_FACE('F949',(#2011),#2000,.F.);
#2013=CARTESIAN_POINT('',(-11.7901381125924,6.10242573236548,3.52323713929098));
#2014=DIRECTION('',(0.719339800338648,-0.601591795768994,-0.347329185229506));
#2015=DIRECTION('',(0.641531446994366,0.767096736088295,0.));
#2016=AXIS2_PLACEMENT_3D('',#2013,#2014,#2015);
#2017=CYLINDRICAL_SURFACE('',#2016,5.72);
#2018=DIRECTION('',(0.719339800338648,-0.601591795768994,-0.347329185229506));
#2019=VECTOR('',#2018,1.);
#2020=CARTESIAN_POINT('',(-15.7513351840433,2.32564878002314,1.86092741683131));
#2021=LINE('',#2020,#2019);
#2022=EDGE_CURVE('E1265',#1276,#687,#2021,.T.);
#2023=ORIENTED_EDGE('',*,*,#2022,.F.);
#2024=ORIENTED_EDGE('',*,*,#1277,.F.);
#2025=ORIENTED_EDGE('',*,*,#2005,.T.);
#2026=ORIENTED_EDGE('',*,*,#699,.F.);
#2027=EDGE_LOOP('',(#2023,#2024,#2025,#2026));
#2028=FACE_BOUND('',#2027,.T.);
#2029=ADVANCED_FACE('F974',(#2028),#2017,.T.);
#2030=CARTESIAN_POINT('',(-15.7513351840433,2.32564878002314,1.86092741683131));
#2031=DIRECTION('',(0.295063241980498,-0.188041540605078,0.936791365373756));
#2032=DIRECTION('',(0.953806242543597,0.,-0.300422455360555));
#2033=AXIS2_PLACEMENT_3D('',#2030,#2031,#2032);
#2034=PLANE('',#2033);
#2035=ORIENTED_EDGE('',*,*,#78,.T.);
#2036=ORIENTED_EDGE('',*,*,#1292,.F.);
#2037=ORIENTED_EDGE('',*,*,#2022,.T.);
#2038=ORIENTED_EDGE('',*,*,#688,.F.);
#2039=EDGE_LOOP('',(#2035,#2036,#2037,#2038));
#2040=FACE_BOUND('',#2039,.T.);
#2041=ADVANCED_FACE('F656',(#2040),#2034,.F.);
#2042=CARTESIAN_POINT('',(-11.8499128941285,-6.15241604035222,-3.55209905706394));
#2043=DIRECTION('',(0.719339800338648,0.601591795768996,0.347329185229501));
#2044=DIRECTION('',(-0.641531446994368,0.767096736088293,0.));
#2045=AXIS2_PLACEMENT_3D('',#2042,#2043,#2044);
#2046=CYLINDRICAL_SURFACE('',#2045,5.72);
#2047=DIRECTION('',(0.719339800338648,0.601591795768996,0.347329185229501));
#2048=VECTOR('',#2047,1.);
#2049=CARTESIAN_POINT('',(-15.8111099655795,-2.37563908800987,-1.8897893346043));
#2050=LINE('',#2049,#2048);
#2051=EDGE_CURVE('E1137',#988,#447,#2050,.T.);
#2052=ORIENTED_EDGE('',*,*,#2051,.F.);
#2053=ORIENTED_EDGE('',*,*,#989,.F.);
#2054=DIRECTION('',(0.719339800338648,0.601591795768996,0.347329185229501));
#2055=VECTOR('',#2054,1.);
#2056=CARTESIAN_POINT('',(-15.8111099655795,-2.82442511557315,-1.1124691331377));
#2057=LINE('',#2056,#2055);
#2058=EDGE_CURVE('E355',#969,#458,#2057,.T.);
#2059=ORIENTED_EDGE('',*,*,#2058,.T.);
#2060=ORIENTED_EDGE('',*,*,#459,.F.);
#2061=EDGE_LOOP('',(#2052,#2053,#2059,#2060));
#2062=FACE_BOUND('',#2061,.T.);
#2063=ADVANCED_FACE('F652',(#2062),#2046,.T.);
#2064=CARTESIAN_POINT('',(-15.8111099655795,-2.82442511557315,-1.1124691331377));
#2065=DIRECTION('',(0.295063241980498,-0.71726435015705,0.631244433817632));
#2066=DIRECTION('',(0.,-0.660658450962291,-0.750686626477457));
#2067=AXIS2_PLACEMENT_3D('',#2064,#2065,#2066);
#2068=PLANE('',#2067);
#2069=ORIENTED_EDGE('',*,*,#2058,.F.);
#2070=ORIENTED_EDGE('',*,*,#970,.F.);
#2071=ORIENTED_EDGE('',*,*,#35,.T.);
#2072=ORIENTED_EDGE('',*,*,#472,.F.);
#2073=EDGE_LOOP('',(#2069,#2070,#2071,#2072));
#2074=FACE_BOUND('',#2073,.T.);
#2075=ADVANCED_FACE('F655',(#2074),#2068,.F.);
#2076=CARTESIAN_POINT('',(-15.8111099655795,-2.37563908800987,-1.8897893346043));
#2077=DIRECTION('',(0.295063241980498,0.188041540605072,-0.936791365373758));
#2078=DIRECTION('',(-0.953806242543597,0.,-0.300422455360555));
#2079=AXIS2_PLACEMENT_3D('',#2076,#2077,#2078);
#2080=PLANE('',#2079);
#2081=ORIENTED_EDGE('',*,*,#342,.T.);
#2082=ORIENTED_EDGE('',*,*,#1004,.F.);
#2083=ORIENTED_EDGE('',*,*,#2051,.T.);
#2084=ORIENTED_EDGE('',*,*,#448,.F.);
#2085=EDGE_LOOP('',(#2081,#2082,#2083,#2084));
#2086=FACE_BOUND('',#2085,.T.);
#2087=ADVANCED_FACE('F658',(#2086),#2080,.F.);
#2088=CLOSED_SHELL('',(#66,#99,#132,#165,#198,#231,#264,#297,#330,#363,#396,#429,#928,#948,
#1535,#1557,#1569,#1581,#1603,#1615,#1627,#1644,#1661,#1673,#1695,#1707,#1719,#1741,#1753,#1765,
#1787,#1799,#1811,#1833,#1845,#1857,#1879,#1891,#1903,#1925,#1937,#1949,#1966,#1983,#1995,#2012,
#2029,#2041,#2063,#2075,#2087));
#2089=MANIFOLD_SOLID_BREP('B2',#2088);
#2090=ADVANCED_BREP_SHAPE_REPRESENTATION('',(#18,#2089),#14);
#2091=SHAPE_DEFINITION_REPRESENTATION(#9,#2090);
ENDSEC;
END-ISO-10303-21;
